VERSION 5.8 ;
BUSBITCHARS "[]" ;
DIVIDERCHAR "/" ;
UNITS
    DATABASE MICRONS 1000 ;
END UNITS

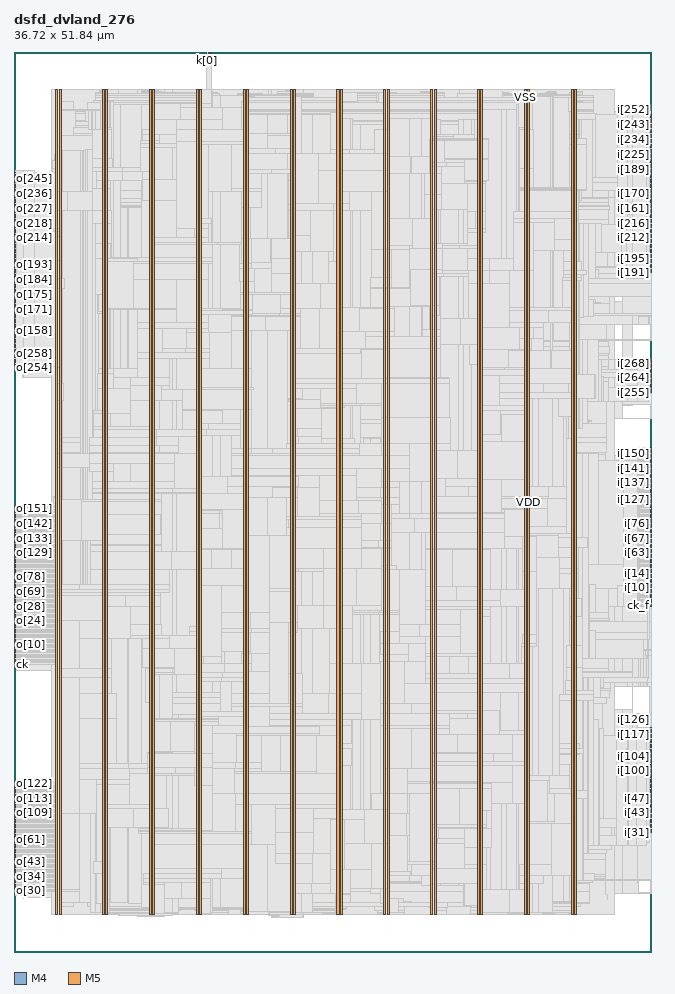
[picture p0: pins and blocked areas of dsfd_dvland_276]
MACRO dsfd_dvland_276
  FOREIGN dsfd_dvland_276 0 0 ;
  CLASS BLOCK ;
  SIZE 36.72 BY 51.84 ;
  PIN ck
    DIRECTION INPUT ;
    USE SIGNAL ;
    PORT
      LAYER M4 ;
        RECT  0 16.56 0.084 16.584 ;
    END
  END ck
  PIN ck_f
    DIRECTION INPUT ;
    USE SIGNAL ;
    PORT
      LAYER M4 ;
        RECT  36.636 19.92 36.72 19.944 ;
    END
  END ck_f
  PIN fault
    DIRECTION OUTPUT ;
    USE SIGNAL ;
    PORT
      LAYER M4 ;
        RECT  0 16.656 0.084 16.68 ;
    END
  END fault
  PIN i[0]
    DIRECTION INPUT ;
    USE SIGNAL ;
    PORT
      LAYER M4 ;
        RECT  36.636 20.016 36.72 20.04 ;
    END
  END i[0]
  PIN i[100]
    DIRECTION INPUT ;
    USE SIGNAL ;
    PORT
      LAYER M4 ;
        RECT  36.636 10.416 36.72 10.44 ;
    END
  END i[100]
  PIN i[101]
    DIRECTION INPUT ;
    USE SIGNAL ;
    PORT
      LAYER M4 ;
        RECT  36.636 10.512 36.72 10.536 ;
    END
  END i[101]
  PIN i[102]
    DIRECTION INPUT ;
    USE SIGNAL ;
    PORT
      LAYER M4 ;
        RECT  36.636 10.608 36.72 10.632 ;
    END
  END i[102]
  PIN i[103]
    DIRECTION INPUT ;
    USE SIGNAL ;
    PORT
      LAYER M4 ;
        RECT  36.636 10.704 36.72 10.728 ;
    END
  END i[103]
  PIN i[104]
    DIRECTION INPUT ;
    USE SIGNAL ;
    PORT
      LAYER M4 ;
        RECT  36.636 10.8 36.72 10.824 ;
    END
  END i[104]
  PIN i[105]
    DIRECTION INPUT ;
    USE SIGNAL ;
    PORT
      LAYER M4 ;
        RECT  36.636 10.896 36.72 10.92 ;
    END
  END i[105]
  PIN i[106]
    DIRECTION INPUT ;
    USE SIGNAL ;
    PORT
      LAYER M4 ;
        RECT  36.636 10.992 36.72 11.016 ;
    END
  END i[106]
  PIN i[107]
    DIRECTION INPUT ;
    USE SIGNAL ;
    PORT
      LAYER M4 ;
        RECT  36.636 11.088 36.72 11.112 ;
    END
  END i[107]
  PIN i[108]
    DIRECTION INPUT ;
    USE SIGNAL ;
    PORT
      LAYER M4 ;
        RECT  36.636 11.184 36.72 11.208 ;
    END
  END i[108]
  PIN i[109]
    DIRECTION INPUT ;
    USE SIGNAL ;
    PORT
      LAYER M4 ;
        RECT  36.636 11.28 36.72 11.304 ;
    END
  END i[109]
  PIN i[10]
    DIRECTION INPUT ;
    USE SIGNAL ;
    PORT
      LAYER M4 ;
        RECT  36.636 20.976 36.72 21 ;
    END
  END i[10]
  PIN i[110]
    DIRECTION INPUT ;
    USE SIGNAL ;
    PORT
      LAYER M4 ;
        RECT  36.636 11.376 36.72 11.4 ;
    END
  END i[110]
  PIN i[111]
    DIRECTION INPUT ;
    USE SIGNAL ;
    PORT
      LAYER M4 ;
        RECT  36.636 11.472 36.72 11.496 ;
    END
  END i[111]
  PIN i[112]
    DIRECTION INPUT ;
    USE SIGNAL ;
    PORT
      LAYER M4 ;
        RECT  36.636 11.568 36.72 11.592 ;
    END
  END i[112]
  PIN i[113]
    DIRECTION INPUT ;
    USE SIGNAL ;
    PORT
      LAYER M4 ;
        RECT  36.636 11.664 36.72 11.688 ;
    END
  END i[113]
  PIN i[114]
    DIRECTION INPUT ;
    USE SIGNAL ;
    PORT
      LAYER M4 ;
        RECT  36.636 11.76 36.72 11.784 ;
    END
  END i[114]
  PIN i[115]
    DIRECTION INPUT ;
    USE SIGNAL ;
    PORT
      LAYER M4 ;
        RECT  36.636 11.856 36.72 11.88 ;
    END
  END i[115]
  PIN i[116]
    DIRECTION INPUT ;
    USE SIGNAL ;
    PORT
      LAYER M4 ;
        RECT  36.636 11.952 36.72 11.976 ;
    END
  END i[116]
  PIN i[117]
    DIRECTION INPUT ;
    USE SIGNAL ;
    PORT
      LAYER M4 ;
        RECT  36.636 12.048 36.72 12.072 ;
    END
  END i[117]
  PIN i[118]
    DIRECTION INPUT ;
    USE SIGNAL ;
    PORT
      LAYER M4 ;
        RECT  36.636 12.144 36.72 12.168 ;
    END
  END i[118]
  PIN i[119]
    DIRECTION INPUT ;
    USE SIGNAL ;
    PORT
      LAYER M4 ;
        RECT  36.636 12.24 36.72 12.264 ;
    END
  END i[119]
  PIN i[11]
    DIRECTION INPUT ;
    USE SIGNAL ;
    PORT
      LAYER M4 ;
        RECT  36.636 21.072 36.72 21.096 ;
    END
  END i[11]
  PIN i[120]
    DIRECTION INPUT ;
    USE SIGNAL ;
    PORT
      LAYER M4 ;
        RECT  36.636 12.336 36.72 12.36 ;
    END
  END i[120]
  PIN i[121]
    DIRECTION INPUT ;
    USE SIGNAL ;
    PORT
      LAYER M4 ;
        RECT  36.636 12.432 36.72 12.456 ;
    END
  END i[121]
  PIN i[122]
    DIRECTION INPUT ;
    USE SIGNAL ;
    PORT
      LAYER M4 ;
        RECT  36.636 12.528 36.72 12.552 ;
    END
  END i[122]
  PIN i[123]
    DIRECTION INPUT ;
    USE SIGNAL ;
    PORT
      LAYER M4 ;
        RECT  36.636 12.624 36.72 12.648 ;
    END
  END i[123]
  PIN i[124]
    DIRECTION INPUT ;
    USE SIGNAL ;
    PORT
      LAYER M4 ;
        RECT  36.636 12.72 36.72 12.744 ;
    END
  END i[124]
  PIN i[125]
    DIRECTION INPUT ;
    USE SIGNAL ;
    PORT
      LAYER M4 ;
        RECT  36.636 12.816 36.72 12.84 ;
    END
  END i[125]
  PIN i[126]
    DIRECTION INPUT ;
    USE SIGNAL ;
    PORT
      LAYER M4 ;
        RECT  36.636 12.912 36.72 12.936 ;
    END
  END i[126]
  PIN i[127]
    DIRECTION INPUT ;
    USE SIGNAL ;
    PORT
      LAYER M4 ;
        RECT  36.636 26.064 36.72 26.088 ;
    END
  END i[127]
  PIN i[128]
    DIRECTION INPUT ;
    USE SIGNAL ;
    PORT
      LAYER M4 ;
        RECT  36.636 26.16 36.72 26.184 ;
    END
  END i[128]
  PIN i[129]
    DIRECTION INPUT ;
    USE SIGNAL ;
    PORT
      LAYER M4 ;
        RECT  36.636 26.256 36.72 26.28 ;
    END
  END i[129]
  PIN i[12]
    DIRECTION INPUT ;
    USE SIGNAL ;
    PORT
      LAYER M4 ;
        RECT  36.636 21.168 36.72 21.192 ;
    END
  END i[12]
  PIN i[130]
    DIRECTION INPUT ;
    USE SIGNAL ;
    PORT
      LAYER M4 ;
        RECT  36.636 26.352 36.72 26.376 ;
    END
  END i[130]
  PIN i[131]
    DIRECTION INPUT ;
    USE SIGNAL ;
    PORT
      LAYER M4 ;
        RECT  36.636 26.448 36.72 26.472 ;
    END
  END i[131]
  PIN i[132]
    DIRECTION INPUT ;
    USE SIGNAL ;
    PORT
      LAYER M4 ;
        RECT  36.636 26.544 36.72 26.568 ;
    END
  END i[132]
  PIN i[133]
    DIRECTION INPUT ;
    USE SIGNAL ;
    PORT
      LAYER M4 ;
        RECT  36.636 26.64 36.72 26.664 ;
    END
  END i[133]
  PIN i[134]
    DIRECTION INPUT ;
    USE SIGNAL ;
    PORT
      LAYER M4 ;
        RECT  36.636 26.736 36.72 26.76 ;
    END
  END i[134]
  PIN i[135]
    DIRECTION INPUT ;
    USE SIGNAL ;
    PORT
      LAYER M4 ;
        RECT  36.636 26.832 36.72 26.856 ;
    END
  END i[135]
  PIN i[136]
    DIRECTION INPUT ;
    USE SIGNAL ;
    PORT
      LAYER M4 ;
        RECT  36.636 26.928 36.72 26.952 ;
    END
  END i[136]
  PIN i[137]
    DIRECTION INPUT ;
    USE SIGNAL ;
    PORT
      LAYER M4 ;
        RECT  36.636 27.024 36.72 27.048 ;
    END
  END i[137]
  PIN i[138]
    DIRECTION INPUT ;
    USE SIGNAL ;
    PORT
      LAYER M4 ;
        RECT  36.636 27.12 36.72 27.144 ;
    END
  END i[138]
  PIN i[139]
    DIRECTION INPUT ;
    USE SIGNAL ;
    PORT
      LAYER M4 ;
        RECT  36.636 27.216 36.72 27.24 ;
    END
  END i[139]
  PIN i[13]
    DIRECTION INPUT ;
    USE SIGNAL ;
    PORT
      LAYER M4 ;
        RECT  36.636 21.264 36.72 21.288 ;
    END
  END i[13]
  PIN i[140]
    DIRECTION INPUT ;
    USE SIGNAL ;
    PORT
      LAYER M4 ;
        RECT  36.636 27.312 36.72 27.336 ;
    END
  END i[140]
  PIN i[141]
    DIRECTION INPUT ;
    USE SIGNAL ;
    PORT
      LAYER M4 ;
        RECT  36.636 27.408 36.72 27.432 ;
    END
  END i[141]
  PIN i[142]
    DIRECTION INPUT ;
    USE SIGNAL ;
    PORT
      LAYER M4 ;
        RECT  36.636 27.504 36.72 27.528 ;
    END
  END i[142]
  PIN i[143]
    DIRECTION INPUT ;
    USE SIGNAL ;
    PORT
      LAYER M4 ;
        RECT  36.636 27.6 36.72 27.624 ;
    END
  END i[143]
  PIN i[144]
    DIRECTION INPUT ;
    USE SIGNAL ;
    PORT
      LAYER M4 ;
        RECT  36.636 27.696 36.72 27.72 ;
    END
  END i[144]
  PIN i[145]
    DIRECTION INPUT ;
    USE SIGNAL ;
    PORT
      LAYER M4 ;
        RECT  36.636 27.792 36.72 27.816 ;
    END
  END i[145]
  PIN i[146]
    DIRECTION INPUT ;
    USE SIGNAL ;
    PORT
      LAYER M4 ;
        RECT  36.636 27.888 36.72 27.912 ;
    END
  END i[146]
  PIN i[147]
    DIRECTION INPUT ;
    USE SIGNAL ;
    PORT
      LAYER M4 ;
        RECT  36.636 27.984 36.72 28.008 ;
    END
  END i[147]
  PIN i[148]
    DIRECTION INPUT ;
    USE SIGNAL ;
    PORT
      LAYER M4 ;
        RECT  36.636 28.08 36.72 28.104 ;
    END
  END i[148]
  PIN i[149]
    DIRECTION INPUT ;
    USE SIGNAL ;
    PORT
      LAYER M4 ;
        RECT  36.636 28.176 36.72 28.2 ;
    END
  END i[149]
  PIN i[14]
    DIRECTION INPUT ;
    USE SIGNAL ;
    PORT
      LAYER M4 ;
        RECT  36.636 21.36 36.72 21.384 ;
    END
  END i[14]
  PIN i[150]
    DIRECTION INPUT ;
    USE SIGNAL ;
    PORT
      LAYER M4 ;
        RECT  36.636 28.272 36.72 28.296 ;
    END
  END i[150]
  PIN i[151]
    DIRECTION INPUT ;
    USE SIGNAL ;
    PORT
      LAYER M4 ;
        RECT  36.636 28.368 36.72 28.392 ;
    END
  END i[151]
  PIN i[152]
    DIRECTION INPUT ;
    USE SIGNAL ;
    PORT
      LAYER M4 ;
        RECT  36.636 28.464 36.72 28.488 ;
    END
  END i[152]
  PIN i[153]
    DIRECTION INPUT ;
    USE SIGNAL ;
    PORT
      LAYER M4 ;
        RECT  36.636 28.56 36.72 28.584 ;
    END
  END i[153]
  PIN i[154]
    DIRECTION INPUT ;
    USE SIGNAL ;
    PORT
      LAYER M4 ;
        RECT  36.636 28.656 36.72 28.68 ;
    END
  END i[154]
  PIN i[155]
    DIRECTION INPUT ;
    USE SIGNAL ;
    PORT
      LAYER M4 ;
        RECT  36.636 28.752 36.72 28.776 ;
    END
  END i[155]
  PIN i[156]
    DIRECTION INPUT ;
    USE SIGNAL ;
    PORT
      LAYER M4 ;
        RECT  36.636 28.848 36.72 28.872 ;
    END
  END i[156]
  PIN i[157]
    DIRECTION INPUT ;
    USE SIGNAL ;
    PORT
      LAYER M4 ;
        RECT  36.636 28.944 36.72 28.968 ;
    END
  END i[157]
  PIN i[158]
    DIRECTION INPUT ;
    USE SIGNAL ;
    PORT
      LAYER M4 ;
        RECT  36.636 29.04 36.72 29.064 ;
    END
  END i[158]
  PIN i[159]
    DIRECTION INPUT ;
    USE SIGNAL ;
    PORT
      LAYER M4 ;
        RECT  36.636 42.192 36.72 42.216 ;
    END
  END i[159]
  PIN i[15]
    DIRECTION INPUT ;
    USE SIGNAL ;
    PORT
      LAYER M4 ;
        RECT  36.636 21.456 36.72 21.48 ;
    END
  END i[15]
  PIN i[160]
    DIRECTION INPUT ;
    USE SIGNAL ;
    PORT
      LAYER M4 ;
        RECT  36.636 42.288 36.72 42.312 ;
    END
  END i[160]
  PIN i[161]
    DIRECTION INPUT ;
    USE SIGNAL ;
    PORT
      LAYER M4 ;
        RECT  36.636 42.384 36.72 42.408 ;
    END
  END i[161]
  PIN i[162]
    DIRECTION INPUT ;
    USE SIGNAL ;
    PORT
      LAYER M4 ;
        RECT  36.636 42.48 36.72 42.504 ;
    END
  END i[162]
  PIN i[163]
    DIRECTION INPUT ;
    USE SIGNAL ;
    PORT
      LAYER M4 ;
        RECT  36.636 42.576 36.72 42.6 ;
    END
  END i[163]
  PIN i[164]
    DIRECTION INPUT ;
    USE SIGNAL ;
    PORT
      LAYER M4 ;
        RECT  36.636 42.672 36.72 42.696 ;
    END
  END i[164]
  PIN i[165]
    DIRECTION INPUT ;
    USE SIGNAL ;
    PORT
      LAYER M4 ;
        RECT  36.636 42.768 36.72 42.792 ;
    END
  END i[165]
  PIN i[166]
    DIRECTION INPUT ;
    USE SIGNAL ;
    PORT
      LAYER M4 ;
        RECT  36.636 42.864 36.72 42.888 ;
    END
  END i[166]
  PIN i[167]
    DIRECTION INPUT ;
    USE SIGNAL ;
    PORT
      LAYER M4 ;
        RECT  36.636 42.96 36.72 42.984 ;
    END
  END i[167]
  PIN i[168]
    DIRECTION INPUT ;
    USE SIGNAL ;
    PORT
      LAYER M4 ;
        RECT  36.636 43.056 36.72 43.08 ;
    END
  END i[168]
  PIN i[169]
    DIRECTION INPUT ;
    USE SIGNAL ;
    PORT
      LAYER M4 ;
        RECT  36.636 43.152 36.72 43.176 ;
    END
  END i[169]
  PIN i[16]
    DIRECTION INPUT ;
    USE SIGNAL ;
    PORT
      LAYER M4 ;
        RECT  36.636 21.552 36.72 21.576 ;
    END
  END i[16]
  PIN i[170]
    DIRECTION INPUT ;
    USE SIGNAL ;
    PORT
      LAYER M4 ;
        RECT  36.636 43.248 36.72 43.272 ;
    END
  END i[170]
  PIN i[171]
    DIRECTION INPUT ;
    USE SIGNAL ;
    PORT
      LAYER M4 ;
        RECT  36.636 43.344 36.72 43.368 ;
    END
  END i[171]
  PIN i[172]
    DIRECTION INPUT ;
    USE SIGNAL ;
    PORT
      LAYER M4 ;
        RECT  36.636 43.44 36.72 43.464 ;
    END
  END i[172]
  PIN i[173]
    DIRECTION INPUT ;
    USE SIGNAL ;
    PORT
      LAYER M4 ;
        RECT  36.636 43.536 36.72 43.56 ;
    END
  END i[173]
  PIN i[174]
    DIRECTION INPUT ;
    USE SIGNAL ;
    PORT
      LAYER M4 ;
        RECT  36.636 43.632 36.72 43.656 ;
    END
  END i[174]
  PIN i[175]
    DIRECTION INPUT ;
    USE SIGNAL ;
    PORT
      LAYER M4 ;
        RECT  36.636 43.728 36.72 43.752 ;
    END
  END i[175]
  PIN i[176]
    DIRECTION INPUT ;
    USE SIGNAL ;
    PORT
      LAYER M4 ;
        RECT  36.636 43.824 36.72 43.848 ;
    END
  END i[176]
  PIN i[177]
    DIRECTION INPUT ;
    USE SIGNAL ;
    PORT
      LAYER M4 ;
        RECT  36.636 43.92 36.72 43.944 ;
    END
  END i[177]
  PIN i[178]
    DIRECTION INPUT ;
    USE SIGNAL ;
    PORT
      LAYER M4 ;
        RECT  36.636 44.016 36.72 44.04 ;
    END
  END i[178]
  PIN i[179]
    DIRECTION INPUT ;
    USE SIGNAL ;
    PORT
      LAYER M4 ;
        RECT  36.636 44.112 36.72 44.136 ;
    END
  END i[179]
  PIN i[17]
    DIRECTION INPUT ;
    USE SIGNAL ;
    PORT
      LAYER M4 ;
        RECT  36.636 21.648 36.72 21.672 ;
    END
  END i[17]
  PIN i[180]
    DIRECTION INPUT ;
    USE SIGNAL ;
    PORT
      LAYER M4 ;
        RECT  36.636 44.208 36.72 44.232 ;
    END
  END i[180]
  PIN i[181]
    DIRECTION INPUT ;
    USE SIGNAL ;
    PORT
      LAYER M4 ;
        RECT  36.636 44.304 36.72 44.328 ;
    END
  END i[181]
  PIN i[182]
    DIRECTION INPUT ;
    USE SIGNAL ;
    PORT
      LAYER M4 ;
        RECT  36.636 44.4 36.72 44.424 ;
    END
  END i[182]
  PIN i[183]
    DIRECTION INPUT ;
    USE SIGNAL ;
    PORT
      LAYER M4 ;
        RECT  36.636 44.496 36.72 44.52 ;
    END
  END i[183]
  PIN i[184]
    DIRECTION INPUT ;
    USE SIGNAL ;
    PORT
      LAYER M4 ;
        RECT  36.636 44.592 36.72 44.616 ;
    END
  END i[184]
  PIN i[185]
    DIRECTION INPUT ;
    USE SIGNAL ;
    PORT
      LAYER M4 ;
        RECT  36.636 44.688 36.72 44.712 ;
    END
  END i[185]
  PIN i[186]
    DIRECTION INPUT ;
    USE SIGNAL ;
    PORT
      LAYER M4 ;
        RECT  36.636 44.784 36.72 44.808 ;
    END
  END i[186]
  PIN i[187]
    DIRECTION INPUT ;
    USE SIGNAL ;
    PORT
      LAYER M4 ;
        RECT  36.636 44.88 36.72 44.904 ;
    END
  END i[187]
  PIN i[188]
    DIRECTION INPUT ;
    USE SIGNAL ;
    PORT
      LAYER M4 ;
        RECT  36.636 44.976 36.72 45 ;
    END
  END i[188]
  PIN i[189]
    DIRECTION INPUT ;
    USE SIGNAL ;
    PORT
      LAYER M4 ;
        RECT  36.636 45.072 36.72 45.096 ;
    END
  END i[189]
  PIN i[18]
    DIRECTION INPUT ;
    USE SIGNAL ;
    PORT
      LAYER M4 ;
        RECT  36.636 21.744 36.72 21.768 ;
    END
  END i[18]
  PIN i[190]
    DIRECTION INPUT ;
    USE SIGNAL ;
    PORT
      LAYER M4 ;
        RECT  36.636 45.168 36.72 45.192 ;
    END
  END i[190]
  PIN i[191]
    DIRECTION INPUT ;
    USE SIGNAL ;
    PORT
      LAYER M4 ;
        RECT  36.636 39.12 36.72 39.144 ;
    END
  END i[191]
  PIN i[192]
    DIRECTION INPUT ;
    USE SIGNAL ;
    PORT
      LAYER M4 ;
        RECT  36.636 39.216 36.72 39.24 ;
    END
  END i[192]
  PIN i[193]
    DIRECTION INPUT ;
    USE SIGNAL ;
    PORT
      LAYER M4 ;
        RECT  36.636 39.312 36.72 39.336 ;
    END
  END i[193]
  PIN i[194]
    DIRECTION INPUT ;
    USE SIGNAL ;
    PORT
      LAYER M4 ;
        RECT  36.636 39.408 36.72 39.432 ;
    END
  END i[194]
  PIN i[195]
    DIRECTION INPUT ;
    USE SIGNAL ;
    PORT
      LAYER M4 ;
        RECT  36.636 39.504 36.72 39.528 ;
    END
  END i[195]
  PIN i[196]
    DIRECTION INPUT ;
    USE SIGNAL ;
    PORT
      LAYER M4 ;
        RECT  36.636 39.6 36.72 39.624 ;
    END
  END i[196]
  PIN i[197]
    DIRECTION INPUT ;
    USE SIGNAL ;
    PORT
      LAYER M4 ;
        RECT  36.636 39.696 36.72 39.72 ;
    END
  END i[197]
  PIN i[198]
    DIRECTION INPUT ;
    USE SIGNAL ;
    PORT
      LAYER M4 ;
        RECT  36.636 39.792 36.72 39.816 ;
    END
  END i[198]
  PIN i[199]
    DIRECTION INPUT ;
    USE SIGNAL ;
    PORT
      LAYER M4 ;
        RECT  36.636 39.888 36.72 39.912 ;
    END
  END i[199]
  PIN i[19]
    DIRECTION INPUT ;
    USE SIGNAL ;
    PORT
      LAYER M4 ;
        RECT  36.636 21.84 36.72 21.864 ;
    END
  END i[19]
  PIN i[1]
    DIRECTION INPUT ;
    USE SIGNAL ;
    PORT
      LAYER M4 ;
        RECT  36.636 20.112 36.72 20.136 ;
    END
  END i[1]
  PIN i[200]
    DIRECTION INPUT ;
    USE SIGNAL ;
    PORT
      LAYER M4 ;
        RECT  36.636 39.984 36.72 40.008 ;
    END
  END i[200]
  PIN i[201]
    DIRECTION INPUT ;
    USE SIGNAL ;
    PORT
      LAYER M4 ;
        RECT  36.636 40.08 36.72 40.104 ;
    END
  END i[201]
  PIN i[202]
    DIRECTION INPUT ;
    USE SIGNAL ;
    PORT
      LAYER M4 ;
        RECT  36.636 40.176 36.72 40.2 ;
    END
  END i[202]
  PIN i[203]
    DIRECTION INPUT ;
    USE SIGNAL ;
    PORT
      LAYER M4 ;
        RECT  36.636 40.272 36.72 40.296 ;
    END
  END i[203]
  PIN i[204]
    DIRECTION INPUT ;
    USE SIGNAL ;
    PORT
      LAYER M4 ;
        RECT  36.636 40.368 36.72 40.392 ;
    END
  END i[204]
  PIN i[205]
    DIRECTION INPUT ;
    USE SIGNAL ;
    PORT
      LAYER M4 ;
        RECT  36.636 40.464 36.72 40.488 ;
    END
  END i[205]
  PIN i[206]
    DIRECTION INPUT ;
    USE SIGNAL ;
    PORT
      LAYER M4 ;
        RECT  36.636 40.56 36.72 40.584 ;
    END
  END i[206]
  PIN i[207]
    DIRECTION INPUT ;
    USE SIGNAL ;
    PORT
      LAYER M4 ;
        RECT  36.636 40.656 36.72 40.68 ;
    END
  END i[207]
  PIN i[208]
    DIRECTION INPUT ;
    USE SIGNAL ;
    PORT
      LAYER M4 ;
        RECT  36.636 40.752 36.72 40.776 ;
    END
  END i[208]
  PIN i[209]
    DIRECTION INPUT ;
    USE SIGNAL ;
    PORT
      LAYER M4 ;
        RECT  36.636 40.848 36.72 40.872 ;
    END
  END i[209]
  PIN i[20]
    DIRECTION INPUT ;
    USE SIGNAL ;
    PORT
      LAYER M4 ;
        RECT  36.636 21.936 36.72 21.96 ;
    END
  END i[20]
  PIN i[210]
    DIRECTION INPUT ;
    USE SIGNAL ;
    PORT
      LAYER M4 ;
        RECT  36.636 40.944 36.72 40.968 ;
    END
  END i[210]
  PIN i[211]
    DIRECTION INPUT ;
    USE SIGNAL ;
    PORT
      LAYER M4 ;
        RECT  36.636 41.04 36.72 41.064 ;
    END
  END i[211]
  PIN i[212]
    DIRECTION INPUT ;
    USE SIGNAL ;
    PORT
      LAYER M4 ;
        RECT  36.636 41.136 36.72 41.16 ;
    END
  END i[212]
  PIN i[213]
    DIRECTION INPUT ;
    USE SIGNAL ;
    PORT
      LAYER M4 ;
        RECT  36.636 41.232 36.72 41.256 ;
    END
  END i[213]
  PIN i[214]
    DIRECTION INPUT ;
    USE SIGNAL ;
    PORT
      LAYER M4 ;
        RECT  36.636 41.328 36.72 41.352 ;
    END
  END i[214]
  PIN i[215]
    DIRECTION INPUT ;
    USE SIGNAL ;
    PORT
      LAYER M4 ;
        RECT  36.636 41.424 36.72 41.448 ;
    END
  END i[215]
  PIN i[216]
    DIRECTION INPUT ;
    USE SIGNAL ;
    PORT
      LAYER M4 ;
        RECT  36.636 41.52 36.72 41.544 ;
    END
  END i[216]
  PIN i[217]
    DIRECTION INPUT ;
    USE SIGNAL ;
    PORT
      LAYER M4 ;
        RECT  36.636 41.616 36.72 41.64 ;
    END
  END i[217]
  PIN i[218]
    DIRECTION INPUT ;
    USE SIGNAL ;
    PORT
      LAYER M4 ;
        RECT  36.636 41.712 36.72 41.736 ;
    END
  END i[218]
  PIN i[219]
    DIRECTION INPUT ;
    USE SIGNAL ;
    PORT
      LAYER M4 ;
        RECT  36.636 41.808 36.72 41.832 ;
    END
  END i[219]
  PIN i[21]
    DIRECTION INPUT ;
    USE SIGNAL ;
    PORT
      LAYER M4 ;
        RECT  36.636 22.032 36.72 22.056 ;
    END
  END i[21]
  PIN i[220]
    DIRECTION INPUT ;
    USE SIGNAL ;
    PORT
      LAYER M4 ;
        RECT  36.636 41.904 36.72 41.928 ;
    END
  END i[220]
  PIN i[221]
    DIRECTION INPUT ;
    USE SIGNAL ;
    PORT
      LAYER M4 ;
        RECT  36.636 42 36.72 42.024 ;
    END
  END i[221]
  PIN i[222]
    DIRECTION INPUT ;
    USE SIGNAL ;
    PORT
      LAYER M4 ;
        RECT  36.636 42.096 36.72 42.12 ;
    END
  END i[222]
  PIN i[223]
    DIRECTION INPUT ;
    USE SIGNAL ;
    PORT
      LAYER M4 ;
        RECT  36.636 45.264 36.72 45.288 ;
    END
  END i[223]
  PIN i[224]
    DIRECTION INPUT ;
    USE SIGNAL ;
    PORT
      LAYER M4 ;
        RECT  36.636 45.36 36.72 45.384 ;
    END
  END i[224]
  PIN i[225]
    DIRECTION INPUT ;
    USE SIGNAL ;
    PORT
      LAYER M4 ;
        RECT  36.636 45.456 36.72 45.48 ;
    END
  END i[225]
  PIN i[226]
    DIRECTION INPUT ;
    USE SIGNAL ;
    PORT
      LAYER M4 ;
        RECT  36.636 45.552 36.72 45.576 ;
    END
  END i[226]
  PIN i[227]
    DIRECTION INPUT ;
    USE SIGNAL ;
    PORT
      LAYER M4 ;
        RECT  36.636 45.648 36.72 45.672 ;
    END
  END i[227]
  PIN i[228]
    DIRECTION INPUT ;
    USE SIGNAL ;
    PORT
      LAYER M4 ;
        RECT  36.636 45.744 36.72 45.768 ;
    END
  END i[228]
  PIN i[229]
    DIRECTION INPUT ;
    USE SIGNAL ;
    PORT
      LAYER M4 ;
        RECT  36.636 45.84 36.72 45.864 ;
    END
  END i[229]
  PIN i[22]
    DIRECTION INPUT ;
    USE SIGNAL ;
    PORT
      LAYER M4 ;
        RECT  36.636 22.128 36.72 22.152 ;
    END
  END i[22]
  PIN i[230]
    DIRECTION INPUT ;
    USE SIGNAL ;
    PORT
      LAYER M4 ;
        RECT  36.636 45.936 36.72 45.96 ;
    END
  END i[230]
  PIN i[231]
    DIRECTION INPUT ;
    USE SIGNAL ;
    PORT
      LAYER M4 ;
        RECT  36.636 46.032 36.72 46.056 ;
    END
  END i[231]
  PIN i[232]
    DIRECTION INPUT ;
    USE SIGNAL ;
    PORT
      LAYER M4 ;
        RECT  36.636 46.128 36.72 46.152 ;
    END
  END i[232]
  PIN i[233]
    DIRECTION INPUT ;
    USE SIGNAL ;
    PORT
      LAYER M4 ;
        RECT  36.636 46.224 36.72 46.248 ;
    END
  END i[233]
  PIN i[234]
    DIRECTION INPUT ;
    USE SIGNAL ;
    PORT
      LAYER M4 ;
        RECT  36.636 46.32 36.72 46.344 ;
    END
  END i[234]
  PIN i[235]
    DIRECTION INPUT ;
    USE SIGNAL ;
    PORT
      LAYER M4 ;
        RECT  36.636 46.416 36.72 46.44 ;
    END
  END i[235]
  PIN i[236]
    DIRECTION INPUT ;
    USE SIGNAL ;
    PORT
      LAYER M4 ;
        RECT  36.636 46.512 36.72 46.536 ;
    END
  END i[236]
  PIN i[237]
    DIRECTION INPUT ;
    USE SIGNAL ;
    PORT
      LAYER M4 ;
        RECT  36.636 46.608 36.72 46.632 ;
    END
  END i[237]
  PIN i[238]
    DIRECTION INPUT ;
    USE SIGNAL ;
    PORT
      LAYER M4 ;
        RECT  36.636 46.704 36.72 46.728 ;
    END
  END i[238]
  PIN i[239]
    DIRECTION INPUT ;
    USE SIGNAL ;
    PORT
      LAYER M4 ;
        RECT  36.636 46.8 36.72 46.824 ;
    END
  END i[239]
  PIN i[23]
    DIRECTION INPUT ;
    USE SIGNAL ;
    PORT
      LAYER M4 ;
        RECT  36.636 22.224 36.72 22.248 ;
    END
  END i[23]
  PIN i[240]
    DIRECTION INPUT ;
    USE SIGNAL ;
    PORT
      LAYER M4 ;
        RECT  36.636 46.896 36.72 46.92 ;
    END
  END i[240]
  PIN i[241]
    DIRECTION INPUT ;
    USE SIGNAL ;
    PORT
      LAYER M4 ;
        RECT  36.636 46.992 36.72 47.016 ;
    END
  END i[241]
  PIN i[242]
    DIRECTION INPUT ;
    USE SIGNAL ;
    PORT
      LAYER M4 ;
        RECT  36.636 47.088 36.72 47.112 ;
    END
  END i[242]
  PIN i[243]
    DIRECTION INPUT ;
    USE SIGNAL ;
    PORT
      LAYER M4 ;
        RECT  36.636 47.184 36.72 47.208 ;
    END
  END i[243]
  PIN i[244]
    DIRECTION INPUT ;
    USE SIGNAL ;
    PORT
      LAYER M4 ;
        RECT  36.636 47.28 36.72 47.304 ;
    END
  END i[244]
  PIN i[245]
    DIRECTION INPUT ;
    USE SIGNAL ;
    PORT
      LAYER M4 ;
        RECT  36.636 47.376 36.72 47.4 ;
    END
  END i[245]
  PIN i[246]
    DIRECTION INPUT ;
    USE SIGNAL ;
    PORT
      LAYER M4 ;
        RECT  36.636 47.472 36.72 47.496 ;
    END
  END i[246]
  PIN i[247]
    DIRECTION INPUT ;
    USE SIGNAL ;
    PORT
      LAYER M4 ;
        RECT  36.636 47.568 36.72 47.592 ;
    END
  END i[247]
  PIN i[248]
    DIRECTION INPUT ;
    USE SIGNAL ;
    PORT
      LAYER M4 ;
        RECT  36.636 47.664 36.72 47.688 ;
    END
  END i[248]
  PIN i[249]
    DIRECTION INPUT ;
    USE SIGNAL ;
    PORT
      LAYER M4 ;
        RECT  36.636 47.76 36.72 47.784 ;
    END
  END i[249]
  PIN i[24]
    DIRECTION INPUT ;
    USE SIGNAL ;
    PORT
      LAYER M4 ;
        RECT  36.636 22.32 36.72 22.344 ;
    END
  END i[24]
  PIN i[250]
    DIRECTION INPUT ;
    USE SIGNAL ;
    PORT
      LAYER M4 ;
        RECT  36.636 47.856 36.72 47.88 ;
    END
  END i[250]
  PIN i[251]
    DIRECTION INPUT ;
    USE SIGNAL ;
    PORT
      LAYER M4 ;
        RECT  36.636 47.952 36.72 47.976 ;
    END
  END i[251]
  PIN i[252]
    DIRECTION INPUT ;
    USE SIGNAL ;
    PORT
      LAYER M4 ;
        RECT  36.636 48.048 36.72 48.072 ;
    END
  END i[252]
  PIN i[253]
    DIRECTION INPUT ;
    USE SIGNAL ;
    PORT
      LAYER M4 ;
        RECT  36.636 48.144 36.72 48.168 ;
    END
  END i[253]
  PIN i[254]
    DIRECTION INPUT ;
    USE SIGNAL ;
    PORT
      LAYER M4 ;
        RECT  36.636 48.24 36.72 48.264 ;
    END
  END i[254]
  PIN i[255]
    DIRECTION INPUT ;
    USE SIGNAL ;
    PORT
      LAYER M4 ;
        RECT  36.636 32.208 36.72 32.232 ;
    END
  END i[255]
  PIN i[256]
    DIRECTION INPUT ;
    USE SIGNAL ;
    PORT
      LAYER M4 ;
        RECT  36.636 32.304 36.72 32.328 ;
    END
  END i[256]
  PIN i[257]
    DIRECTION INPUT ;
    USE SIGNAL ;
    PORT
      LAYER M4 ;
        RECT  36.636 32.4 36.72 32.424 ;
    END
  END i[257]
  PIN i[258]
    DIRECTION INPUT ;
    USE SIGNAL ;
    PORT
      LAYER M4 ;
        RECT  36.636 32.496 36.72 32.52 ;
    END
  END i[258]
  PIN i[259]
    DIRECTION INPUT ;
    USE SIGNAL ;
    PORT
      LAYER M4 ;
        RECT  36.636 32.592 36.72 32.616 ;
    END
  END i[259]
  PIN i[25]
    DIRECTION INPUT ;
    USE SIGNAL ;
    PORT
      LAYER M4 ;
        RECT  36.636 22.416 36.72 22.44 ;
    END
  END i[25]
  PIN i[260]
    DIRECTION INPUT ;
    USE SIGNAL ;
    PORT
      LAYER M4 ;
        RECT  36.636 32.688 36.72 32.712 ;
    END
  END i[260]
  PIN i[261]
    DIRECTION INPUT ;
    USE SIGNAL ;
    PORT
      LAYER M4 ;
        RECT  36.636 32.784 36.72 32.808 ;
    END
  END i[261]
  PIN i[262]
    DIRECTION INPUT ;
    USE SIGNAL ;
    PORT
      LAYER M4 ;
        RECT  36.636 32.88 36.72 32.904 ;
    END
  END i[262]
  PIN i[263]
    DIRECTION INPUT ;
    USE SIGNAL ;
    PORT
      LAYER M4 ;
        RECT  36.636 32.976 36.72 33 ;
    END
  END i[263]
  PIN i[264]
    DIRECTION INPUT ;
    USE SIGNAL ;
    PORT
      LAYER M4 ;
        RECT  36.636 33.072 36.72 33.096 ;
    END
  END i[264]
  PIN i[265]
    DIRECTION INPUT ;
    USE SIGNAL ;
    PORT
      LAYER M4 ;
        RECT  36.636 33.168 36.72 33.192 ;
    END
  END i[265]
  PIN i[266]
    DIRECTION INPUT ;
    USE SIGNAL ;
    PORT
      LAYER M4 ;
        RECT  36.636 33.264 36.72 33.288 ;
    END
  END i[266]
  PIN i[267]
    DIRECTION INPUT ;
    USE SIGNAL ;
    PORT
      LAYER M4 ;
        RECT  36.636 33.36 36.72 33.384 ;
    END
  END i[267]
  PIN i[268]
    DIRECTION INPUT ;
    USE SIGNAL ;
    PORT
      LAYER M4 ;
        RECT  36.636 33.456 36.72 33.48 ;
    END
  END i[268]
  PIN i[269]
    DIRECTION INPUT ;
    USE SIGNAL ;
    PORT
      LAYER M4 ;
        RECT  36.636 33.552 36.72 33.576 ;
    END
  END i[269]
  PIN i[26]
    DIRECTION INPUT ;
    USE SIGNAL ;
    PORT
      LAYER M4 ;
        RECT  36.636 22.512 36.72 22.536 ;
    END
  END i[26]
  PIN i[270]
    DIRECTION INPUT ;
    USE SIGNAL ;
    PORT
      LAYER M4 ;
        RECT  36.636 33.648 36.72 33.672 ;
    END
  END i[270]
  PIN i[271]
    DIRECTION INPUT ;
    USE SIGNAL ;
    PORT
      LAYER M4 ;
        RECT  36.636 33.744 36.72 33.768 ;
    END
  END i[271]
  PIN i[272]
    DIRECTION INPUT ;
    USE SIGNAL ;
    PORT
      LAYER M4 ;
        RECT  36.636 33.84 36.72 33.864 ;
    END
  END i[272]
  PIN i[273]
    DIRECTION INPUT ;
    USE SIGNAL ;
    PORT
      LAYER M4 ;
        RECT  36.636 33.936 36.72 33.96 ;
    END
  END i[273]
  PIN i[274]
    DIRECTION INPUT ;
    USE SIGNAL ;
    PORT
      LAYER M4 ;
        RECT  36.636 34.032 36.72 34.056 ;
    END
  END i[274]
  PIN i[275]
    DIRECTION INPUT ;
    USE SIGNAL ;
    PORT
      LAYER M4 ;
        RECT  36.636 34.128 36.72 34.152 ;
    END
  END i[275]
  PIN i[27]
    DIRECTION INPUT ;
    USE SIGNAL ;
    PORT
      LAYER M4 ;
        RECT  36.636 22.608 36.72 22.632 ;
    END
  END i[27]
  PIN i[28]
    DIRECTION INPUT ;
    USE SIGNAL ;
    PORT
      LAYER M4 ;
        RECT  36.636 22.704 36.72 22.728 ;
    END
  END i[28]
  PIN i[29]
    DIRECTION INPUT ;
    USE SIGNAL ;
    PORT
      LAYER M4 ;
        RECT  36.636 22.8 36.72 22.824 ;
    END
  END i[29]
  PIN i[2]
    DIRECTION INPUT ;
    USE SIGNAL ;
    PORT
      LAYER M4 ;
        RECT  36.636 20.208 36.72 20.232 ;
    END
  END i[2]
  PIN i[30]
    DIRECTION INPUT ;
    USE SIGNAL ;
    PORT
      LAYER M4 ;
        RECT  36.636 22.896 36.72 22.92 ;
    END
  END i[30]
  PIN i[31]
    DIRECTION INPUT ;
    USE SIGNAL ;
    PORT
      LAYER M4 ;
        RECT  36.636 6.864 36.72 6.888 ;
    END
  END i[31]
  PIN i[32]
    DIRECTION INPUT ;
    USE SIGNAL ;
    PORT
      LAYER M4 ;
        RECT  36.636 6.96 36.72 6.984 ;
    END
  END i[32]
  PIN i[33]
    DIRECTION INPUT ;
    USE SIGNAL ;
    PORT
      LAYER M4 ;
        RECT  36.636 7.056 36.72 7.08 ;
    END
  END i[33]
  PIN i[34]
    DIRECTION INPUT ;
    USE SIGNAL ;
    PORT
      LAYER M4 ;
        RECT  36.636 7.152 36.72 7.176 ;
    END
  END i[34]
  PIN i[35]
    DIRECTION INPUT ;
    USE SIGNAL ;
    PORT
      LAYER M4 ;
        RECT  36.636 7.248 36.72 7.272 ;
    END
  END i[35]
  PIN i[36]
    DIRECTION INPUT ;
    USE SIGNAL ;
    PORT
      LAYER M4 ;
        RECT  36.636 7.344 36.72 7.368 ;
    END
  END i[36]
  PIN i[37]
    DIRECTION INPUT ;
    USE SIGNAL ;
    PORT
      LAYER M4 ;
        RECT  36.636 7.44 36.72 7.464 ;
    END
  END i[37]
  PIN i[38]
    DIRECTION INPUT ;
    USE SIGNAL ;
    PORT
      LAYER M4 ;
        RECT  36.636 7.536 36.72 7.56 ;
    END
  END i[38]
  PIN i[39]
    DIRECTION INPUT ;
    USE SIGNAL ;
    PORT
      LAYER M4 ;
        RECT  36.636 7.632 36.72 7.656 ;
    END
  END i[39]
  PIN i[3]
    DIRECTION INPUT ;
    USE SIGNAL ;
    PORT
      LAYER M4 ;
        RECT  36.636 20.304 36.72 20.328 ;
    END
  END i[3]
  PIN i[40]
    DIRECTION INPUT ;
    USE SIGNAL ;
    PORT
      LAYER M4 ;
        RECT  36.636 7.728 36.72 7.752 ;
    END
  END i[40]
  PIN i[41]
    DIRECTION INPUT ;
    USE SIGNAL ;
    PORT
      LAYER M4 ;
        RECT  36.636 7.824 36.72 7.848 ;
    END
  END i[41]
  PIN i[42]
    DIRECTION INPUT ;
    USE SIGNAL ;
    PORT
      LAYER M4 ;
        RECT  36.636 7.92 36.72 7.944 ;
    END
  END i[42]
  PIN i[43]
    DIRECTION INPUT ;
    USE SIGNAL ;
    PORT
      LAYER M4 ;
        RECT  36.636 8.016 36.72 8.04 ;
    END
  END i[43]
  PIN i[44]
    DIRECTION INPUT ;
    USE SIGNAL ;
    PORT
      LAYER M4 ;
        RECT  36.636 8.112 36.72 8.136 ;
    END
  END i[44]
  PIN i[45]
    DIRECTION INPUT ;
    USE SIGNAL ;
    PORT
      LAYER M4 ;
        RECT  36.636 8.208 36.72 8.232 ;
    END
  END i[45]
  PIN i[46]
    DIRECTION INPUT ;
    USE SIGNAL ;
    PORT
      LAYER M4 ;
        RECT  36.636 8.304 36.72 8.328 ;
    END
  END i[46]
  PIN i[47]
    DIRECTION INPUT ;
    USE SIGNAL ;
    PORT
      LAYER M4 ;
        RECT  36.636 8.4 36.72 8.424 ;
    END
  END i[47]
  PIN i[48]
    DIRECTION INPUT ;
    USE SIGNAL ;
    PORT
      LAYER M4 ;
        RECT  36.636 8.496 36.72 8.52 ;
    END
  END i[48]
  PIN i[49]
    DIRECTION INPUT ;
    USE SIGNAL ;
    PORT
      LAYER M4 ;
        RECT  36.636 8.592 36.72 8.616 ;
    END
  END i[49]
  PIN i[4]
    DIRECTION INPUT ;
    USE SIGNAL ;
    PORT
      LAYER M4 ;
        RECT  36.636 20.4 36.72 20.424 ;
    END
  END i[4]
  PIN i[50]
    DIRECTION INPUT ;
    USE SIGNAL ;
    PORT
      LAYER M4 ;
        RECT  36.636 8.688 36.72 8.712 ;
    END
  END i[50]
  PIN i[51]
    DIRECTION INPUT ;
    USE SIGNAL ;
    PORT
      LAYER M4 ;
        RECT  36.636 8.784 36.72 8.808 ;
    END
  END i[51]
  PIN i[52]
    DIRECTION INPUT ;
    USE SIGNAL ;
    PORT
      LAYER M4 ;
        RECT  36.636 8.88 36.72 8.904 ;
    END
  END i[52]
  PIN i[53]
    DIRECTION INPUT ;
    USE SIGNAL ;
    PORT
      LAYER M4 ;
        RECT  36.636 8.976 36.72 9 ;
    END
  END i[53]
  PIN i[54]
    DIRECTION INPUT ;
    USE SIGNAL ;
    PORT
      LAYER M4 ;
        RECT  36.636 9.072 36.72 9.096 ;
    END
  END i[54]
  PIN i[55]
    DIRECTION INPUT ;
    USE SIGNAL ;
    PORT
      LAYER M4 ;
        RECT  36.636 9.168 36.72 9.192 ;
    END
  END i[55]
  PIN i[56]
    DIRECTION INPUT ;
    USE SIGNAL ;
    PORT
      LAYER M4 ;
        RECT  36.636 9.264 36.72 9.288 ;
    END
  END i[56]
  PIN i[57]
    DIRECTION INPUT ;
    USE SIGNAL ;
    PORT
      LAYER M4 ;
        RECT  36.636 9.36 36.72 9.384 ;
    END
  END i[57]
  PIN i[58]
    DIRECTION INPUT ;
    USE SIGNAL ;
    PORT
      LAYER M4 ;
        RECT  36.636 9.456 36.72 9.48 ;
    END
  END i[58]
  PIN i[59]
    DIRECTION INPUT ;
    USE SIGNAL ;
    PORT
      LAYER M4 ;
        RECT  36.636 9.552 36.72 9.576 ;
    END
  END i[59]
  PIN i[5]
    DIRECTION INPUT ;
    USE SIGNAL ;
    PORT
      LAYER M4 ;
        RECT  36.636 20.496 36.72 20.52 ;
    END
  END i[5]
  PIN i[60]
    DIRECTION INPUT ;
    USE SIGNAL ;
    PORT
      LAYER M4 ;
        RECT  36.636 9.648 36.72 9.672 ;
    END
  END i[60]
  PIN i[61]
    DIRECTION INPUT ;
    USE SIGNAL ;
    PORT
      LAYER M4 ;
        RECT  36.636 9.744 36.72 9.768 ;
    END
  END i[61]
  PIN i[62]
    DIRECTION INPUT ;
    USE SIGNAL ;
    PORT
      LAYER M4 ;
        RECT  36.636 9.84 36.72 9.864 ;
    END
  END i[62]
  PIN i[63]
    DIRECTION INPUT ;
    USE SIGNAL ;
    PORT
      LAYER M4 ;
        RECT  36.636 22.992 36.72 23.016 ;
    END
  END i[63]
  PIN i[64]
    DIRECTION INPUT ;
    USE SIGNAL ;
    PORT
      LAYER M4 ;
        RECT  36.636 23.088 36.72 23.112 ;
    END
  END i[64]
  PIN i[65]
    DIRECTION INPUT ;
    USE SIGNAL ;
    PORT
      LAYER M4 ;
        RECT  36.636 23.184 36.72 23.208 ;
    END
  END i[65]
  PIN i[66]
    DIRECTION INPUT ;
    USE SIGNAL ;
    PORT
      LAYER M4 ;
        RECT  36.636 23.28 36.72 23.304 ;
    END
  END i[66]
  PIN i[67]
    DIRECTION INPUT ;
    USE SIGNAL ;
    PORT
      LAYER M4 ;
        RECT  36.636 23.376 36.72 23.4 ;
    END
  END i[67]
  PIN i[68]
    DIRECTION INPUT ;
    USE SIGNAL ;
    PORT
      LAYER M4 ;
        RECT  36.636 23.472 36.72 23.496 ;
    END
  END i[68]
  PIN i[69]
    DIRECTION INPUT ;
    USE SIGNAL ;
    PORT
      LAYER M4 ;
        RECT  36.636 23.568 36.72 23.592 ;
    END
  END i[69]
  PIN i[6]
    DIRECTION INPUT ;
    USE SIGNAL ;
    PORT
      LAYER M4 ;
        RECT  36.636 20.592 36.72 20.616 ;
    END
  END i[6]
  PIN i[70]
    DIRECTION INPUT ;
    USE SIGNAL ;
    PORT
      LAYER M4 ;
        RECT  36.636 23.664 36.72 23.688 ;
    END
  END i[70]
  PIN i[71]
    DIRECTION INPUT ;
    USE SIGNAL ;
    PORT
      LAYER M4 ;
        RECT  36.636 23.76 36.72 23.784 ;
    END
  END i[71]
  PIN i[72]
    DIRECTION INPUT ;
    USE SIGNAL ;
    PORT
      LAYER M4 ;
        RECT  36.636 23.856 36.72 23.88 ;
    END
  END i[72]
  PIN i[73]
    DIRECTION INPUT ;
    USE SIGNAL ;
    PORT
      LAYER M4 ;
        RECT  36.636 23.952 36.72 23.976 ;
    END
  END i[73]
  PIN i[74]
    DIRECTION INPUT ;
    USE SIGNAL ;
    PORT
      LAYER M4 ;
        RECT  36.636 24.048 36.72 24.072 ;
    END
  END i[74]
  PIN i[75]
    DIRECTION INPUT ;
    USE SIGNAL ;
    PORT
      LAYER M4 ;
        RECT  36.636 24.144 36.72 24.168 ;
    END
  END i[75]
  PIN i[76]
    DIRECTION INPUT ;
    USE SIGNAL ;
    PORT
      LAYER M4 ;
        RECT  36.636 24.24 36.72 24.264 ;
    END
  END i[76]
  PIN i[77]
    DIRECTION INPUT ;
    USE SIGNAL ;
    PORT
      LAYER M4 ;
        RECT  36.636 24.336 36.72 24.36 ;
    END
  END i[77]
  PIN i[78]
    DIRECTION INPUT ;
    USE SIGNAL ;
    PORT
      LAYER M4 ;
        RECT  36.636 24.432 36.72 24.456 ;
    END
  END i[78]
  PIN i[79]
    DIRECTION INPUT ;
    USE SIGNAL ;
    PORT
      LAYER M4 ;
        RECT  36.636 24.528 36.72 24.552 ;
    END
  END i[79]
  PIN i[7]
    DIRECTION INPUT ;
    USE SIGNAL ;
    PORT
      LAYER M4 ;
        RECT  36.636 20.688 36.72 20.712 ;
    END
  END i[7]
  PIN i[80]
    DIRECTION INPUT ;
    USE SIGNAL ;
    PORT
      LAYER M4 ;
        RECT  36.636 24.624 36.72 24.648 ;
    END
  END i[80]
  PIN i[81]
    DIRECTION INPUT ;
    USE SIGNAL ;
    PORT
      LAYER M4 ;
        RECT  36.636 24.72 36.72 24.744 ;
    END
  END i[81]
  PIN i[82]
    DIRECTION INPUT ;
    USE SIGNAL ;
    PORT
      LAYER M4 ;
        RECT  36.636 24.816 36.72 24.84 ;
    END
  END i[82]
  PIN i[83]
    DIRECTION INPUT ;
    USE SIGNAL ;
    PORT
      LAYER M4 ;
        RECT  36.636 24.912 36.72 24.936 ;
    END
  END i[83]
  PIN i[84]
    DIRECTION INPUT ;
    USE SIGNAL ;
    PORT
      LAYER M4 ;
        RECT  36.636 25.008 36.72 25.032 ;
    END
  END i[84]
  PIN i[85]
    DIRECTION INPUT ;
    USE SIGNAL ;
    PORT
      LAYER M4 ;
        RECT  36.636 25.104 36.72 25.128 ;
    END
  END i[85]
  PIN i[86]
    DIRECTION INPUT ;
    USE SIGNAL ;
    PORT
      LAYER M4 ;
        RECT  36.636 25.2 36.72 25.224 ;
    END
  END i[86]
  PIN i[87]
    DIRECTION INPUT ;
    USE SIGNAL ;
    PORT
      LAYER M4 ;
        RECT  36.636 25.296 36.72 25.32 ;
    END
  END i[87]
  PIN i[88]
    DIRECTION INPUT ;
    USE SIGNAL ;
    PORT
      LAYER M4 ;
        RECT  36.636 25.392 36.72 25.416 ;
    END
  END i[88]
  PIN i[89]
    DIRECTION INPUT ;
    USE SIGNAL ;
    PORT
      LAYER M4 ;
        RECT  36.636 25.488 36.72 25.512 ;
    END
  END i[89]
  PIN i[8]
    DIRECTION INPUT ;
    USE SIGNAL ;
    PORT
      LAYER M4 ;
        RECT  36.636 20.784 36.72 20.808 ;
    END
  END i[8]
  PIN i[90]
    DIRECTION INPUT ;
    USE SIGNAL ;
    PORT
      LAYER M4 ;
        RECT  36.636 25.584 36.72 25.608 ;
    END
  END i[90]
  PIN i[91]
    DIRECTION INPUT ;
    USE SIGNAL ;
    PORT
      LAYER M4 ;
        RECT  36.636 25.68 36.72 25.704 ;
    END
  END i[91]
  PIN i[92]
    DIRECTION INPUT ;
    USE SIGNAL ;
    PORT
      LAYER M4 ;
        RECT  36.636 25.776 36.72 25.8 ;
    END
  END i[92]
  PIN i[93]
    DIRECTION INPUT ;
    USE SIGNAL ;
    PORT
      LAYER M4 ;
        RECT  36.636 25.872 36.72 25.896 ;
    END
  END i[93]
  PIN i[94]
    DIRECTION INPUT ;
    USE SIGNAL ;
    PORT
      LAYER M4 ;
        RECT  36.636 25.968 36.72 25.992 ;
    END
  END i[94]
  PIN i[95]
    DIRECTION INPUT ;
    USE SIGNAL ;
    PORT
      LAYER M4 ;
        RECT  36.636 9.936 36.72 9.96 ;
    END
  END i[95]
  PIN i[96]
    DIRECTION INPUT ;
    USE SIGNAL ;
    PORT
      LAYER M4 ;
        RECT  36.636 10.032 36.72 10.056 ;
    END
  END i[96]
  PIN i[97]
    DIRECTION INPUT ;
    USE SIGNAL ;
    PORT
      LAYER M4 ;
        RECT  36.636 10.128 36.72 10.152 ;
    END
  END i[97]
  PIN i[98]
    DIRECTION INPUT ;
    USE SIGNAL ;
    PORT
      LAYER M4 ;
        RECT  36.636 10.224 36.72 10.248 ;
    END
  END i[98]
  PIN i[99]
    DIRECTION INPUT ;
    USE SIGNAL ;
    PORT
      LAYER M4 ;
        RECT  36.636 10.32 36.72 10.344 ;
    END
  END i[99]
  PIN i[9]
    DIRECTION INPUT ;
    USE SIGNAL ;
    PORT
      LAYER M4 ;
        RECT  36.636 20.88 36.72 20.904 ;
    END
  END i[9]
  PIN k[0]
    DIRECTION INPUT ;
    USE SIGNAL ;
    PORT
      LAYER M5 ;
        RECT  11.088 51.756 11.112 51.84 ;
    END
  END k[0]
  PIN k[1]
    DIRECTION INPUT ;
    USE SIGNAL ;
    PORT
      LAYER M5 ;
        RECT  11.184 51.756 11.208 51.84 ;
    END
  END k[1]
  PIN k[2]
    DIRECTION INPUT ;
    USE SIGNAL ;
    PORT
      LAYER M5 ;
        RECT  11.28 51.756 11.304 51.84 ;
    END
  END k[2]
  PIN o[0]
    DIRECTION OUTPUT ;
    USE SIGNAL ;
    PORT
      LAYER M4 ;
        RECT  0 16.752 0.084 16.776 ;
    END
  END o[0]
  PIN o[100]
    DIRECTION OUTPUT ;
    USE SIGNAL ;
    PORT
      LAYER M4 ;
        RECT  0 7.152 0.084 7.176 ;
    END
  END o[100]
  PIN o[101]
    DIRECTION OUTPUT ;
    USE SIGNAL ;
    PORT
      LAYER M4 ;
        RECT  0 7.248 0.084 7.272 ;
    END
  END o[101]
  PIN o[102]
    DIRECTION OUTPUT ;
    USE SIGNAL ;
    PORT
      LAYER M4 ;
        RECT  0 7.344 0.084 7.368 ;
    END
  END o[102]
  PIN o[103]
    DIRECTION OUTPUT ;
    USE SIGNAL ;
    PORT
      LAYER M4 ;
        RECT  0 7.44 0.084 7.464 ;
    END
  END o[103]
  PIN o[104]
    DIRECTION OUTPUT ;
    USE SIGNAL ;
    PORT
      LAYER M4 ;
        RECT  0 7.536 0.084 7.56 ;
    END
  END o[104]
  PIN o[105]
    DIRECTION OUTPUT ;
    USE SIGNAL ;
    PORT
      LAYER M4 ;
        RECT  0 7.632 0.084 7.656 ;
    END
  END o[105]
  PIN o[106]
    DIRECTION OUTPUT ;
    USE SIGNAL ;
    PORT
      LAYER M4 ;
        RECT  0 7.728 0.084 7.752 ;
    END
  END o[106]
  PIN o[107]
    DIRECTION OUTPUT ;
    USE SIGNAL ;
    PORT
      LAYER M4 ;
        RECT  0 7.824 0.084 7.848 ;
    END
  END o[107]
  PIN o[108]
    DIRECTION OUTPUT ;
    USE SIGNAL ;
    PORT
      LAYER M4 ;
        RECT  0 7.92 0.084 7.944 ;
    END
  END o[108]
  PIN o[109]
    DIRECTION OUTPUT ;
    USE SIGNAL ;
    PORT
      LAYER M4 ;
        RECT  0 8.016 0.084 8.04 ;
    END
  END o[109]
  PIN o[10]
    DIRECTION OUTPUT ;
    USE SIGNAL ;
    PORT
      LAYER M4 ;
        RECT  0 17.712 0.084 17.736 ;
    END
  END o[10]
  PIN o[110]
    DIRECTION OUTPUT ;
    USE SIGNAL ;
    PORT
      LAYER M4 ;
        RECT  0 8.112 0.084 8.136 ;
    END
  END o[110]
  PIN o[111]
    DIRECTION OUTPUT ;
    USE SIGNAL ;
    PORT
      LAYER M4 ;
        RECT  0 8.208 0.084 8.232 ;
    END
  END o[111]
  PIN o[112]
    DIRECTION OUTPUT ;
    USE SIGNAL ;
    PORT
      LAYER M4 ;
        RECT  0 8.304 0.084 8.328 ;
    END
  END o[112]
  PIN o[113]
    DIRECTION OUTPUT ;
    USE SIGNAL ;
    PORT
      LAYER M4 ;
        RECT  0 8.4 0.084 8.424 ;
    END
  END o[113]
  PIN o[114]
    DIRECTION OUTPUT ;
    USE SIGNAL ;
    PORT
      LAYER M4 ;
        RECT  0 8.496 0.084 8.52 ;
    END
  END o[114]
  PIN o[115]
    DIRECTION OUTPUT ;
    USE SIGNAL ;
    PORT
      LAYER M4 ;
        RECT  0 8.592 0.084 8.616 ;
    END
  END o[115]
  PIN o[116]
    DIRECTION OUTPUT ;
    USE SIGNAL ;
    PORT
      LAYER M4 ;
        RECT  0 8.688 0.084 8.712 ;
    END
  END o[116]
  PIN o[117]
    DIRECTION OUTPUT ;
    USE SIGNAL ;
    PORT
      LAYER M4 ;
        RECT  0 8.784 0.084 8.808 ;
    END
  END o[117]
  PIN o[118]
    DIRECTION OUTPUT ;
    USE SIGNAL ;
    PORT
      LAYER M4 ;
        RECT  0 8.88 0.084 8.904 ;
    END
  END o[118]
  PIN o[119]
    DIRECTION OUTPUT ;
    USE SIGNAL ;
    PORT
      LAYER M4 ;
        RECT  0 8.976 0.084 9 ;
    END
  END o[119]
  PIN o[11]
    DIRECTION OUTPUT ;
    USE SIGNAL ;
    PORT
      LAYER M4 ;
        RECT  0 17.808 0.084 17.832 ;
    END
  END o[11]
  PIN o[120]
    DIRECTION OUTPUT ;
    USE SIGNAL ;
    PORT
      LAYER M4 ;
        RECT  0 9.072 0.084 9.096 ;
    END
  END o[120]
  PIN o[121]
    DIRECTION OUTPUT ;
    USE SIGNAL ;
    PORT
      LAYER M4 ;
        RECT  0 9.168 0.084 9.192 ;
    END
  END o[121]
  PIN o[122]
    DIRECTION OUTPUT ;
    USE SIGNAL ;
    PORT
      LAYER M4 ;
        RECT  0 9.264 0.084 9.288 ;
    END
  END o[122]
  PIN o[123]
    DIRECTION OUTPUT ;
    USE SIGNAL ;
    PORT
      LAYER M4 ;
        RECT  0 9.36 0.084 9.384 ;
    END
  END o[123]
  PIN o[124]
    DIRECTION OUTPUT ;
    USE SIGNAL ;
    PORT
      LAYER M4 ;
        RECT  0 9.456 0.084 9.48 ;
    END
  END o[124]
  PIN o[125]
    DIRECTION OUTPUT ;
    USE SIGNAL ;
    PORT
      LAYER M4 ;
        RECT  0 9.552 0.084 9.576 ;
    END
  END o[125]
  PIN o[126]
    DIRECTION OUTPUT ;
    USE SIGNAL ;
    PORT
      LAYER M4 ;
        RECT  0 22.704 0.084 22.728 ;
    END
  END o[126]
  PIN o[127]
    DIRECTION OUTPUT ;
    USE SIGNAL ;
    PORT
      LAYER M4 ;
        RECT  0 22.8 0.084 22.824 ;
    END
  END o[127]
  PIN o[128]
    DIRECTION OUTPUT ;
    USE SIGNAL ;
    PORT
      LAYER M4 ;
        RECT  0 22.896 0.084 22.92 ;
    END
  END o[128]
  PIN o[129]
    DIRECTION OUTPUT ;
    USE SIGNAL ;
    PORT
      LAYER M4 ;
        RECT  0 22.992 0.084 23.016 ;
    END
  END o[129]
  PIN o[12]
    DIRECTION OUTPUT ;
    USE SIGNAL ;
    PORT
      LAYER M4 ;
        RECT  0 17.904 0.084 17.928 ;
    END
  END o[12]
  PIN o[130]
    DIRECTION OUTPUT ;
    USE SIGNAL ;
    PORT
      LAYER M4 ;
        RECT  0 23.088 0.084 23.112 ;
    END
  END o[130]
  PIN o[131]
    DIRECTION OUTPUT ;
    USE SIGNAL ;
    PORT
      LAYER M4 ;
        RECT  0 23.184 0.084 23.208 ;
    END
  END o[131]
  PIN o[132]
    DIRECTION OUTPUT ;
    USE SIGNAL ;
    PORT
      LAYER M4 ;
        RECT  0 23.28 0.084 23.304 ;
    END
  END o[132]
  PIN o[133]
    DIRECTION OUTPUT ;
    USE SIGNAL ;
    PORT
      LAYER M4 ;
        RECT  0 23.376 0.084 23.4 ;
    END
  END o[133]
  PIN o[134]
    DIRECTION OUTPUT ;
    USE SIGNAL ;
    PORT
      LAYER M4 ;
        RECT  0 23.472 0.084 23.496 ;
    END
  END o[134]
  PIN o[135]
    DIRECTION OUTPUT ;
    USE SIGNAL ;
    PORT
      LAYER M4 ;
        RECT  0 23.568 0.084 23.592 ;
    END
  END o[135]
  PIN o[136]
    DIRECTION OUTPUT ;
    USE SIGNAL ;
    PORT
      LAYER M4 ;
        RECT  0 23.664 0.084 23.688 ;
    END
  END o[136]
  PIN o[137]
    DIRECTION OUTPUT ;
    USE SIGNAL ;
    PORT
      LAYER M4 ;
        RECT  0 23.76 0.084 23.784 ;
    END
  END o[137]
  PIN o[138]
    DIRECTION OUTPUT ;
    USE SIGNAL ;
    PORT
      LAYER M4 ;
        RECT  0 23.856 0.084 23.88 ;
    END
  END o[138]
  PIN o[139]
    DIRECTION OUTPUT ;
    USE SIGNAL ;
    PORT
      LAYER M4 ;
        RECT  0 23.952 0.084 23.976 ;
    END
  END o[139]
  PIN o[13]
    DIRECTION OUTPUT ;
    USE SIGNAL ;
    PORT
      LAYER M4 ;
        RECT  0 18 0.084 18.024 ;
    END
  END o[13]
  PIN o[140]
    DIRECTION OUTPUT ;
    USE SIGNAL ;
    PORT
      LAYER M4 ;
        RECT  0 24.048 0.084 24.072 ;
    END
  END o[140]
  PIN o[141]
    DIRECTION OUTPUT ;
    USE SIGNAL ;
    PORT
      LAYER M4 ;
        RECT  0 24.144 0.084 24.168 ;
    END
  END o[141]
  PIN o[142]
    DIRECTION OUTPUT ;
    USE SIGNAL ;
    PORT
      LAYER M4 ;
        RECT  0 24.24 0.084 24.264 ;
    END
  END o[142]
  PIN o[143]
    DIRECTION OUTPUT ;
    USE SIGNAL ;
    PORT
      LAYER M4 ;
        RECT  0 24.336 0.084 24.36 ;
    END
  END o[143]
  PIN o[144]
    DIRECTION OUTPUT ;
    USE SIGNAL ;
    PORT
      LAYER M4 ;
        RECT  0 24.432 0.084 24.456 ;
    END
  END o[144]
  PIN o[145]
    DIRECTION OUTPUT ;
    USE SIGNAL ;
    PORT
      LAYER M4 ;
        RECT  0 24.528 0.084 24.552 ;
    END
  END o[145]
  PIN o[146]
    DIRECTION OUTPUT ;
    USE SIGNAL ;
    PORT
      LAYER M4 ;
        RECT  0 24.624 0.084 24.648 ;
    END
  END o[146]
  PIN o[147]
    DIRECTION OUTPUT ;
    USE SIGNAL ;
    PORT
      LAYER M4 ;
        RECT  0 24.72 0.084 24.744 ;
    END
  END o[147]
  PIN o[148]
    DIRECTION OUTPUT ;
    USE SIGNAL ;
    PORT
      LAYER M4 ;
        RECT  0 24.816 0.084 24.84 ;
    END
  END o[148]
  PIN o[149]
    DIRECTION OUTPUT ;
    USE SIGNAL ;
    PORT
      LAYER M4 ;
        RECT  0 24.912 0.084 24.936 ;
    END
  END o[149]
  PIN o[14]
    DIRECTION OUTPUT ;
    USE SIGNAL ;
    PORT
      LAYER M4 ;
        RECT  0 18.096 0.084 18.12 ;
    END
  END o[14]
  PIN o[150]
    DIRECTION OUTPUT ;
    USE SIGNAL ;
    PORT
      LAYER M4 ;
        RECT  0 25.008 0.084 25.032 ;
    END
  END o[150]
  PIN o[151]
    DIRECTION OUTPUT ;
    USE SIGNAL ;
    PORT
      LAYER M4 ;
        RECT  0 25.104 0.084 25.128 ;
    END
  END o[151]
  PIN o[152]
    DIRECTION OUTPUT ;
    USE SIGNAL ;
    PORT
      LAYER M4 ;
        RECT  0 25.2 0.084 25.224 ;
    END
  END o[152]
  PIN o[153]
    DIRECTION OUTPUT ;
    USE SIGNAL ;
    PORT
      LAYER M4 ;
        RECT  0 25.296 0.084 25.32 ;
    END
  END o[153]
  PIN o[154]
    DIRECTION OUTPUT ;
    USE SIGNAL ;
    PORT
      LAYER M4 ;
        RECT  0 25.392 0.084 25.416 ;
    END
  END o[154]
  PIN o[155]
    DIRECTION OUTPUT ;
    USE SIGNAL ;
    PORT
      LAYER M4 ;
        RECT  0 25.488 0.084 25.512 ;
    END
  END o[155]
  PIN o[156]
    DIRECTION OUTPUT ;
    USE SIGNAL ;
    PORT
      LAYER M4 ;
        RECT  0 25.584 0.084 25.608 ;
    END
  END o[156]
  PIN o[157]
    DIRECTION OUTPUT ;
    USE SIGNAL ;
    PORT
      LAYER M4 ;
        RECT  0 25.68 0.084 25.704 ;
    END
  END o[157]
  PIN o[158]
    DIRECTION OUTPUT ;
    USE SIGNAL ;
    PORT
      LAYER M4 ;
        RECT  0 35.76 0.084 35.784 ;
    END
  END o[158]
  PIN o[159]
    DIRECTION OUTPUT ;
    USE SIGNAL ;
    PORT
      LAYER M4 ;
        RECT  0 35.856 0.084 35.88 ;
    END
  END o[159]
  PIN o[15]
    DIRECTION OUTPUT ;
    USE SIGNAL ;
    PORT
      LAYER M4 ;
        RECT  0 18.192 0.084 18.216 ;
    END
  END o[15]
  PIN o[160]
    DIRECTION OUTPUT ;
    USE SIGNAL ;
    PORT
      LAYER M4 ;
        RECT  0 35.952 0.084 35.976 ;
    END
  END o[160]
  PIN o[161]
    DIRECTION OUTPUT ;
    USE SIGNAL ;
    PORT
      LAYER M4 ;
        RECT  0 36.048 0.084 36.072 ;
    END
  END o[161]
  PIN o[162]
    DIRECTION OUTPUT ;
    USE SIGNAL ;
    PORT
      LAYER M4 ;
        RECT  0 36.144 0.084 36.168 ;
    END
  END o[162]
  PIN o[163]
    DIRECTION OUTPUT ;
    USE SIGNAL ;
    PORT
      LAYER M4 ;
        RECT  0 36.24 0.084 36.264 ;
    END
  END o[163]
  PIN o[164]
    DIRECTION OUTPUT ;
    USE SIGNAL ;
    PORT
      LAYER M4 ;
        RECT  0 36.336 0.084 36.36 ;
    END
  END o[164]
  PIN o[165]
    DIRECTION OUTPUT ;
    USE SIGNAL ;
    PORT
      LAYER M4 ;
        RECT  0 36.432 0.084 36.456 ;
    END
  END o[165]
  PIN o[166]
    DIRECTION OUTPUT ;
    USE SIGNAL ;
    PORT
      LAYER M4 ;
        RECT  0 36.528 0.084 36.552 ;
    END
  END o[166]
  PIN o[167]
    DIRECTION OUTPUT ;
    USE SIGNAL ;
    PORT
      LAYER M4 ;
        RECT  0 36.624 0.084 36.648 ;
    END
  END o[167]
  PIN o[168]
    DIRECTION OUTPUT ;
    USE SIGNAL ;
    PORT
      LAYER M4 ;
        RECT  0 36.72 0.084 36.744 ;
    END
  END o[168]
  PIN o[169]
    DIRECTION OUTPUT ;
    USE SIGNAL ;
    PORT
      LAYER M4 ;
        RECT  0 36.816 0.084 36.84 ;
    END
  END o[169]
  PIN o[16]
    DIRECTION OUTPUT ;
    USE SIGNAL ;
    PORT
      LAYER M4 ;
        RECT  0 18.288 0.084 18.312 ;
    END
  END o[16]
  PIN o[170]
    DIRECTION OUTPUT ;
    USE SIGNAL ;
    PORT
      LAYER M4 ;
        RECT  0 36.912 0.084 36.936 ;
    END
  END o[170]
  PIN o[171]
    DIRECTION OUTPUT ;
    USE SIGNAL ;
    PORT
      LAYER M4 ;
        RECT  0 37.008 0.084 37.032 ;
    END
  END o[171]
  PIN o[172]
    DIRECTION OUTPUT ;
    USE SIGNAL ;
    PORT
      LAYER M4 ;
        RECT  0 37.104 0.084 37.128 ;
    END
  END o[172]
  PIN o[173]
    DIRECTION OUTPUT ;
    USE SIGNAL ;
    PORT
      LAYER M4 ;
        RECT  0 37.2 0.084 37.224 ;
    END
  END o[173]
  PIN o[174]
    DIRECTION OUTPUT ;
    USE SIGNAL ;
    PORT
      LAYER M4 ;
        RECT  0 37.296 0.084 37.32 ;
    END
  END o[174]
  PIN o[175]
    DIRECTION OUTPUT ;
    USE SIGNAL ;
    PORT
      LAYER M4 ;
        RECT  0 37.392 0.084 37.416 ;
    END
  END o[175]
  PIN o[176]
    DIRECTION OUTPUT ;
    USE SIGNAL ;
    PORT
      LAYER M4 ;
        RECT  0 37.488 0.084 37.512 ;
    END
  END o[176]
  PIN o[177]
    DIRECTION OUTPUT ;
    USE SIGNAL ;
    PORT
      LAYER M4 ;
        RECT  0 37.584 0.084 37.608 ;
    END
  END o[177]
  PIN o[178]
    DIRECTION OUTPUT ;
    USE SIGNAL ;
    PORT
      LAYER M4 ;
        RECT  0 37.68 0.084 37.704 ;
    END
  END o[178]
  PIN o[179]
    DIRECTION OUTPUT ;
    USE SIGNAL ;
    PORT
      LAYER M4 ;
        RECT  0 37.776 0.084 37.8 ;
    END
  END o[179]
  PIN o[17]
    DIRECTION OUTPUT ;
    USE SIGNAL ;
    PORT
      LAYER M4 ;
        RECT  0 18.384 0.084 18.408 ;
    END
  END o[17]
  PIN o[180]
    DIRECTION OUTPUT ;
    USE SIGNAL ;
    PORT
      LAYER M4 ;
        RECT  0 37.872 0.084 37.896 ;
    END
  END o[180]
  PIN o[181]
    DIRECTION OUTPUT ;
    USE SIGNAL ;
    PORT
      LAYER M4 ;
        RECT  0 37.968 0.084 37.992 ;
    END
  END o[181]
  PIN o[182]
    DIRECTION OUTPUT ;
    USE SIGNAL ;
    PORT
      LAYER M4 ;
        RECT  0 38.064 0.084 38.088 ;
    END
  END o[182]
  PIN o[183]
    DIRECTION OUTPUT ;
    USE SIGNAL ;
    PORT
      LAYER M4 ;
        RECT  0 38.16 0.084 38.184 ;
    END
  END o[183]
  PIN o[184]
    DIRECTION OUTPUT ;
    USE SIGNAL ;
    PORT
      LAYER M4 ;
        RECT  0 38.256 0.084 38.28 ;
    END
  END o[184]
  PIN o[185]
    DIRECTION OUTPUT ;
    USE SIGNAL ;
    PORT
      LAYER M4 ;
        RECT  0 38.352 0.084 38.376 ;
    END
  END o[185]
  PIN o[186]
    DIRECTION OUTPUT ;
    USE SIGNAL ;
    PORT
      LAYER M4 ;
        RECT  0 38.448 0.084 38.472 ;
    END
  END o[186]
  PIN o[187]
    DIRECTION OUTPUT ;
    USE SIGNAL ;
    PORT
      LAYER M4 ;
        RECT  0 38.544 0.084 38.568 ;
    END
  END o[187]
  PIN o[188]
    DIRECTION OUTPUT ;
    USE SIGNAL ;
    PORT
      LAYER M4 ;
        RECT  0 38.64 0.084 38.664 ;
    END
  END o[188]
  PIN o[189]
    DIRECTION OUTPUT ;
    USE SIGNAL ;
    PORT
      LAYER M4 ;
        RECT  0 38.736 0.084 38.76 ;
    END
  END o[189]
  PIN o[18]
    DIRECTION OUTPUT ;
    USE SIGNAL ;
    PORT
      LAYER M4 ;
        RECT  0 18.48 0.084 18.504 ;
    END
  END o[18]
  PIN o[190]
    DIRECTION OUTPUT ;
    USE SIGNAL ;
    PORT
      LAYER M4 ;
        RECT  0 38.832 0.084 38.856 ;
    END
  END o[190]
  PIN o[191]
    DIRECTION OUTPUT ;
    USE SIGNAL ;
    PORT
      LAYER M4 ;
        RECT  0 38.928 0.084 38.952 ;
    END
  END o[191]
  PIN o[192]
    DIRECTION OUTPUT ;
    USE SIGNAL ;
    PORT
      LAYER M4 ;
        RECT  0 39.024 0.084 39.048 ;
    END
  END o[192]
  PIN o[193]
    DIRECTION OUTPUT ;
    USE SIGNAL ;
    PORT
      LAYER M4 ;
        RECT  0 39.12 0.084 39.144 ;
    END
  END o[193]
  PIN o[194]
    DIRECTION OUTPUT ;
    USE SIGNAL ;
    PORT
      LAYER M4 ;
        RECT  0 39.216 0.084 39.24 ;
    END
  END o[194]
  PIN o[195]
    DIRECTION OUTPUT ;
    USE SIGNAL ;
    PORT
      LAYER M4 ;
        RECT  0 39.312 0.084 39.336 ;
    END
  END o[195]
  PIN o[196]
    DIRECTION OUTPUT ;
    USE SIGNAL ;
    PORT
      LAYER M4 ;
        RECT  0 39.408 0.084 39.432 ;
    END
  END o[196]
  PIN o[197]
    DIRECTION OUTPUT ;
    USE SIGNAL ;
    PORT
      LAYER M4 ;
        RECT  0 39.504 0.084 39.528 ;
    END
  END o[197]
  PIN o[198]
    DIRECTION OUTPUT ;
    USE SIGNAL ;
    PORT
      LAYER M4 ;
        RECT  0 39.6 0.084 39.624 ;
    END
  END o[198]
  PIN o[199]
    DIRECTION OUTPUT ;
    USE SIGNAL ;
    PORT
      LAYER M4 ;
        RECT  0 39.696 0.084 39.72 ;
    END
  END o[199]
  PIN o[19]
    DIRECTION OUTPUT ;
    USE SIGNAL ;
    PORT
      LAYER M4 ;
        RECT  0 18.576 0.084 18.6 ;
    END
  END o[19]
  PIN o[1]
    DIRECTION OUTPUT ;
    USE SIGNAL ;
    PORT
      LAYER M4 ;
        RECT  0 16.848 0.084 16.872 ;
    END
  END o[1]
  PIN o[200]
    DIRECTION OUTPUT ;
    USE SIGNAL ;
    PORT
      LAYER M4 ;
        RECT  0 39.792 0.084 39.816 ;
    END
  END o[200]
  PIN o[201]
    DIRECTION OUTPUT ;
    USE SIGNAL ;
    PORT
      LAYER M4 ;
        RECT  0 39.888 0.084 39.912 ;
    END
  END o[201]
  PIN o[202]
    DIRECTION OUTPUT ;
    USE SIGNAL ;
    PORT
      LAYER M4 ;
        RECT  0 39.984 0.084 40.008 ;
    END
  END o[202]
  PIN o[203]
    DIRECTION OUTPUT ;
    USE SIGNAL ;
    PORT
      LAYER M4 ;
        RECT  0 40.08 0.084 40.104 ;
    END
  END o[203]
  PIN o[204]
    DIRECTION OUTPUT ;
    USE SIGNAL ;
    PORT
      LAYER M4 ;
        RECT  0 40.176 0.084 40.2 ;
    END
  END o[204]
  PIN o[205]
    DIRECTION OUTPUT ;
    USE SIGNAL ;
    PORT
      LAYER M4 ;
        RECT  0 40.272 0.084 40.296 ;
    END
  END o[205]
  PIN o[206]
    DIRECTION OUTPUT ;
    USE SIGNAL ;
    PORT
      LAYER M4 ;
        RECT  0 40.368 0.084 40.392 ;
    END
  END o[206]
  PIN o[207]
    DIRECTION OUTPUT ;
    USE SIGNAL ;
    PORT
      LAYER M4 ;
        RECT  0 40.464 0.084 40.488 ;
    END
  END o[207]
  PIN o[208]
    DIRECTION OUTPUT ;
    USE SIGNAL ;
    PORT
      LAYER M4 ;
        RECT  0 40.56 0.084 40.584 ;
    END
  END o[208]
  PIN o[209]
    DIRECTION OUTPUT ;
    USE SIGNAL ;
    PORT
      LAYER M4 ;
        RECT  0 40.656 0.084 40.68 ;
    END
  END o[209]
  PIN o[20]
    DIRECTION OUTPUT ;
    USE SIGNAL ;
    PORT
      LAYER M4 ;
        RECT  0 18.672 0.084 18.696 ;
    END
  END o[20]
  PIN o[210]
    DIRECTION OUTPUT ;
    USE SIGNAL ;
    PORT
      LAYER M4 ;
        RECT  0 40.752 0.084 40.776 ;
    END
  END o[210]
  PIN o[211]
    DIRECTION OUTPUT ;
    USE SIGNAL ;
    PORT
      LAYER M4 ;
        RECT  0 40.848 0.084 40.872 ;
    END
  END o[211]
  PIN o[212]
    DIRECTION OUTPUT ;
    USE SIGNAL ;
    PORT
      LAYER M4 ;
        RECT  0 40.944 0.084 40.968 ;
    END
  END o[212]
  PIN o[213]
    DIRECTION OUTPUT ;
    USE SIGNAL ;
    PORT
      LAYER M4 ;
        RECT  0 41.04 0.084 41.064 ;
    END
  END o[213]
  PIN o[214]
    DIRECTION OUTPUT ;
    USE SIGNAL ;
    PORT
      LAYER M4 ;
        RECT  0 41.136 0.084 41.16 ;
    END
  END o[214]
  PIN o[215]
    DIRECTION OUTPUT ;
    USE SIGNAL ;
    PORT
      LAYER M4 ;
        RECT  0 41.232 0.084 41.256 ;
    END
  END o[215]
  PIN o[216]
    DIRECTION OUTPUT ;
    USE SIGNAL ;
    PORT
      LAYER M4 ;
        RECT  0 41.328 0.084 41.352 ;
    END
  END o[216]
  PIN o[217]
    DIRECTION OUTPUT ;
    USE SIGNAL ;
    PORT
      LAYER M4 ;
        RECT  0 41.424 0.084 41.448 ;
    END
  END o[217]
  PIN o[218]
    DIRECTION OUTPUT ;
    USE SIGNAL ;
    PORT
      LAYER M4 ;
        RECT  0 41.52 0.084 41.544 ;
    END
  END o[218]
  PIN o[219]
    DIRECTION OUTPUT ;
    USE SIGNAL ;
    PORT
      LAYER M4 ;
        RECT  0 41.616 0.084 41.64 ;
    END
  END o[219]
  PIN o[21]
    DIRECTION OUTPUT ;
    USE SIGNAL ;
    PORT
      LAYER M4 ;
        RECT  0 18.768 0.084 18.792 ;
    END
  END o[21]
  PIN o[220]
    DIRECTION OUTPUT ;
    USE SIGNAL ;
    PORT
      LAYER M4 ;
        RECT  0 41.712 0.084 41.736 ;
    END
  END o[220]
  PIN o[221]
    DIRECTION OUTPUT ;
    USE SIGNAL ;
    PORT
      LAYER M4 ;
        RECT  0 41.808 0.084 41.832 ;
    END
  END o[221]
  PIN o[222]
    DIRECTION OUTPUT ;
    USE SIGNAL ;
    PORT
      LAYER M4 ;
        RECT  0 41.904 0.084 41.928 ;
    END
  END o[222]
  PIN o[223]
    DIRECTION OUTPUT ;
    USE SIGNAL ;
    PORT
      LAYER M4 ;
        RECT  0 42 0.084 42.024 ;
    END
  END o[223]
  PIN o[224]
    DIRECTION OUTPUT ;
    USE SIGNAL ;
    PORT
      LAYER M4 ;
        RECT  0 42.096 0.084 42.12 ;
    END
  END o[224]
  PIN o[225]
    DIRECTION OUTPUT ;
    USE SIGNAL ;
    PORT
      LAYER M4 ;
        RECT  0 42.192 0.084 42.216 ;
    END
  END o[225]
  PIN o[226]
    DIRECTION OUTPUT ;
    USE SIGNAL ;
    PORT
      LAYER M4 ;
        RECT  0 42.288 0.084 42.312 ;
    END
  END o[226]
  PIN o[227]
    DIRECTION OUTPUT ;
    USE SIGNAL ;
    PORT
      LAYER M4 ;
        RECT  0 42.384 0.084 42.408 ;
    END
  END o[227]
  PIN o[228]
    DIRECTION OUTPUT ;
    USE SIGNAL ;
    PORT
      LAYER M4 ;
        RECT  0 42.48 0.084 42.504 ;
    END
  END o[228]
  PIN o[229]
    DIRECTION OUTPUT ;
    USE SIGNAL ;
    PORT
      LAYER M4 ;
        RECT  0 42.576 0.084 42.6 ;
    END
  END o[229]
  PIN o[22]
    DIRECTION OUTPUT ;
    USE SIGNAL ;
    PORT
      LAYER M4 ;
        RECT  0 18.864 0.084 18.888 ;
    END
  END o[22]
  PIN o[230]
    DIRECTION OUTPUT ;
    USE SIGNAL ;
    PORT
      LAYER M4 ;
        RECT  0 42.672 0.084 42.696 ;
    END
  END o[230]
  PIN o[231]
    DIRECTION OUTPUT ;
    USE SIGNAL ;
    PORT
      LAYER M4 ;
        RECT  0 42.768 0.084 42.792 ;
    END
  END o[231]
  PIN o[232]
    DIRECTION OUTPUT ;
    USE SIGNAL ;
    PORT
      LAYER M4 ;
        RECT  0 42.864 0.084 42.888 ;
    END
  END o[232]
  PIN o[233]
    DIRECTION OUTPUT ;
    USE SIGNAL ;
    PORT
      LAYER M4 ;
        RECT  0 42.96 0.084 42.984 ;
    END
  END o[233]
  PIN o[234]
    DIRECTION OUTPUT ;
    USE SIGNAL ;
    PORT
      LAYER M4 ;
        RECT  0 43.056 0.084 43.08 ;
    END
  END o[234]
  PIN o[235]
    DIRECTION OUTPUT ;
    USE SIGNAL ;
    PORT
      LAYER M4 ;
        RECT  0 43.152 0.084 43.176 ;
    END
  END o[235]
  PIN o[236]
    DIRECTION OUTPUT ;
    USE SIGNAL ;
    PORT
      LAYER M4 ;
        RECT  0 43.248 0.084 43.272 ;
    END
  END o[236]
  PIN o[237]
    DIRECTION OUTPUT ;
    USE SIGNAL ;
    PORT
      LAYER M4 ;
        RECT  0 43.344 0.084 43.368 ;
    END
  END o[237]
  PIN o[238]
    DIRECTION OUTPUT ;
    USE SIGNAL ;
    PORT
      LAYER M4 ;
        RECT  0 43.44 0.084 43.464 ;
    END
  END o[238]
  PIN o[239]
    DIRECTION OUTPUT ;
    USE SIGNAL ;
    PORT
      LAYER M4 ;
        RECT  0 43.536 0.084 43.56 ;
    END
  END o[239]
  PIN o[23]
    DIRECTION OUTPUT ;
    USE SIGNAL ;
    PORT
      LAYER M4 ;
        RECT  0 18.96 0.084 18.984 ;
    END
  END o[23]
  PIN o[240]
    DIRECTION OUTPUT ;
    USE SIGNAL ;
    PORT
      LAYER M4 ;
        RECT  0 43.632 0.084 43.656 ;
    END
  END o[240]
  PIN o[241]
    DIRECTION OUTPUT ;
    USE SIGNAL ;
    PORT
      LAYER M4 ;
        RECT  0 43.728 0.084 43.752 ;
    END
  END o[241]
  PIN o[242]
    DIRECTION OUTPUT ;
    USE SIGNAL ;
    PORT
      LAYER M4 ;
        RECT  0 43.824 0.084 43.848 ;
    END
  END o[242]
  PIN o[243]
    DIRECTION OUTPUT ;
    USE SIGNAL ;
    PORT
      LAYER M4 ;
        RECT  0 43.92 0.084 43.944 ;
    END
  END o[243]
  PIN o[244]
    DIRECTION OUTPUT ;
    USE SIGNAL ;
    PORT
      LAYER M4 ;
        RECT  0 44.016 0.084 44.04 ;
    END
  END o[244]
  PIN o[245]
    DIRECTION OUTPUT ;
    USE SIGNAL ;
    PORT
      LAYER M4 ;
        RECT  0 44.112 0.084 44.136 ;
    END
  END o[245]
  PIN o[246]
    DIRECTION OUTPUT ;
    USE SIGNAL ;
    PORT
      LAYER M4 ;
        RECT  0 44.208 0.084 44.232 ;
    END
  END o[246]
  PIN o[247]
    DIRECTION OUTPUT ;
    USE SIGNAL ;
    PORT
      LAYER M4 ;
        RECT  0 44.304 0.084 44.328 ;
    END
  END o[247]
  PIN o[248]
    DIRECTION OUTPUT ;
    USE SIGNAL ;
    PORT
      LAYER M4 ;
        RECT  0 44.4 0.084 44.424 ;
    END
  END o[248]
  PIN o[249]
    DIRECTION OUTPUT ;
    USE SIGNAL ;
    PORT
      LAYER M4 ;
        RECT  0 44.496 0.084 44.52 ;
    END
  END o[249]
  PIN o[24]
    DIRECTION OUTPUT ;
    USE SIGNAL ;
    PORT
      LAYER M4 ;
        RECT  0 19.056 0.084 19.08 ;
    END
  END o[24]
  PIN o[250]
    DIRECTION OUTPUT ;
    USE SIGNAL ;
    PORT
      LAYER M4 ;
        RECT  0 44.592 0.084 44.616 ;
    END
  END o[250]
  PIN o[251]
    DIRECTION OUTPUT ;
    USE SIGNAL ;
    PORT
      LAYER M4 ;
        RECT  0 44.688 0.084 44.712 ;
    END
  END o[251]
  PIN o[252]
    DIRECTION OUTPUT ;
    USE SIGNAL ;
    PORT
      LAYER M4 ;
        RECT  0 44.784 0.084 44.808 ;
    END
  END o[252]
  PIN o[253]
    DIRECTION OUTPUT ;
    USE SIGNAL ;
    PORT
      LAYER M4 ;
        RECT  0 44.88 0.084 44.904 ;
    END
  END o[253]
  PIN o[254]
    DIRECTION OUTPUT ;
    USE SIGNAL ;
    PORT
      LAYER M4 ;
        RECT  0 33.648 0.084 33.672 ;
    END
  END o[254]
  PIN o[255]
    DIRECTION OUTPUT ;
    USE SIGNAL ;
    PORT
      LAYER M4 ;
        RECT  0 33.744 0.084 33.768 ;
    END
  END o[255]
  PIN o[256]
    DIRECTION OUTPUT ;
    USE SIGNAL ;
    PORT
      LAYER M4 ;
        RECT  0 33.84 0.084 33.864 ;
    END
  END o[256]
  PIN o[257]
    DIRECTION OUTPUT ;
    USE SIGNAL ;
    PORT
      LAYER M4 ;
        RECT  0 33.936 0.084 33.96 ;
    END
  END o[257]
  PIN o[258]
    DIRECTION OUTPUT ;
    USE SIGNAL ;
    PORT
      LAYER M4 ;
        RECT  0 34.032 0.084 34.056 ;
    END
  END o[258]
  PIN o[259]
    DIRECTION OUTPUT ;
    USE SIGNAL ;
    PORT
      LAYER M4 ;
        RECT  0 34.128 0.084 34.152 ;
    END
  END o[259]
  PIN o[25]
    DIRECTION OUTPUT ;
    USE SIGNAL ;
    PORT
      LAYER M4 ;
        RECT  0 19.152 0.084 19.176 ;
    END
  END o[25]
  PIN o[260]
    DIRECTION OUTPUT ;
    USE SIGNAL ;
    PORT
      LAYER M4 ;
        RECT  0 34.224 0.084 34.248 ;
    END
  END o[260]
  PIN o[261]
    DIRECTION OUTPUT ;
    USE SIGNAL ;
    PORT
      LAYER M4 ;
        RECT  0 34.32 0.084 34.344 ;
    END
  END o[261]
  PIN o[262]
    DIRECTION OUTPUT ;
    USE SIGNAL ;
    PORT
      LAYER M4 ;
        RECT  0 34.416 0.084 34.44 ;
    END
  END o[262]
  PIN o[263]
    DIRECTION OUTPUT ;
    USE SIGNAL ;
    PORT
      LAYER M4 ;
        RECT  0 34.512 0.084 34.536 ;
    END
  END o[263]
  PIN o[264]
    DIRECTION OUTPUT ;
    USE SIGNAL ;
    PORT
      LAYER M4 ;
        RECT  0 34.608 0.084 34.632 ;
    END
  END o[264]
  PIN o[265]
    DIRECTION OUTPUT ;
    USE SIGNAL ;
    PORT
      LAYER M4 ;
        RECT  0 34.704 0.084 34.728 ;
    END
  END o[265]
  PIN o[266]
    DIRECTION OUTPUT ;
    USE SIGNAL ;
    PORT
      LAYER M4 ;
        RECT  0 34.8 0.084 34.824 ;
    END
  END o[266]
  PIN o[267]
    DIRECTION OUTPUT ;
    USE SIGNAL ;
    PORT
      LAYER M4 ;
        RECT  0 34.896 0.084 34.92 ;
    END
  END o[267]
  PIN o[268]
    DIRECTION OUTPUT ;
    USE SIGNAL ;
    PORT
      LAYER M4 ;
        RECT  0 34.992 0.084 35.016 ;
    END
  END o[268]
  PIN o[269]
    DIRECTION OUTPUT ;
    USE SIGNAL ;
    PORT
      LAYER M4 ;
        RECT  0 35.088 0.084 35.112 ;
    END
  END o[269]
  PIN o[26]
    DIRECTION OUTPUT ;
    USE SIGNAL ;
    PORT
      LAYER M4 ;
        RECT  0 19.248 0.084 19.272 ;
    END
  END o[26]
  PIN o[270]
    DIRECTION OUTPUT ;
    USE SIGNAL ;
    PORT
      LAYER M4 ;
        RECT  0 35.184 0.084 35.208 ;
    END
  END o[270]
  PIN o[271]
    DIRECTION OUTPUT ;
    USE SIGNAL ;
    PORT
      LAYER M4 ;
        RECT  0 35.28 0.084 35.304 ;
    END
  END o[271]
  PIN o[272]
    DIRECTION OUTPUT ;
    USE SIGNAL ;
    PORT
      LAYER M4 ;
        RECT  0 35.376 0.084 35.4 ;
    END
  END o[272]
  PIN o[273]
    DIRECTION OUTPUT ;
    USE SIGNAL ;
    PORT
      LAYER M4 ;
        RECT  0 35.472 0.084 35.496 ;
    END
  END o[273]
  PIN o[274]
    DIRECTION OUTPUT ;
    USE SIGNAL ;
    PORT
      LAYER M4 ;
        RECT  0 35.568 0.084 35.592 ;
    END
  END o[274]
  PIN o[275]
    DIRECTION OUTPUT ;
    USE SIGNAL ;
    PORT
      LAYER M4 ;
        RECT  0 35.664 0.084 35.688 ;
    END
  END o[275]
  PIN o[27]
    DIRECTION OUTPUT ;
    USE SIGNAL ;
    PORT
      LAYER M4 ;
        RECT  0 19.344 0.084 19.368 ;
    END
  END o[27]
  PIN o[28]
    DIRECTION OUTPUT ;
    USE SIGNAL ;
    PORT
      LAYER M4 ;
        RECT  0 19.44 0.084 19.464 ;
    END
  END o[28]
  PIN o[29]
    DIRECTION OUTPUT ;
    USE SIGNAL ;
    PORT
      LAYER M4 ;
        RECT  0 19.536 0.084 19.56 ;
    END
  END o[29]
  PIN o[2]
    DIRECTION OUTPUT ;
    USE SIGNAL ;
    PORT
      LAYER M4 ;
        RECT  0 16.944 0.084 16.968 ;
    END
  END o[2]
  PIN o[30]
    DIRECTION OUTPUT ;
    USE SIGNAL ;
    PORT
      LAYER M4 ;
        RECT  0 3.504 0.084 3.528 ;
    END
  END o[30]
  PIN o[31]
    DIRECTION OUTPUT ;
    USE SIGNAL ;
    PORT
      LAYER M4 ;
        RECT  0 3.6 0.084 3.624 ;
    END
  END o[31]
  PIN o[32]
    DIRECTION OUTPUT ;
    USE SIGNAL ;
    PORT
      LAYER M4 ;
        RECT  0 3.696 0.084 3.72 ;
    END
  END o[32]
  PIN o[33]
    DIRECTION OUTPUT ;
    USE SIGNAL ;
    PORT
      LAYER M4 ;
        RECT  0 3.792 0.084 3.816 ;
    END
  END o[33]
  PIN o[34]
    DIRECTION OUTPUT ;
    USE SIGNAL ;
    PORT
      LAYER M4 ;
        RECT  0 3.888 0.084 3.912 ;
    END
  END o[34]
  PIN o[35]
    DIRECTION OUTPUT ;
    USE SIGNAL ;
    PORT
      LAYER M4 ;
        RECT  0 3.984 0.084 4.008 ;
    END
  END o[35]
  PIN o[36]
    DIRECTION OUTPUT ;
    USE SIGNAL ;
    PORT
      LAYER M4 ;
        RECT  0 4.08 0.084 4.104 ;
    END
  END o[36]
  PIN o[37]
    DIRECTION OUTPUT ;
    USE SIGNAL ;
    PORT
      LAYER M4 ;
        RECT  0 4.176 0.084 4.2 ;
    END
  END o[37]
  PIN o[38]
    DIRECTION OUTPUT ;
    USE SIGNAL ;
    PORT
      LAYER M4 ;
        RECT  0 4.272 0.084 4.296 ;
    END
  END o[38]
  PIN o[39]
    DIRECTION OUTPUT ;
    USE SIGNAL ;
    PORT
      LAYER M4 ;
        RECT  0 4.368 0.084 4.392 ;
    END
  END o[39]
  PIN o[3]
    DIRECTION OUTPUT ;
    USE SIGNAL ;
    PORT
      LAYER M4 ;
        RECT  0 17.04 0.084 17.064 ;
    END
  END o[3]
  PIN o[40]
    DIRECTION OUTPUT ;
    USE SIGNAL ;
    PORT
      LAYER M4 ;
        RECT  0 4.464 0.084 4.488 ;
    END
  END o[40]
  PIN o[41]
    DIRECTION OUTPUT ;
    USE SIGNAL ;
    PORT
      LAYER M4 ;
        RECT  0 4.56 0.084 4.584 ;
    END
  END o[41]
  PIN o[42]
    DIRECTION OUTPUT ;
    USE SIGNAL ;
    PORT
      LAYER M4 ;
        RECT  0 4.656 0.084 4.68 ;
    END
  END o[42]
  PIN o[43]
    DIRECTION OUTPUT ;
    USE SIGNAL ;
    PORT
      LAYER M4 ;
        RECT  0 4.752 0.084 4.776 ;
    END
  END o[43]
  PIN o[44]
    DIRECTION OUTPUT ;
    USE SIGNAL ;
    PORT
      LAYER M4 ;
        RECT  0 4.848 0.084 4.872 ;
    END
  END o[44]
  PIN o[45]
    DIRECTION OUTPUT ;
    USE SIGNAL ;
    PORT
      LAYER M4 ;
        RECT  0 4.944 0.084 4.968 ;
    END
  END o[45]
  PIN o[46]
    DIRECTION OUTPUT ;
    USE SIGNAL ;
    PORT
      LAYER M4 ;
        RECT  0 5.04 0.084 5.064 ;
    END
  END o[46]
  PIN o[47]
    DIRECTION OUTPUT ;
    USE SIGNAL ;
    PORT
      LAYER M4 ;
        RECT  0 5.136 0.084 5.16 ;
    END
  END o[47]
  PIN o[48]
    DIRECTION OUTPUT ;
    USE SIGNAL ;
    PORT
      LAYER M4 ;
        RECT  0 5.232 0.084 5.256 ;
    END
  END o[48]
  PIN o[49]
    DIRECTION OUTPUT ;
    USE SIGNAL ;
    PORT
      LAYER M4 ;
        RECT  0 5.328 0.084 5.352 ;
    END
  END o[49]
  PIN o[4]
    DIRECTION OUTPUT ;
    USE SIGNAL ;
    PORT
      LAYER M4 ;
        RECT  0 17.136 0.084 17.16 ;
    END
  END o[4]
  PIN o[50]
    DIRECTION OUTPUT ;
    USE SIGNAL ;
    PORT
      LAYER M4 ;
        RECT  0 5.424 0.084 5.448 ;
    END
  END o[50]
  PIN o[51]
    DIRECTION OUTPUT ;
    USE SIGNAL ;
    PORT
      LAYER M4 ;
        RECT  0 5.52 0.084 5.544 ;
    END
  END o[51]
  PIN o[52]
    DIRECTION OUTPUT ;
    USE SIGNAL ;
    PORT
      LAYER M4 ;
        RECT  0 5.616 0.084 5.64 ;
    END
  END o[52]
  PIN o[53]
    DIRECTION OUTPUT ;
    USE SIGNAL ;
    PORT
      LAYER M4 ;
        RECT  0 5.712 0.084 5.736 ;
    END
  END o[53]
  PIN o[54]
    DIRECTION OUTPUT ;
    USE SIGNAL ;
    PORT
      LAYER M4 ;
        RECT  0 5.808 0.084 5.832 ;
    END
  END o[54]
  PIN o[55]
    DIRECTION OUTPUT ;
    USE SIGNAL ;
    PORT
      LAYER M4 ;
        RECT  0 5.904 0.084 5.928 ;
    END
  END o[55]
  PIN o[56]
    DIRECTION OUTPUT ;
    USE SIGNAL ;
    PORT
      LAYER M4 ;
        RECT  0 6 0.084 6.024 ;
    END
  END o[56]
  PIN o[57]
    DIRECTION OUTPUT ;
    USE SIGNAL ;
    PORT
      LAYER M4 ;
        RECT  0 6.096 0.084 6.12 ;
    END
  END o[57]
  PIN o[58]
    DIRECTION OUTPUT ;
    USE SIGNAL ;
    PORT
      LAYER M4 ;
        RECT  0 6.192 0.084 6.216 ;
    END
  END o[58]
  PIN o[59]
    DIRECTION OUTPUT ;
    USE SIGNAL ;
    PORT
      LAYER M4 ;
        RECT  0 6.288 0.084 6.312 ;
    END
  END o[59]
  PIN o[5]
    DIRECTION OUTPUT ;
    USE SIGNAL ;
    PORT
      LAYER M4 ;
        RECT  0 17.232 0.084 17.256 ;
    END
  END o[5]
  PIN o[60]
    DIRECTION OUTPUT ;
    USE SIGNAL ;
    PORT
      LAYER M4 ;
        RECT  0 6.384 0.084 6.408 ;
    END
  END o[60]
  PIN o[61]
    DIRECTION OUTPUT ;
    USE SIGNAL ;
    PORT
      LAYER M4 ;
        RECT  0 6.48 0.084 6.504 ;
    END
  END o[61]
  PIN o[62]
    DIRECTION OUTPUT ;
    USE SIGNAL ;
    PORT
      LAYER M4 ;
        RECT  0 19.632 0.084 19.656 ;
    END
  END o[62]
  PIN o[63]
    DIRECTION OUTPUT ;
    USE SIGNAL ;
    PORT
      LAYER M4 ;
        RECT  0 19.728 0.084 19.752 ;
    END
  END o[63]
  PIN o[64]
    DIRECTION OUTPUT ;
    USE SIGNAL ;
    PORT
      LAYER M4 ;
        RECT  0 19.824 0.084 19.848 ;
    END
  END o[64]
  PIN o[65]
    DIRECTION OUTPUT ;
    USE SIGNAL ;
    PORT
      LAYER M4 ;
        RECT  0 19.92 0.084 19.944 ;
    END
  END o[65]
  PIN o[66]
    DIRECTION OUTPUT ;
    USE SIGNAL ;
    PORT
      LAYER M4 ;
        RECT  0 20.016 0.084 20.04 ;
    END
  END o[66]
  PIN o[67]
    DIRECTION OUTPUT ;
    USE SIGNAL ;
    PORT
      LAYER M4 ;
        RECT  0 20.112 0.084 20.136 ;
    END
  END o[67]
  PIN o[68]
    DIRECTION OUTPUT ;
    USE SIGNAL ;
    PORT
      LAYER M4 ;
        RECT  0 20.208 0.084 20.232 ;
    END
  END o[68]
  PIN o[69]
    DIRECTION OUTPUT ;
    USE SIGNAL ;
    PORT
      LAYER M4 ;
        RECT  0 20.304 0.084 20.328 ;
    END
  END o[69]
  PIN o[6]
    DIRECTION OUTPUT ;
    USE SIGNAL ;
    PORT
      LAYER M4 ;
        RECT  0 17.328 0.084 17.352 ;
    END
  END o[6]
  PIN o[70]
    DIRECTION OUTPUT ;
    USE SIGNAL ;
    PORT
      LAYER M4 ;
        RECT  0 20.4 0.084 20.424 ;
    END
  END o[70]
  PIN o[71]
    DIRECTION OUTPUT ;
    USE SIGNAL ;
    PORT
      LAYER M4 ;
        RECT  0 20.496 0.084 20.52 ;
    END
  END o[71]
  PIN o[72]
    DIRECTION OUTPUT ;
    USE SIGNAL ;
    PORT
      LAYER M4 ;
        RECT  0 20.592 0.084 20.616 ;
    END
  END o[72]
  PIN o[73]
    DIRECTION OUTPUT ;
    USE SIGNAL ;
    PORT
      LAYER M4 ;
        RECT  0 20.688 0.084 20.712 ;
    END
  END o[73]
  PIN o[74]
    DIRECTION OUTPUT ;
    USE SIGNAL ;
    PORT
      LAYER M4 ;
        RECT  0 20.784 0.084 20.808 ;
    END
  END o[74]
  PIN o[75]
    DIRECTION OUTPUT ;
    USE SIGNAL ;
    PORT
      LAYER M4 ;
        RECT  0 20.88 0.084 20.904 ;
    END
  END o[75]
  PIN o[76]
    DIRECTION OUTPUT ;
    USE SIGNAL ;
    PORT
      LAYER M4 ;
        RECT  0 20.976 0.084 21 ;
    END
  END o[76]
  PIN o[77]
    DIRECTION OUTPUT ;
    USE SIGNAL ;
    PORT
      LAYER M4 ;
        RECT  0 21.072 0.084 21.096 ;
    END
  END o[77]
  PIN o[78]
    DIRECTION OUTPUT ;
    USE SIGNAL ;
    PORT
      LAYER M4 ;
        RECT  0 21.168 0.084 21.192 ;
    END
  END o[78]
  PIN o[79]
    DIRECTION OUTPUT ;
    USE SIGNAL ;
    PORT
      LAYER M4 ;
        RECT  0 21.264 0.084 21.288 ;
    END
  END o[79]
  PIN o[7]
    DIRECTION OUTPUT ;
    USE SIGNAL ;
    PORT
      LAYER M4 ;
        RECT  0 17.424 0.084 17.448 ;
    END
  END o[7]
  PIN o[80]
    DIRECTION OUTPUT ;
    USE SIGNAL ;
    PORT
      LAYER M4 ;
        RECT  0 21.36 0.084 21.384 ;
    END
  END o[80]
  PIN o[81]
    DIRECTION OUTPUT ;
    USE SIGNAL ;
    PORT
      LAYER M4 ;
        RECT  0 21.456 0.084 21.48 ;
    END
  END o[81]
  PIN o[82]
    DIRECTION OUTPUT ;
    USE SIGNAL ;
    PORT
      LAYER M4 ;
        RECT  0 21.552 0.084 21.576 ;
    END
  END o[82]
  PIN o[83]
    DIRECTION OUTPUT ;
    USE SIGNAL ;
    PORT
      LAYER M4 ;
        RECT  0 21.648 0.084 21.672 ;
    END
  END o[83]
  PIN o[84]
    DIRECTION OUTPUT ;
    USE SIGNAL ;
    PORT
      LAYER M4 ;
        RECT  0 21.744 0.084 21.768 ;
    END
  END o[84]
  PIN o[85]
    DIRECTION OUTPUT ;
    USE SIGNAL ;
    PORT
      LAYER M4 ;
        RECT  0 21.84 0.084 21.864 ;
    END
  END o[85]
  PIN o[86]
    DIRECTION OUTPUT ;
    USE SIGNAL ;
    PORT
      LAYER M4 ;
        RECT  0 21.936 0.084 21.96 ;
    END
  END o[86]
  PIN o[87]
    DIRECTION OUTPUT ;
    USE SIGNAL ;
    PORT
      LAYER M4 ;
        RECT  0 22.032 0.084 22.056 ;
    END
  END o[87]
  PIN o[88]
    DIRECTION OUTPUT ;
    USE SIGNAL ;
    PORT
      LAYER M4 ;
        RECT  0 22.128 0.084 22.152 ;
    END
  END o[88]
  PIN o[89]
    DIRECTION OUTPUT ;
    USE SIGNAL ;
    PORT
      LAYER M4 ;
        RECT  0 22.224 0.084 22.248 ;
    END
  END o[89]
  PIN o[8]
    DIRECTION OUTPUT ;
    USE SIGNAL ;
    PORT
      LAYER M4 ;
        RECT  0 17.52 0.084 17.544 ;
    END
  END o[8]
  PIN o[90]
    DIRECTION OUTPUT ;
    USE SIGNAL ;
    PORT
      LAYER M4 ;
        RECT  0 22.32 0.084 22.344 ;
    END
  END o[90]
  PIN o[91]
    DIRECTION OUTPUT ;
    USE SIGNAL ;
    PORT
      LAYER M4 ;
        RECT  0 22.416 0.084 22.44 ;
    END
  END o[91]
  PIN o[92]
    DIRECTION OUTPUT ;
    USE SIGNAL ;
    PORT
      LAYER M4 ;
        RECT  0 22.512 0.084 22.536 ;
    END
  END o[92]
  PIN o[93]
    DIRECTION OUTPUT ;
    USE SIGNAL ;
    PORT
      LAYER M4 ;
        RECT  0 22.608 0.084 22.632 ;
    END
  END o[93]
  PIN o[94]
    DIRECTION OUTPUT ;
    USE SIGNAL ;
    PORT
      LAYER M4 ;
        RECT  0 6.576 0.084 6.6 ;
    END
  END o[94]
  PIN o[95]
    DIRECTION OUTPUT ;
    USE SIGNAL ;
    PORT
      LAYER M4 ;
        RECT  0 6.672 0.084 6.696 ;
    END
  END o[95]
  PIN o[96]
    DIRECTION OUTPUT ;
    USE SIGNAL ;
    PORT
      LAYER M4 ;
        RECT  0 6.768 0.084 6.792 ;
    END
  END o[96]
  PIN o[97]
    DIRECTION OUTPUT ;
    USE SIGNAL ;
    PORT
      LAYER M4 ;
        RECT  0 6.864 0.084 6.888 ;
    END
  END o[97]
  PIN o[98]
    DIRECTION OUTPUT ;
    USE SIGNAL ;
    PORT
      LAYER M4 ;
        RECT  0 6.96 0.084 6.984 ;
    END
  END o[98]
  PIN o[99]
    DIRECTION OUTPUT ;
    USE SIGNAL ;
    PORT
      LAYER M4 ;
        RECT  0 7.056 0.084 7.08 ;
    END
  END o[99]
  PIN o[9]
    DIRECTION OUTPUT ;
    USE SIGNAL ;
    PORT
      LAYER M4 ;
        RECT  0 17.616 0.084 17.64 ;
    END
  END o[9]
  PIN rs
    DIRECTION INPUT ;
    USE SIGNAL ;
    PORT
      LAYER M5 ;
        RECT  11.376 51.756 11.4 51.84 ;
    END
  END rs
  PIN VDD
    DIRECTION INOUT ;
    USE POWER ;
    PORT
      LAYER M5 ;
        RECT  32.292 2.151 32.412 49.689 ;
        RECT  29.592 2.151 29.712 49.689 ;
        RECT  26.892 2.151 27.012 49.689 ;
        RECT  24.192 2.151 24.312 49.689 ;
        RECT  21.492 2.151 21.612 49.689 ;
        RECT  18.792 2.151 18.912 49.689 ;
        RECT  16.092 2.151 16.212 49.689 ;
        RECT  13.392 2.151 13.512 49.689 ;
        RECT  10.692 2.151 10.812 49.689 ;
        RECT  7.992 2.151 8.112 49.689 ;
        RECT  5.292 2.151 5.412 49.689 ;
        RECT  2.592 2.151 2.712 49.689 ;
    END
  END VDD
  PIN VSS
    DIRECTION INOUT ;
    USE GROUND ;
    PORT
      LAYER M5 ;
        RECT  32.1 2.137 32.22 49.703 ;
        RECT  29.4 2.137 29.52 49.703 ;
        RECT  26.7 2.137 26.82 49.703 ;
        RECT  24 2.137 24.12 49.703 ;
        RECT  21.3 2.137 21.42 49.703 ;
        RECT  18.6 2.137 18.72 49.703 ;
        RECT  15.9 2.137 16.02 49.703 ;
        RECT  13.2 2.137 13.32 49.703 ;
        RECT  10.5 2.137 10.62 49.703 ;
        RECT  7.8 2.137 7.92 49.703 ;
        RECT  5.1 2.137 5.22 49.703 ;
        RECT  2.4 2.137 2.52 49.703 ;
    END
  END VSS
  # OT_OBS_CLOSED layer=M5 d_um=1.536 added=312
  OBS
    LAYER RVTN ;
     RECT  2.16 2.16 34.56 2.295 ;
     RECT  2.16 2.565 34.56 2.835 ;
     RECT  2.16 3.105 34.56 3.375 ;
     RECT  2.16 3.645 34.56 3.915 ;
     RECT  2.16 4.185 34.56 4.455 ;
     RECT  2.16 4.725 34.56 4.995 ;
     RECT  2.16 5.265 34.56 5.535 ;
     RECT  2.16 5.805 34.56 6.075 ;
     RECT  2.16 6.345 34.56 6.615 ;
     RECT  2.16 6.885 34.56 7.155 ;
     RECT  2.16 7.425 34.56 7.695 ;
     RECT  2.16 7.965 34.56 8.235 ;
     RECT  2.16 8.505 34.56 8.775 ;
     RECT  2.16 9.045 34.56 9.315 ;
     RECT  2.16 9.585 34.56 9.855 ;
     RECT  2.16 10.125 34.56 10.395 ;
     RECT  2.16 10.665 34.56 10.935 ;
     RECT  2.16 11.205 34.56 11.475 ;
     RECT  2.16 11.745 34.56 12.015 ;
     RECT  2.16 12.285 34.56 12.555 ;
     RECT  2.16 12.825 34.56 13.095 ;
     RECT  2.16 13.365 34.56 13.635 ;
     RECT  2.16 13.905 34.56 14.175 ;
     RECT  2.16 14.445 34.56 14.715 ;
     RECT  2.16 14.985 34.56 15.255 ;
     RECT  2.16 15.525 34.56 15.795 ;
     RECT  2.16 16.065 34.56 16.335 ;
     RECT  2.16 16.605 34.56 16.875 ;
     RECT  2.16 17.145 34.56 17.415 ;
     RECT  2.16 17.685 34.56 17.955 ;
     RECT  2.16 18.225 34.56 18.495 ;
     RECT  2.16 18.765 34.56 19.035 ;
     RECT  2.16 19.305 34.56 19.575 ;
     RECT  2.16 19.845 34.56 20.115 ;
     RECT  2.16 20.385 34.56 20.655 ;
     RECT  2.16 20.925 34.56 21.195 ;
     RECT  2.16 21.465 34.56 21.735 ;
     RECT  2.16 22.005 34.56 22.275 ;
     RECT  2.16 22.545 34.56 22.815 ;
     RECT  2.16 23.085 34.56 23.355 ;
     RECT  2.16 23.625 34.56 23.895 ;
     RECT  2.16 24.165 34.56 24.435 ;
     RECT  2.16 24.705 34.56 24.975 ;
     RECT  2.16 25.245 34.56 25.515 ;
     RECT  2.16 25.785 34.56 26.055 ;
     RECT  2.16 26.325 34.56 26.595 ;
     RECT  2.16 26.865 34.56 27.135 ;
     RECT  2.16 27.405 34.56 27.675 ;
     RECT  2.16 27.945 34.56 28.215 ;
     RECT  2.16 28.485 34.56 28.755 ;
     RECT  2.16 29.025 34.56 29.295 ;
     RECT  2.16 29.565 34.56 29.835 ;
     RECT  2.16 30.105 34.56 30.375 ;
     RECT  2.16 30.645 34.56 30.915 ;
     RECT  2.16 31.185 34.56 31.455 ;
     RECT  2.16 31.725 34.56 31.995 ;
     RECT  2.16 32.265 34.56 32.535 ;
     RECT  2.16 32.805 34.56 33.075 ;
     RECT  2.16 33.345 34.56 33.615 ;
     RECT  2.16 33.885 34.56 34.155 ;
     RECT  2.16 34.425 34.56 34.695 ;
     RECT  2.16 34.965 34.56 35.235 ;
     RECT  2.16 35.505 34.56 35.775 ;
     RECT  2.16 36.045 34.56 36.315 ;
     RECT  2.16 36.585 34.56 36.855 ;
     RECT  2.16 37.125 34.56 37.395 ;
     RECT  2.16 37.665 34.56 37.935 ;
     RECT  2.16 38.205 34.56 38.475 ;
     RECT  2.16 38.745 34.56 39.015 ;
     RECT  2.16 39.285 34.56 39.555 ;
     RECT  2.16 39.825 34.56 40.095 ;
     RECT  2.16 40.365 34.56 40.635 ;
     RECT  2.16 40.905 34.56 41.175 ;
     RECT  2.16 41.445 34.56 41.715 ;
     RECT  2.16 41.985 34.56 42.255 ;
     RECT  2.16 42.525 34.56 42.795 ;
     RECT  2.16 43.065 34.56 43.335 ;
     RECT  2.16 43.605 34.56 43.875 ;
     RECT  2.16 44.145 34.56 44.415 ;
     RECT  2.16 44.685 34.56 44.955 ;
     RECT  2.16 45.225 34.56 45.495 ;
     RECT  2.16 45.765 34.56 46.035 ;
     RECT  2.16 46.305 34.56 46.575 ;
     RECT  2.16 46.845 34.56 47.115 ;
     RECT  2.16 47.385 34.56 47.655 ;
     RECT  2.16 47.925 34.56 48.195 ;
     RECT  2.16 48.465 34.56 48.735 ;
     RECT  2.16 49.005 34.56 49.275 ;
     RECT  2.16 49.545 34.56 49.68 ;
    LAYER RVTP ;
     RECT  2.16 2.295 34.56 2.565 ;
     RECT  2.16 2.835 34.56 3.105 ;
     RECT  2.16 3.375 34.56 3.645 ;
     RECT  2.16 3.915 34.56 4.185 ;
     RECT  2.16 4.455 34.56 4.725 ;
     RECT  2.16 4.995 34.56 5.265 ;
     RECT  2.16 5.535 34.56 5.805 ;
     RECT  2.16 6.075 34.56 6.345 ;
     RECT  2.16 6.615 34.56 6.885 ;
     RECT  2.16 7.155 34.56 7.425 ;
     RECT  2.16 7.695 34.56 7.965 ;
     RECT  2.16 8.235 34.56 8.505 ;
     RECT  2.16 8.775 34.56 9.045 ;
     RECT  2.16 9.315 34.56 9.585 ;
     RECT  2.16 9.855 34.56 10.125 ;
     RECT  2.16 10.395 34.56 10.665 ;
     RECT  2.16 10.935 34.56 11.205 ;
     RECT  2.16 11.475 34.56 11.745 ;
     RECT  2.16 12.015 34.56 12.285 ;
     RECT  2.16 12.555 34.56 12.825 ;
     RECT  2.16 13.095 34.56 13.365 ;
     RECT  2.16 13.635 34.56 13.905 ;
     RECT  2.16 14.175 34.56 14.445 ;
     RECT  2.16 14.715 34.56 14.985 ;
     RECT  2.16 15.255 34.56 15.525 ;
     RECT  2.16 15.795 34.56 16.065 ;
     RECT  2.16 16.335 34.56 16.605 ;
     RECT  2.16 16.875 34.56 17.145 ;
     RECT  2.16 17.415 34.56 17.685 ;
     RECT  2.16 17.955 34.56 18.225 ;
     RECT  2.16 18.495 34.56 18.765 ;
     RECT  2.16 19.035 34.56 19.305 ;
     RECT  2.16 19.575 34.56 19.845 ;
     RECT  2.16 20.115 34.56 20.385 ;
     RECT  2.16 20.655 34.56 20.925 ;
     RECT  2.16 21.195 34.56 21.465 ;
     RECT  2.16 21.735 34.56 22.005 ;
     RECT  2.16 22.275 34.56 22.545 ;
     RECT  2.16 22.815 34.56 23.085 ;
     RECT  2.16 23.355 34.56 23.625 ;
     RECT  2.16 23.895 34.56 24.165 ;
     RECT  2.16 24.435 34.56 24.705 ;
     RECT  2.16 24.975 34.56 25.245 ;
     RECT  2.16 25.515 34.56 25.785 ;
     RECT  2.16 26.055 34.56 26.325 ;
     RECT  2.16 26.595 34.56 26.865 ;
     RECT  2.16 27.135 34.56 27.405 ;
     RECT  2.16 27.675 34.56 27.945 ;
     RECT  2.16 28.215 34.56 28.485 ;
     RECT  2.16 28.755 34.56 29.025 ;
     RECT  2.16 29.295 34.56 29.565 ;
     RECT  2.16 29.835 34.56 30.105 ;
     RECT  2.16 30.375 34.56 30.645 ;
     RECT  2.16 30.915 34.56 31.185 ;
     RECT  2.16 31.455 34.56 31.725 ;
     RECT  2.16 31.995 34.56 32.265 ;
     RECT  2.16 32.535 34.56 32.805 ;
     RECT  2.16 33.075 34.56 33.345 ;
     RECT  2.16 33.615 34.56 33.885 ;
     RECT  2.16 34.155 34.56 34.425 ;
     RECT  2.16 34.695 34.56 34.965 ;
     RECT  2.16 35.235 34.56 35.505 ;
     RECT  2.16 35.775 34.56 36.045 ;
     RECT  2.16 36.315 34.56 36.585 ;
     RECT  2.16 36.855 34.56 37.125 ;
     RECT  2.16 37.395 34.56 37.665 ;
     RECT  2.16 37.935 34.56 38.205 ;
     RECT  2.16 38.475 34.56 38.745 ;
     RECT  2.16 39.015 34.56 39.285 ;
     RECT  2.16 39.555 34.56 39.825 ;
     RECT  2.16 40.095 34.56 40.365 ;
     RECT  2.16 40.635 34.56 40.905 ;
     RECT  2.16 41.175 34.56 41.445 ;
     RECT  2.16 41.715 34.56 41.985 ;
     RECT  2.16 42.255 34.56 42.525 ;
     RECT  2.16 42.795 34.56 43.065 ;
     RECT  2.16 43.335 34.56 43.605 ;
     RECT  2.16 43.875 34.56 44.145 ;
     RECT  2.16 44.415 34.56 44.685 ;
     RECT  2.16 44.955 34.56 45.225 ;
     RECT  2.16 45.495 34.56 45.765 ;
     RECT  2.16 46.035 34.56 46.305 ;
     RECT  2.16 46.575 34.56 46.845 ;
     RECT  2.16 47.115 34.56 47.385 ;
     RECT  2.16 47.655 34.56 47.925 ;
     RECT  2.16 48.195 34.56 48.465 ;
     RECT  2.16 48.735 34.56 49.005 ;
     RECT  2.16 49.275 34.56 49.545 ;
    LAYER M1 ;
     RECT  2.16 2.151 34.56 49.689 ;
    LAYER M2 ;
     RECT  0.031 34.164 0.103 34.794 ;
     RECT  0.103 33.516 0.131 34.794 ;
     RECT  0.103 16.686 0.139 16.704 ;
     RECT  0.103 18.774 0.139 18.792 ;
     RECT  0.103 38.178 0.139 38.196 ;
     RECT  0.103 3.276 0.175 4.554 ;
     RECT  0.103 5.706 0.175 5.724 ;
     RECT  0.103 21.636 0.175 23.274 ;
     RECT  0.139 38.178 0.175 38.664 ;
     RECT  0.103 40.068 0.203 40.392 ;
     RECT  0.139 18.738 0.211 18.792 ;
     RECT  0.175 3.276 0.275 5.724 ;
     RECT  0.103 9.36 0.347 9.378 ;
     RECT  0.103 25.29 0.347 25.308 ;
     RECT  0.103 43.542 0.383 43.56 ;
     RECT  0.175 21.276 0.419 23.274 ;
     RECT  0.103 36.756 0.463 36.774 ;
     RECT  0.275 5.436 0.499 5.724 ;
     RECT  0.419 21.276 0.499 23.148 ;
     RECT  0.131 33.516 0.499 34.182 ;
     RECT  0.463 36.756 0.499 36.81 ;
     RECT  0.275 3.276 0.535 4.554 ;
     RECT  0.499 5.436 0.535 5.994 ;
     RECT  0.211 18.666 0.535 18.792 ;
     RECT  0.499 36.756 0.535 36.954 ;
     RECT  0.175 38.106 0.535 38.664 ;
     RECT  0.103 41.886 0.535 41.904 ;
     RECT  0.103 42.696 0.535 42.714 ;
     RECT  0.535 36.756 1.211 37.044 ;
     RECT  1.183 35.28 1.219 35.298 ;
     RECT  1.219 35.208 1.319 35.298 ;
     RECT  1.319 35.28 1.355 35.298 ;
     RECT  0.535 3.114 2.16 4.554 ;
     RECT  0.535 5.436 2.16 6.984 ;
     RECT  0.139 16.236 2.16 17.064 ;
     RECT  0.535 18.036 2.16 18.792 ;
     RECT  0.499 20.934 2.16 23.148 ;
     RECT  0.103 24.372 2.16 24.39 ;
     RECT  0.499 33.084 2.16 34.182 ;
     RECT  1.211 36.792 2.16 37.044 ;
     RECT  0.535 38.106 2.16 39.114 ;
     RECT  0.203 40.374 2.16 40.392 ;
     RECT  0.535 41.49 2.16 42.714 ;
     RECT  2.16 2.151 6.043 49.689 ;
     RECT  6.043 2.106 7.087 49.689 ;
     RECT  7.087 2.034 8.663 49.689 ;
     RECT  8.663 2.106 9.131 49.689 ;
     RECT  9.131 2.151 14.683 49.689 ;
     RECT  14.683 2.106 14.827 49.689 ;
     RECT  14.827 1.998 16.655 49.689 ;
     RECT  16.655 2.151 34.56 49.689 ;
     RECT  34.56 25.02 34.799 28.584 ;
     RECT  34.56 3.384 35.051 13.968 ;
     RECT  34.56 30.726 35.051 34.146 ;
     RECT  34.56 35.28 35.087 35.298 ;
     RECT  34.56 15.3 35.339 24.228 ;
     RECT  34.799 25.02 35.339 25.578 ;
     RECT  34.799 26.37 35.339 28.584 ;
     RECT  35.051 31.5 35.339 34.146 ;
     RECT  34.56 38.214 35.339 48.42 ;
     RECT  35.051 11.484 35.627 13.968 ;
     RECT  35.339 31.5 35.627 33.948 ;
     RECT  35.627 11.484 35.915 13.734 ;
     RECT  35.339 22.788 35.915 24.228 ;
     RECT  35.051 3.384 35.951 10.728 ;
     RECT  35.915 11.484 35.951 12.618 ;
     RECT  35.339 15.3 35.951 21.924 ;
     RECT  34.56 36.126 35.951 37.458 ;
     RECT  35.951 4.536 35.959 10.728 ;
     RECT  35.951 11.484 35.959 12.384 ;
     RECT  35.959 4.536 35.987 12.384 ;
     RECT  35.627 31.536 35.987 33.948 ;
     RECT  35.339 42.03 35.987 48.42 ;
     RECT  35.987 5.778 36.023 12.384 ;
     RECT  35.339 26.64 36.023 28.584 ;
     RECT  35.951 37.404 36.023 37.458 ;
     RECT  35.339 38.214 36.023 41.274 ;
     RECT  35.987 44.46 36.023 48.42 ;
     RECT  35.987 4.536 36.059 4.95 ;
     RECT  36.023 6.66 36.059 11.538 ;
     RECT  35.951 15.3 36.059 20.214 ;
     RECT  36.023 26.676 36.059 28.584 ;
     RECT  35.987 32.274 36.059 33.948 ;
     RECT  36.023 38.214 36.059 39.888 ;
     RECT  36.059 4.536 36.095 4.788 ;
     RECT  36.059 6.66 36.095 9.774 ;
     RECT  35.951 21.006 36.095 21.924 ;
     RECT  35.339 25.02 36.095 25.308 ;
     RECT  36.059 32.274 36.095 32.328 ;
     RECT  36.059 39.528 36.095 39.888 ;
     RECT  35.987 42.03 36.095 43.56 ;
     RECT  36.095 21.096 36.131 21.924 ;
     RECT  36.059 33.12 36.131 33.948 ;
     RECT  36.095 6.66 36.275 8.226 ;
     RECT  36.059 15.3 36.275 19.674 ;
     RECT  36.059 38.214 36.311 38.304 ;
     RECT  36.275 18.81 36.347 19.674 ;
     RECT  36.275 6.66 36.383 6.678 ;
     RECT  36.311 38.214 36.383 38.232 ;
     RECT  36.023 40.716 36.383 41.004 ;
     RECT  36.095 42.03 36.383 42.669 ;
     RECT  36.275 15.3 36.419 17.784 ;
     RECT  35.915 22.896 36.419 24.228 ;
     RECT  36.383 42.066 36.419 42.669 ;
     RECT  36.023 5.778 36.455 5.796 ;
     RECT  36.131 21.096 36.455 21.762 ;
     RECT  36.095 39.87 36.455 39.888 ;
     RECT  36.419 17.766 36.491 17.784 ;
     RECT  36.347 18.81 36.491 19.602 ;
     RECT  36.023 37.404 36.491 37.422 ;
     RECT  36.095 4.77 36.527 4.788 ;
     RECT  36.419 15.3 36.527 16.704 ;
     RECT  36.095 9.126 36.563 9.774 ;
     RECT  36.527 16.038 36.563 16.704 ;
     RECT  36.059 26.676 36.563 28.206 ;
     RECT  35.951 36.126 36.563 36.612 ;
     RECT  35.915 13.68 36.599 13.734 ;
     RECT  36.419 23.634 36.599 24.228 ;
     RECT  36.563 28.188 36.599 28.206 ;
     RECT  36.383 40.986 36.599 41.004 ;
     RECT  36.419 42.066 36.599 42.624 ;
     RECT  36.599 24.138 36.607 24.228 ;
     RECT  36.095 25.02 36.607 25.038 ;
     RECT  36.275 7.434 36.635 8.226 ;
     RECT  36.563 9.666 36.635 9.774 ;
     RECT  36.059 11.214 36.635 11.538 ;
     RECT  36.023 12.366 36.635 12.384 ;
     RECT  36.563 16.038 36.635 16.056 ;
     RECT  36.491 18.81 36.635 18.909 ;
     RECT  36.455 21.096 36.635 21.492 ;
     RECT  36.607 24.138 36.635 25.038 ;
     RECT  36.563 26.676 36.635 27.162 ;
     RECT  36.095 32.31 36.635 32.328 ;
     RECT  36.131 33.426 36.635 33.948 ;
     RECT  36.563 36.126 36.635 36.144 ;
     RECT  36.599 42.462 36.635 42.624 ;
     RECT  36.095 43.542 36.635 43.56 ;
     RECT  36.023 45 36.635 48.42 ;
     RECT  36.635 7.434 36.671 7.452 ;
     RECT  36.599 13.68 36.671 13.698 ;
     RECT  36.635 21.168 36.671 21.186 ;
     RECT  35.951 3.384 36.707 3.402 ;
     RECT  36.635 8.208 36.707 8.226 ;
     RECT  36.635 24.408 36.707 24.426 ;
     RECT  35.051 30.726 36.707 30.744 ;
     RECT  36.635 42.462 36.707 42.48 ;
     RECT  36.635 46.278 36.707 46.296 ;
     RECT  36.635 47.934 36.707 47.952 ;
    LAYER M3 ;
     RECT  14.832 1.993 14.85 2.065 ;
     RECT  7.092 2.029 7.11 2.101 ;
     RECT  8.64 2.029 8.658 2.101 ;
     RECT  14.832 2.065 15.246 2.101 ;
     RECT  14.688 2.101 15.282 2.143 ;
     RECT  16.632 1.993 16.65 2.143 ;
     RECT  5.115 2.143 5.205 2.191 ;
     RECT  6.048 2.101 9.126 2.191 ;
     RECT  18.615 2.143 18.705 2.191 ;
     RECT  29.415 2.143 29.505 2.191 ;
     RECT  5.076 2.191 9.126 2.227 ;
     RECT  13.215 2.143 13.305 2.227 ;
     RECT  17.964 2.191 18.705 2.227 ;
     RECT  21.315 2.143 21.405 2.227 ;
     RECT  26.715 2.143 26.805 2.227 ;
     RECT  29.088 2.191 29.505 2.227 ;
     RECT  32.115 2.143 32.205 2.227 ;
     RECT  5.076 2.227 9.45 2.251 ;
     RECT  14.688 2.143 16.65 2.251 ;
     RECT  11.376 2.227 11.394 2.263 ;
     RECT  12.312 2.227 12.33 2.263 ;
     RECT  14.688 2.251 16.974 2.263 ;
     RECT  17.748 2.227 18.705 2.263 ;
     RECT  20.916 2.227 21.546 2.263 ;
     RECT  22.464 2.191 22.482 2.263 ;
     RECT  28.404 2.227 29.61 2.263 ;
     RECT  30.456 2.191 31.158 2.263 ;
     RECT  31.932 2.227 32.205 2.263 ;
     RECT  13.068 2.227 13.305 2.335 ;
     RECT  13.068 2.335 13.554 2.347 ;
     RECT  4.392 2.251 9.45 2.371 ;
     RECT  10.515 2.143 10.605 2.371 ;
     RECT  13.068 2.347 13.662 2.371 ;
     RECT  14.688 2.263 18.705 2.371 ;
     RECT  20.916 2.263 22.482 2.371 ;
     RECT  2.415 2.143 2.505 2.413 ;
     RECT  10.368 2.371 10.605 2.413 ;
     RECT  11.376 2.263 12.33 2.413 ;
     RECT  13.068 2.371 18.705 2.413 ;
     RECT  24.015 2.143 24.105 2.413 ;
     RECT  24.912 2.227 24.93 2.413 ;
     RECT  26.28 2.227 26.805 2.413 ;
     RECT  28.404 2.263 32.205 2.413 ;
     RECT  4.392 2.371 9.594 2.461 ;
     RECT  10.368 2.413 12.33 2.461 ;
     RECT  13.068 2.413 18.897 2.461 ;
     RECT  4.392 2.461 19.098 2.533 ;
     RECT  24.015 2.413 24.93 2.587 ;
     RECT  26.28 2.413 26.997 2.587 ;
     RECT  4.392 2.533 19.17 2.605 ;
     RECT  2.415 2.413 2.697 2.641 ;
     RECT  4.356 2.605 19.386 2.641 ;
     RECT  20.772 2.371 22.482 2.641 ;
     RECT  23.868 2.587 24.93 2.641 ;
     RECT  26.28 2.587 27.414 2.641 ;
     RECT  28.404 2.413 32.397 2.641 ;
     RECT  28.368 2.641 32.634 2.767 ;
     RECT  4.248 2.641 27.594 2.839 ;
     RECT  28.368 2.767 33.174 2.839 ;
     RECT  2.415 2.641 3.402 2.875 ;
     RECT  4.176 2.839 33.174 2.875 ;
     RECT  0.54 3.109 0.558 3.271 ;
     RECT  34.164 3.037 34.182 3.299 ;
     RECT  2.415 2.875 33.174 3.499 ;
     RECT  0.108 3.271 0.558 3.917 ;
     RECT  2.304 3.499 33.174 3.919 ;
     RECT  2.232 3.919 33.174 3.991 ;
     RECT  0.108 3.917 0.522 4.013 ;
     RECT  35.928 3.991 35.946 4.123 ;
     RECT  36.684 3.379 36.702 4.123 ;
     RECT  2.232 3.991 33.318 4.261 ;
     RECT  34.056 3.307 34.074 4.261 ;
     RECT  2.232 4.261 34.074 4.351 ;
     RECT  2.196 4.351 34.074 4.487 ;
     RECT  2.196 4.487 19.782 4.493 ;
     RECT  2.304 4.493 19.782 4.523 ;
     RECT  0.108 4.013 0.126 4.589 ;
     RECT  2.304 4.523 19.746 5.341 ;
     RECT  20.52 4.487 34.074 5.341 ;
     RECT  0.18 5.131 0.342 5.431 ;
     RECT  0.18 5.431 0.558 5.611 ;
     RECT  2.304 5.341 34.074 5.701 ;
     RECT  0.108 5.611 0.558 5.729 ;
     RECT  2.304 5.701 34.11 5.881 ;
     RECT  2.304 5.881 34.434 6.475 ;
     RECT  2.268 6.475 34.434 6.719 ;
     RECT  2.304 6.719 34.434 7.147 ;
     RECT  0.144 5.729 0.558 7.709 ;
     RECT  2.304 7.147 34.758 7.735 ;
     RECT  2.304 7.735 34.794 7.933 ;
     RECT  35.928 4.123 36.702 7.933 ;
     RECT  2.304 7.933 36.702 7.949 ;
     RECT  2.304 7.949 34.434 8.159 ;
     RECT  35.352 7.949 36.702 8.231 ;
     RECT  0.324 7.709 0.558 8.237 ;
     RECT  35.352 8.231 36.63 8.24 ;
     RECT  35.352 8.24 36.594 8.813 ;
     RECT  2.304 8.159 34.398 8.879 ;
     RECT  2.304 8.879 34.362 9.041 ;
     RECT  34.308 9.041 34.362 9.113 ;
     RECT  0.144 8.587 0.234 9.163 ;
     RECT  2.304 9.041 33.174 9.239 ;
     RECT  0.144 9.163 0.342 9.259 ;
     RECT  0.108 9.259 0.342 9.383 ;
     RECT  0.18 9.383 0.342 9.389 ;
     RECT  0.18 9.389 0.198 9.533 ;
     RECT  35.352 8.813 36.558 9.643 ;
     RECT  2.304 9.239 33.138 9.779 ;
     RECT  34.344 9.113 34.362 9.835 ;
     RECT  35.352 9.643 36.63 9.835 ;
     RECT  34.344 9.835 36.63 9.883 ;
     RECT  2.415 9.779 33.138 10.165 ;
     RECT  34.236 9.883 36.63 10.349 ;
     RECT  2.415 10.165 33.246 10.552 ;
     RECT  34.236 10.349 36.558 10.603 ;
     RECT  2.415 10.552 33.282 10.903 ;
     RECT  34.2 10.603 36.558 10.903 ;
     RECT  2.415 10.903 36.558 11.003 ;
     RECT  35.316 11.003 36.558 11.179 ;
     RECT  35.316 11.179 36.63 11.707 ;
     RECT  2.415 11.003 34.362 11.785 ;
     RECT  35.316 11.707 36.702 11.785 ;
     RECT  2.415 11.785 36.702 11.894 ;
     RECT  2.415 11.894 34.29 12.047 ;
     RECT  2.415 12.047 34.002 12.173 ;
     RECT  35.352 11.894 36.702 12.389 ;
     RECT  35.352 12.389 35.946 12.557 ;
     RECT  35.388 12.557 35.946 12.749 ;
     RECT  35.388 12.749 35.91 12.845 ;
     RECT  2.415 12.173 33.966 12.893 ;
     RECT  35.892 12.845 35.91 13.361 ;
     RECT  36.684 12.389 36.702 13.675 ;
     RECT  36.648 13.675 36.702 13.711 ;
     RECT  2.415 12.893 33.894 14.341 ;
     RECT  2.415 14.341 34.146 14.647 ;
     RECT  2.415 14.647 34.29 15.061 ;
     RECT  2.376 15.061 34.362 15.197 ;
     RECT  2.376 15.197 17.226 15.287 ;
     RECT  36.576 13.711 36.702 15.295 ;
     RECT  36.504 15.295 36.702 15.547 ;
     RECT  18.108 15.197 34.362 15.565 ;
     RECT  35.604 13.945 35.622 15.565 ;
     RECT  2.376 15.287 17.046 16.027 ;
     RECT  18.108 15.565 35.622 16.123 ;
     RECT  18 16.123 35.622 16.133 ;
     RECT  2.376 16.027 17.226 16.141 ;
     RECT  18 16.133 34.254 16.141 ;
     RECT  0.144 16.231 0.162 16.339 ;
     RECT  2.376 16.141 34.254 16.349 ;
     RECT  0.144 16.339 0.558 16.681 ;
     RECT  36.432 15.547 36.702 17.077 ;
     RECT  0.108 16.681 0.558 17.165 ;
     RECT  2.412 16.349 34.254 17.185 ;
     RECT  2.304 17.185 34.254 17.323 ;
     RECT  35.028 16.133 35.622 17.371 ;
     RECT  36.396 17.077 36.702 17.371 ;
     RECT  2.268 17.323 34.254 17.419 ;
     RECT  35.028 17.371 36.702 17.419 ;
     RECT  2.268 17.419 36.702 17.447 ;
     RECT  0.108 17.165 0.342 17.933 ;
     RECT  0.144 17.933 0.342 18.031 ;
     RECT  2.304 17.447 36.702 18.379 ;
     RECT  0.144 18.031 0.558 18.509 ;
     RECT  0.144 18.509 0.342 18.769 ;
     RECT  0.108 18.769 0.342 18.893 ;
     RECT  2.268 18.379 36.702 19.031 ;
     RECT  2.268 19.031 34.29 19.067 ;
     RECT  2.304 19.067 34.29 19.229 ;
     RECT  0.144 18.893 0.342 19.277 ;
     RECT  2.304 19.229 34.254 20.425 ;
     RECT  35.028 19.031 36.702 20.425 ;
     RECT  0.144 19.277 0.234 20.929 ;
     RECT  0.144 20.929 0.522 21.001 ;
     RECT  0.144 21.001 0.558 21.631 ;
     RECT  0.108 21.631 0.558 21.739 ;
     RECT  0.108 21.739 1.17 21.869 ;
     RECT  1.152 21.869 1.17 21.931 ;
     RECT  1.152 21.931 1.278 21.965 ;
     RECT  1.26 21.965 1.278 22.061 ;
     RECT  2.304 20.425 36.702 22.603 ;
     RECT  2.268 22.603 36.702 22.649 ;
     RECT  0.108 21.869 0.414 23.125 ;
     RECT  0.108 23.125 0.558 23.309 ;
     RECT  2.304 22.649 36.702 23.755 ;
     RECT  0.54 23.309 0.558 23.947 ;
     RECT  0.54 23.947 1.17 23.981 ;
     RECT  1.152 23.981 1.17 24.077 ;
     RECT  2.232 23.755 36.702 24.187 ;
     RECT  2.196 24.187 36.702 24.365 ;
     RECT  2.268 24.365 36.702 24.413 ;
     RECT  2.304 24.413 36.702 24.431 ;
     RECT  2.304 24.431 36.63 25.007 ;
     RECT  35.028 25.007 36.63 25.043 ;
     RECT  0.108 24.367 0.126 25.099 ;
     RECT  0.108 25.099 0.342 25.313 ;
     RECT  0.18 25.313 0.342 25.325 ;
     RECT  0.18 25.325 0.198 25.469 ;
     RECT  2.304 25.007 34.254 25.825 ;
     RECT  35.028 25.043 36.594 25.825 ;
     RECT  2.304 25.825 36.594 26.189 ;
     RECT  2.304 26.189 34.218 26.249 ;
     RECT  2.415 26.249 34.218 26.285 ;
     RECT  35.316 26.189 36.594 26.477 ;
     RECT  35.928 26.477 36.594 26.635 ;
     RECT  2.415 26.285 34.182 27.115 ;
     RECT  2.415 27.115 34.29 27.167 ;
     RECT  2.415 27.167 33.93 27.329 ;
     RECT  30.6 27.329 33.93 27.389 ;
     RECT  35.928 26.635 36.63 27.533 ;
     RECT  30.672 27.389 33.93 27.671 ;
     RECT  35.928 27.533 36.594 28.211 ;
     RECT  35.928 28.211 36.558 28.301 ;
     RECT  2.415 27.329 29.826 28.417 ;
     RECT  30.672 27.671 33.282 28.417 ;
     RECT  35.928 28.301 36.522 28.589 ;
     RECT  2.415 28.417 33.282 28.651 ;
     RECT  34.056 27.913 34.074 28.651 ;
     RECT  35.928 28.589 36.378 28.685 ;
     RECT  35.928 28.685 36.342 28.781 ;
     RECT  2.415 28.651 34.074 28.795 ;
     RECT  35.928 28.781 36.054 28.877 ;
     RECT  36 28.877 36.054 28.973 ;
     RECT  36.036 28.973 36.054 29.069 ;
     RECT  2.415 28.795 34.146 29.371 ;
     RECT  2.376 29.371 34.146 29.645 ;
     RECT  2.415 29.645 34.146 30.451 ;
     RECT  35.028 31.423 35.046 31.495 ;
     RECT  35.028 31.495 35.622 31.531 ;
     RECT  36.684 30.721 36.702 31.531 ;
     RECT  2.376 30.451 34.146 31.919 ;
     RECT  35.028 31.531 36.702 32.141 ;
     RECT  2.415 31.919 34.146 32.251 ;
     RECT  35.028 32.141 36.63 32.333 ;
     RECT  35.028 32.333 36.594 32.429 ;
     RECT  2.415 32.251 34.182 32.827 ;
     RECT  2.415 32.827 34.218 33.115 ;
     RECT  35.028 32.429 36.558 33.115 ;
     RECT  0.504 33.079 0.522 33.349 ;
     RECT  2.415 33.115 36.558 33.355 ;
     RECT  0.504 33.349 0.558 33.511 ;
     RECT  2.415 33.355 36.63 33.539 ;
     RECT  0.108 33.511 0.558 33.677 ;
     RECT  2.415 33.539 34.218 33.739 ;
     RECT  35.028 33.539 36.63 33.953 ;
     RECT  35.028 33.953 35.946 33.965 ;
     RECT  2.304 33.739 34.218 34.123 ;
     RECT  0.108 33.677 0.522 34.159 ;
     RECT  2.196 34.123 34.218 34.349 ;
     RECT  0.036 34.159 0.522 34.445 ;
     RECT  2.304 34.349 34.218 34.465 ;
     RECT  0.036 34.445 0.342 34.733 ;
     RECT  0.036 34.733 0.162 34.799 ;
     RECT  2.304 34.465 34.29 34.889 ;
     RECT  2.304 34.889 34.254 35.159 ;
     RECT  1.224 35.179 1.35 35.275 ;
     RECT  1.188 35.275 1.35 35.303 ;
     RECT  1.188 35.303 1.314 35.309 ;
     RECT  1.188 35.309 1.242 35.467 ;
     RECT  1.152 35.467 1.242 35.597 ;
     RECT  0.108 34.799 0.162 35.885 ;
     RECT  0.108 35.885 0.126 35.981 ;
     RECT  2.304 35.159 34.11 36.121 ;
     RECT  35.028 33.965 35.622 36.121 ;
     RECT  36.684 35.227 36.702 36.121 ;
     RECT  36.612 36.121 36.702 36.589 ;
     RECT  2.304 36.121 35.622 36.661 ;
     RECT  36.54 36.589 36.702 36.661 ;
     RECT  0.144 36.715 0.162 36.751 ;
     RECT  1.152 35.597 1.17 36.751 ;
     RECT  2.304 36.661 36.702 36.779 ;
     RECT  0.108 36.751 0.162 36.787 ;
     RECT  1.152 36.751 1.206 36.787 ;
     RECT  0.108 36.787 1.206 36.887 ;
     RECT  0.108 36.887 0.558 37.133 ;
     RECT  0.144 37.133 0.558 37.229 ;
     RECT  2.304 36.779 34.29 37.363 ;
     RECT  0.144 37.229 0.522 37.421 ;
     RECT  2.268 37.363 34.29 37.741 ;
     RECT  35.028 36.779 36.702 37.741 ;
     RECT  0.144 37.421 0.486 38.173 ;
     RECT  2.196 37.741 36.702 38.507 ;
     RECT  0.108 38.173 0.486 38.861 ;
     RECT  0.144 38.861 0.486 39.091 ;
     RECT  0.144 39.091 0.558 39.437 ;
     RECT  2.268 38.507 36.702 39.451 ;
     RECT  2.232 39.451 36.702 39.479 ;
     RECT  35.028 39.479 36.702 40.013 ;
     RECT  0.144 39.437 0.198 40.06 ;
     RECT  35.352 40.013 36.702 40.109 ;
     RECT  0.108 40.06 0.198 40.267 ;
     RECT  2.232 39.479 34.182 40.433 ;
     RECT  0.108 40.267 0.342 40.589 ;
     RECT  2.268 40.433 34.182 40.801 ;
     RECT  35.388 40.109 36.702 40.843 ;
     RECT  2.268 40.801 34.29 41.009 ;
     RECT  2.304 41.009 34.29 41.131 ;
     RECT  35.316 40.843 36.702 41.131 ;
     RECT  1.152 41.131 1.17 41.261 ;
     RECT  0.288 40.589 0.342 41.323 ;
     RECT  0.216 41.323 0.342 41.485 ;
     RECT  0.216 41.485 0.558 41.645 ;
     RECT  2.304 41.131 36.702 41.711 ;
     RECT  0.216 41.645 0.342 41.755 ;
     RECT  0.144 41.755 0.342 41.881 ;
     RECT  2.304 41.711 34.218 42.179 ;
     RECT  35.316 41.711 36.702 42.287 ;
     RECT  35.352 42.287 36.702 42.485 ;
     RECT  0.108 41.881 0.342 42.601 ;
     RECT  2.34 42.179 34.218 42.763 ;
     RECT  0.108 42.601 0.558 42.797 ;
     RECT  2.34 42.763 34.29 42.955 ;
     RECT  2.304 42.955 34.29 42.989 ;
     RECT  2.304 42.989 34.218 43.147 ;
     RECT  2.268 43.147 34.218 43.403 ;
     RECT  0.108 42.797 0.342 43.537 ;
     RECT  0.108 43.537 0.378 43.565 ;
     RECT  35.352 42.485 36.63 43.565 ;
     RECT  0.216 43.565 0.378 43.661 ;
     RECT  35.352 43.565 36.594 43.661 ;
     RECT  2.304 43.403 34.218 43.843 ;
     RECT  35.352 43.661 36.414 43.843 ;
     RECT  2.304 43.843 36.414 43.853 ;
     RECT  35.928 43.853 36.414 44.045 ;
     RECT  1.152 43.099 1.17 44.203 ;
     RECT  2.304 43.853 34.794 44.299 ;
     RECT  1.152 44.203 1.386 44.429 ;
     RECT  35.928 44.045 36.378 44.429 ;
     RECT  0.216 43.661 0.342 44.491 ;
     RECT  35.964 44.429 36.378 44.525 ;
     RECT  2.268 44.299 34.794 44.587 ;
     RECT  2.232 44.587 34.794 44.761 ;
     RECT  0.144 44.491 0.342 44.875 ;
     RECT  36 44.525 36.378 44.875 ;
     RECT  0.108 44.875 0.342 44.909 ;
     RECT  0.108 44.909 0.126 45.005 ;
     RECT  1.152 44.429 1.17 45.005 ;
     RECT  2.232 44.761 34.83 45.101 ;
     RECT  36 44.875 36.63 45.293 ;
     RECT  2.232 45.101 34.218 45.599 ;
     RECT  2.34 45.599 34.218 45.869 ;
     RECT  2.34 45.869 33.858 45.959 ;
     RECT  36.576 45.293 36.63 46.273 ;
     RECT  35.316 45.931 35.334 46.373 ;
     RECT  36.576 46.273 36.702 46.411 ;
     RECT  36.54 46.411 36.702 46.507 ;
     RECT  36.468 46.507 36.702 46.603 ;
     RECT  34.812 46.699 34.83 46.913 ;
     RECT  2.415 45.959 33.858 47.039 ;
     RECT  36.432 46.603 36.702 47.047 ;
     RECT  3.42 47.039 33.858 47.155 ;
     RECT  35.928 47.047 36.702 47.371 ;
     RECT  3.42 47.155 33.966 47.489 ;
     RECT  3.528 47.489 33.966 47.579 ;
     RECT  35.316 47.371 36.702 47.693 ;
     RECT  3.564 47.579 33.966 47.849 ;
     RECT  3.564 47.849 33.642 47.885 ;
     RECT  35.316 47.693 35.37 47.885 ;
     RECT  36.576 47.693 36.702 47.957 ;
     RECT  35.352 47.885 35.37 48.077 ;
     RECT  36.576 47.957 36.63 48.227 ;
     RECT  3.564 47.885 33.534 48.269 ;
     RECT  3.564 48.269 33.39 48.389 ;
     RECT  36.612 48.227 36.63 48.425 ;
     RECT  2.415 47.039 2.697 48.475 ;
     RECT  3.564 48.389 33.354 48.475 ;
     RECT  2.415 48.475 33.354 48.533 ;
     RECT  4.248 48.533 33.354 48.929 ;
     RECT  2.415 48.533 3.402 48.965 ;
     RECT  4.608 48.929 33.354 49.073 ;
     RECT  4.716 49.073 33.354 49.199 ;
     RECT  18.576 49.199 33.354 49.235 ;
     RECT  4.716 49.199 17.262 49.343 ;
     RECT  18.576 49.235 24.786 49.343 ;
     RECT  28.116 49.235 33.354 49.343 ;
     RECT  12.888 49.343 17.262 49.373 ;
     RECT  28.116 49.343 32.742 49.379 ;
     RECT  2.415 48.965 2.697 49.427 ;
     RECT  4.716 49.343 11.826 49.427 ;
     RECT  25.524 49.235 26.997 49.427 ;
     RECT  28.116 49.379 31.23 49.427 ;
     RECT  4.716 49.427 10.605 49.469 ;
     RECT  11.376 49.427 11.826 49.469 ;
     RECT  12.888 49.373 14.31 49.469 ;
     RECT  15.156 49.373 17.262 49.469 ;
     RECT  19.8 49.343 24.786 49.469 ;
     RECT  25.524 49.427 26.805 49.469 ;
     RECT  28.116 49.427 29.574 49.469 ;
     RECT  30.348 49.427 31.23 49.469 ;
     RECT  4.716 49.469 5.274 49.505 ;
     RECT  7.344 49.469 10.605 49.505 ;
     RECT  11.376 49.469 11.718 49.505 ;
     RECT  13.14 49.469 13.305 49.505 ;
     RECT  20.916 49.469 22.014 49.505 ;
     RECT  28.116 49.469 28.458 49.505 ;
     RECT  30.6 49.469 31.23 49.505 ;
     RECT  32.004 49.379 32.742 49.505 ;
     RECT  18.576 49.343 19.026 49.517 ;
     RECT  19.8 49.469 19.818 49.517 ;
     RECT  21.315 49.505 22.014 49.517 ;
     RECT  23.436 49.469 24.786 49.517 ;
     RECT  4.932 49.505 5.274 49.541 ;
     RECT  11.376 49.505 11.394 49.565 ;
     RECT  7.344 49.505 8.478 49.577 ;
     RECT  15.156 49.469 16.005 49.577 ;
     RECT  23.436 49.517 24.105 49.577 ;
     RECT  28.116 49.505 28.134 49.577 ;
     RECT  30.708 49.505 31.23 49.577 ;
     RECT  32.115 49.505 32.742 49.577 ;
     RECT  4.932 49.541 5.205 49.613 ;
     RECT  7.344 49.577 8.298 49.613 ;
     RECT  25.632 49.469 25.65 49.613 ;
     RECT  15.624 49.577 16.005 49.649 ;
     RECT  2.415 49.427 2.505 49.697 ;
     RECT  5.115 49.613 5.205 49.697 ;
     RECT  7.815 49.613 7.905 49.697 ;
     RECT  10.515 49.505 10.605 49.697 ;
     RECT  13.215 49.505 13.305 49.697 ;
     RECT  15.915 49.649 16.005 49.697 ;
     RECT  18.615 49.517 18.705 49.697 ;
     RECT  21.315 49.517 21.405 49.697 ;
     RECT  24.015 49.577 24.105 49.697 ;
     RECT  26.715 49.469 26.805 49.697 ;
     RECT  29.415 49.469 29.505 49.697 ;
     RECT  32.115 49.577 32.205 49.697 ;
    LAYER M4 ;
     RECT  0.084 33.648 0.097 33.672 ;
     RECT  0.06 33.672 0.097 33.744 ;
     RECT  0.084 33.744 0.097 33.768 ;
     RECT  0.06 33.768 0.097 33.84 ;
     RECT  0.084 33.84 0.097 33.864 ;
     RECT  0.06 33.864 0.097 33.936 ;
     RECT  0.084 33.936 0.097 33.96 ;
     RECT  0.06 33.96 0.097 34.032 ;
     RECT  0.084 34.032 0.097 34.056 ;
     RECT  0.06 34.056 0.097 34.128 ;
     RECT  0.084 34.128 0.097 34.152 ;
     RECT  0.06 34.152 0.097 34.224 ;
     RECT  0.084 34.224 0.097 34.248 ;
     RECT  0.06 34.248 0.097 34.32 ;
     RECT  0.084 34.32 0.097 34.344 ;
     RECT  0.06 34.344 0.097 34.416 ;
     RECT  0.084 34.416 0.097 34.44 ;
     RECT  0.06 34.44 0.097 34.512 ;
     RECT  0.084 34.512 0.097 34.536 ;
     RECT  0.06 34.536 0.097 34.608 ;
     RECT  0.084 34.608 0.097 34.632 ;
     RECT  0.06 34.632 0.097 34.704 ;
     RECT  0.084 34.704 0.097 34.728 ;
     RECT  0.06 34.728 0.097 34.8 ;
     RECT  0.084 34.8 0.097 34.824 ;
     RECT  0.06 34.824 0.097 34.896 ;
     RECT  0.084 34.896 0.097 34.92 ;
     RECT  0.06 34.92 0.097 34.992 ;
     RECT  0.084 34.992 0.097 35.016 ;
     RECT  0.06 35.016 0.097 35.088 ;
     RECT  0.084 35.088 0.097 35.112 ;
     RECT  0.06 35.112 0.097 35.184 ;
     RECT  0.084 35.184 0.097 35.208 ;
     RECT  0.06 35.208 0.097 35.28 ;
     RECT  0.084 35.28 0.097 35.304 ;
     RECT  0.06 35.304 0.097 35.376 ;
     RECT  0.084 35.376 0.097 35.4 ;
     RECT  0.06 35.4 0.097 35.472 ;
     RECT  0.084 35.472 0.097 35.496 ;
     RECT  0.06 35.496 0.097 35.568 ;
     RECT  0.084 35.568 0.097 35.592 ;
     RECT  0.06 35.592 0.097 35.664 ;
     RECT  0.084 35.664 0.097 35.688 ;
     RECT  0.06 35.688 0.097 35.76 ;
     RECT  0.084 35.76 0.097 35.784 ;
     RECT  0.06 35.784 0.097 35.856 ;
     RECT  0.084 35.856 0.097 35.88 ;
     RECT  0.06 35.88 0.097 35.952 ;
     RECT  0.084 35.952 0.097 35.976 ;
     RECT  0.06 35.976 0.097 36.048 ;
     RECT  0.084 36.048 0.097 36.072 ;
     RECT  0.06 36.072 0.097 36.144 ;
     RECT  0.084 36.144 0.097 36.168 ;
     RECT  0.06 36.168 0.097 36.24 ;
     RECT  0.084 36.24 0.097 36.264 ;
     RECT  0.06 36.264 0.097 36.336 ;
     RECT  0.084 36.336 0.097 36.36 ;
     RECT  0.06 36.36 0.097 36.432 ;
     RECT  0.084 36.432 0.097 36.456 ;
     RECT  0.06 36.456 0.097 36.528 ;
     RECT  0.084 36.528 0.097 36.552 ;
     RECT  0.06 36.552 0.097 36.624 ;
     RECT  0.084 36.624 0.097 36.648 ;
     RECT  0.06 36.648 0.097 36.72 ;
     RECT  0.084 36.72 0.097 36.744 ;
     RECT  0.06 36.744 0.097 36.816 ;
     RECT  0.084 36.816 0.097 36.84 ;
     RECT  0.06 36.84 0.097 36.912 ;
     RECT  0.084 36.912 0.097 36.936 ;
     RECT  0.06 36.936 0.097 37.008 ;
     RECT  0.084 37.008 0.097 37.032 ;
     RECT  0.06 37.032 0.097 37.104 ;
     RECT  0.084 37.104 0.097 37.128 ;
     RECT  0.06 37.128 0.097 37.2 ;
     RECT  0.084 37.2 0.097 37.224 ;
     RECT  0.06 37.224 0.097 37.296 ;
     RECT  0.084 37.296 0.097 37.32 ;
     RECT  0.06 37.32 0.097 37.392 ;
     RECT  0.084 37.392 0.097 37.416 ;
     RECT  0.06 37.416 0.097 37.488 ;
     RECT  0.084 37.488 0.097 37.512 ;
     RECT  0.06 37.512 0.097 37.584 ;
     RECT  0.084 37.584 0.097 37.608 ;
     RECT  0.06 37.608 0.097 37.68 ;
     RECT  0.084 37.68 0.097 37.704 ;
     RECT  0.06 37.704 0.097 37.776 ;
     RECT  0.084 37.776 0.097 37.8 ;
     RECT  0.06 37.8 0.097 37.872 ;
     RECT  0.084 37.872 0.097 37.896 ;
     RECT  0.06 37.896 0.097 37.968 ;
     RECT  0.084 37.968 0.097 37.992 ;
     RECT  0.06 37.992 0.097 38.064 ;
     RECT  0.084 38.064 0.097 38.088 ;
     RECT  0.06 38.088 0.097 38.16 ;
     RECT  0.084 38.16 0.097 38.184 ;
     RECT  0.06 38.184 0.097 38.256 ;
     RECT  0.084 38.256 0.097 38.28 ;
     RECT  0.06 38.28 0.097 38.352 ;
     RECT  0.084 38.352 0.097 38.376 ;
     RECT  0.06 38.376 0.097 38.448 ;
     RECT  0.084 38.448 0.097 38.472 ;
     RECT  0.06 38.472 0.097 38.544 ;
     RECT  0.084 38.544 0.097 38.568 ;
     RECT  0.06 38.568 0.097 38.64 ;
     RECT  0.084 38.64 0.097 38.664 ;
     RECT  0.06 38.664 0.097 38.736 ;
     RECT  0.084 38.736 0.097 38.76 ;
     RECT  0.06 38.76 0.097 38.832 ;
     RECT  0.084 38.832 0.097 38.856 ;
     RECT  0.06 38.856 0.097 38.928 ;
     RECT  0.084 38.928 0.097 38.952 ;
     RECT  0.06 38.952 0.097 39.024 ;
     RECT  0.084 39.024 0.097 39.048 ;
     RECT  0.06 39.048 0.097 39.12 ;
     RECT  0.084 39.12 0.097 39.144 ;
     RECT  0.06 39.144 0.097 39.216 ;
     RECT  0.084 39.216 0.097 39.24 ;
     RECT  0.06 39.24 0.097 39.312 ;
     RECT  0.084 39.312 0.097 39.336 ;
     RECT  0.06 39.336 0.097 39.408 ;
     RECT  0.084 39.408 0.097 39.432 ;
     RECT  0.06 39.432 0.097 39.504 ;
     RECT  0.084 39.504 0.097 39.528 ;
     RECT  0.06 39.528 0.097 39.6 ;
     RECT  0.084 39.6 0.097 39.624 ;
     RECT  0.06 39.624 0.097 39.696 ;
     RECT  0.084 39.696 0.097 39.72 ;
     RECT  0.06 39.72 0.097 39.792 ;
     RECT  0.084 39.792 0.097 39.816 ;
     RECT  0.06 39.816 0.097 39.888 ;
     RECT  0.084 39.888 0.097 39.912 ;
     RECT  0.06 39.912 0.097 39.984 ;
     RECT  0.084 39.984 0.097 40.008 ;
     RECT  0.06 40.008 0.097 40.08 ;
     RECT  0.084 40.08 0.097 40.104 ;
     RECT  0.06 40.104 0.097 40.176 ;
     RECT  0.084 40.176 0.097 40.2 ;
     RECT  0.06 40.2 0.097 40.272 ;
     RECT  0.084 40.272 0.097 40.296 ;
     RECT  0.06 40.296 0.097 40.368 ;
     RECT  0.084 40.368 0.097 40.392 ;
     RECT  0.06 40.392 0.097 40.464 ;
     RECT  0.084 40.464 0.097 40.488 ;
     RECT  0.06 40.488 0.097 40.56 ;
     RECT  0.084 40.56 0.097 40.584 ;
     RECT  0.06 40.584 0.097 40.656 ;
     RECT  0.084 40.656 0.097 40.68 ;
     RECT  0.06 40.68 0.097 40.752 ;
     RECT  0.084 40.752 0.097 40.776 ;
     RECT  0.06 40.776 0.097 40.848 ;
     RECT  0.084 40.848 0.097 40.872 ;
     RECT  0.06 40.872 0.097 40.944 ;
     RECT  0.084 40.944 0.097 40.968 ;
     RECT  0.06 40.968 0.097 41.04 ;
     RECT  0.084 41.04 0.097 41.064 ;
     RECT  0.06 41.064 0.097 41.136 ;
     RECT  0.084 41.136 0.097 41.16 ;
     RECT  0.06 41.16 0.097 41.232 ;
     RECT  0.084 41.232 0.097 41.256 ;
     RECT  0.06 41.256 0.097 41.328 ;
     RECT  0.084 41.328 0.097 41.352 ;
     RECT  0.06 41.352 0.097 41.424 ;
     RECT  0.084 41.424 0.097 41.448 ;
     RECT  0.06 41.448 0.097 41.52 ;
     RECT  0.084 41.52 0.097 41.544 ;
     RECT  0.06 41.544 0.097 41.616 ;
     RECT  0.084 41.616 0.097 41.64 ;
     RECT  0.06 41.64 0.097 41.712 ;
     RECT  0.084 41.712 0.097 41.736 ;
     RECT  0.06 41.736 0.097 41.808 ;
     RECT  0.084 41.808 0.097 41.832 ;
     RECT  0.06 41.832 0.097 41.904 ;
     RECT  0.084 41.904 0.097 41.928 ;
     RECT  0.06 41.928 0.097 42 ;
     RECT  0.084 42 0.097 42.024 ;
     RECT  0.06 42.024 0.097 42.096 ;
     RECT  0.084 42.096 0.097 42.12 ;
     RECT  0.06 42.12 0.097 42.192 ;
     RECT  0.084 42.192 0.097 42.216 ;
     RECT  0.06 42.216 0.097 42.288 ;
     RECT  0.084 42.288 0.097 42.312 ;
     RECT  0.06 42.312 0.097 42.384 ;
     RECT  0.084 42.384 0.097 42.408 ;
     RECT  0.06 42.408 0.097 42.48 ;
     RECT  0.084 42.48 0.097 42.504 ;
     RECT  0.06 42.504 0.097 42.576 ;
     RECT  0.084 42.576 0.097 42.6 ;
     RECT  0.06 42.6 0.097 42.672 ;
     RECT  0.084 42.672 0.097 42.696 ;
     RECT  0.06 42.696 0.097 42.768 ;
     RECT  0.084 42.768 0.097 42.792 ;
     RECT  0.06 42.792 0.097 42.864 ;
     RECT  0.084 42.864 0.097 42.888 ;
     RECT  0.06 42.888 0.097 42.96 ;
     RECT  0.084 42.96 0.097 42.984 ;
     RECT  0.06 42.984 0.097 43.056 ;
     RECT  0.084 43.056 0.097 43.08 ;
     RECT  0.06 43.08 0.097 43.152 ;
     RECT  0.084 43.152 0.097 43.176 ;
     RECT  0.06 43.176 0.097 43.248 ;
     RECT  0.084 43.248 0.097 43.272 ;
     RECT  0.06 43.272 0.097 43.344 ;
     RECT  0.084 43.344 0.097 43.368 ;
     RECT  0.06 43.368 0.097 43.44 ;
     RECT  0.084 43.44 0.097 43.464 ;
     RECT  0.06 43.464 0.097 43.536 ;
     RECT  0.084 43.536 0.097 43.56 ;
     RECT  0.06 43.56 0.097 43.632 ;
     RECT  0.084 43.632 0.097 43.656 ;
     RECT  0.06 43.656 0.097 43.728 ;
     RECT  0.084 43.728 0.097 43.752 ;
     RECT  0.06 43.752 0.097 43.824 ;
     RECT  0.084 43.824 0.097 43.848 ;
     RECT  0.06 43.848 0.097 43.92 ;
     RECT  0.084 43.92 0.097 43.944 ;
     RECT  0.06 43.944 0.097 44.016 ;
     RECT  0.084 44.016 0.097 44.04 ;
     RECT  0.06 44.04 0.097 44.112 ;
     RECT  0.084 44.112 0.097 44.136 ;
     RECT  0.06 44.136 0.097 44.208 ;
     RECT  0.084 44.208 0.097 44.232 ;
     RECT  0.06 44.232 0.097 44.304 ;
     RECT  0.084 44.304 0.097 44.328 ;
     RECT  0.06 44.328 0.097 44.4 ;
     RECT  0.084 44.4 0.097 44.424 ;
     RECT  0.06 44.424 0.097 44.496 ;
     RECT  0.084 44.496 0.097 44.52 ;
     RECT  0.06 44.52 0.097 44.592 ;
     RECT  0.084 44.592 0.097 44.616 ;
     RECT  0.06 44.616 0.097 44.688 ;
     RECT  0.084 44.688 0.097 44.712 ;
     RECT  0.06 44.712 0.097 44.784 ;
     RECT  0.084 44.784 0.097 44.808 ;
     RECT  0.06 44.808 0.097 44.88 ;
     RECT  0.084 44.88 0.097 44.904 ;
     RECT  0.097 33.648 0.569 45 ;
     RECT  0.569 33.744 1.181 45 ;
     RECT  0.084 16.56 2.365 16.584 ;
     RECT  0.06 16.584 2.365 16.656 ;
     RECT  0.084 16.656 2.365 16.68 ;
     RECT  0.06 16.68 2.365 16.752 ;
     RECT  0.084 16.752 2.365 16.776 ;
     RECT  0.06 16.776 2.365 16.848 ;
     RECT  0.084 16.848 2.365 16.872 ;
     RECT  0.06 16.872 2.365 16.944 ;
     RECT  0.084 16.944 2.365 16.968 ;
     RECT  0.06 16.968 2.365 17.04 ;
     RECT  0.084 17.04 2.365 17.064 ;
     RECT  0.06 17.064 2.365 17.136 ;
     RECT  0.084 17.136 2.365 17.16 ;
     RECT  0.06 17.16 2.365 17.232 ;
     RECT  0.084 17.232 2.365 17.256 ;
     RECT  0.06 17.256 2.365 17.328 ;
     RECT  0.084 17.328 2.365 17.352 ;
     RECT  0.06 17.352 2.365 17.424 ;
     RECT  0.084 17.424 2.365 17.448 ;
     RECT  0.06 17.448 2.365 17.52 ;
     RECT  0.084 17.52 2.365 17.544 ;
     RECT  0.06 17.544 2.365 17.616 ;
     RECT  0.084 17.616 2.365 17.64 ;
     RECT  0.06 17.64 2.365 17.712 ;
     RECT  0.084 17.712 2.365 17.736 ;
     RECT  0.06 17.736 2.365 17.808 ;
     RECT  0.084 17.808 2.365 17.832 ;
     RECT  0.06 17.832 2.365 17.904 ;
     RECT  0.084 17.904 2.365 17.928 ;
     RECT  0.06 17.928 2.365 18 ;
     RECT  0.084 18 2.365 18.024 ;
     RECT  0.06 18.024 2.365 18.096 ;
     RECT  0.084 18.096 2.365 18.12 ;
     RECT  0.06 18.12 2.365 18.192 ;
     RECT  0.084 18.192 2.365 18.216 ;
     RECT  0.06 18.216 2.365 18.288 ;
     RECT  0.084 18.288 2.365 18.312 ;
     RECT  0.06 18.312 2.365 18.384 ;
     RECT  0.084 18.384 2.365 18.408 ;
     RECT  0.06 18.408 2.365 18.48 ;
     RECT  0.084 18.48 2.365 18.504 ;
     RECT  0.06 18.504 2.365 18.576 ;
     RECT  0.084 18.576 2.365 18.6 ;
     RECT  0.06 18.6 2.365 18.672 ;
     RECT  0.084 18.672 2.365 18.696 ;
     RECT  0.06 18.696 2.365 18.768 ;
     RECT  0.084 18.768 2.365 18.792 ;
     RECT  0.06 18.792 2.365 18.864 ;
     RECT  0.084 18.864 2.365 18.888 ;
     RECT  0.06 18.888 2.365 18.96 ;
     RECT  0.084 18.96 2.365 18.984 ;
     RECT  0.06 18.984 2.365 19.056 ;
     RECT  0.084 19.056 2.365 19.08 ;
     RECT  0.06 19.08 2.365 19.152 ;
     RECT  0.084 19.152 2.365 19.176 ;
     RECT  0.06 19.176 2.365 19.248 ;
     RECT  0.084 19.248 2.365 19.272 ;
     RECT  0.06 19.272 2.365 19.344 ;
     RECT  0.084 19.344 2.365 19.368 ;
     RECT  0.06 19.368 2.365 19.44 ;
     RECT  0.084 19.44 2.365 19.464 ;
     RECT  0.06 19.464 2.365 19.536 ;
     RECT  0.084 19.536 2.365 19.56 ;
     RECT  0.06 19.56 2.365 19.632 ;
     RECT  0.084 19.632 2.365 19.656 ;
     RECT  0.06 19.656 2.365 19.728 ;
     RECT  0.084 19.728 2.365 19.752 ;
     RECT  0.06 19.752 2.365 19.824 ;
     RECT  0.084 19.824 2.365 19.848 ;
     RECT  0.06 19.848 2.365 19.92 ;
     RECT  0.084 19.92 2.365 19.944 ;
     RECT  0.06 19.944 2.365 20.016 ;
     RECT  0.084 20.016 2.365 20.04 ;
     RECT  0.06 20.04 2.365 20.112 ;
     RECT  0.084 20.112 2.365 20.136 ;
     RECT  0.06 20.136 2.365 20.208 ;
     RECT  0.084 20.208 2.365 20.232 ;
     RECT  0.06 20.232 2.365 20.304 ;
     RECT  0.084 20.304 2.365 20.328 ;
     RECT  0.06 20.328 2.365 20.4 ;
     RECT  0.084 20.4 2.365 20.424 ;
     RECT  0.06 20.424 2.365 20.496 ;
     RECT  0.084 20.496 2.365 20.52 ;
     RECT  0.06 20.52 2.365 20.592 ;
     RECT  0.084 20.592 2.365 20.616 ;
     RECT  0.06 20.616 2.365 20.688 ;
     RECT  0.084 20.688 2.365 20.712 ;
     RECT  0.06 20.712 2.365 20.784 ;
     RECT  0.084 20.784 2.365 20.808 ;
     RECT  0.06 20.808 2.365 20.88 ;
     RECT  0.084 20.88 2.365 20.904 ;
     RECT  0.06 20.904 2.365 20.976 ;
     RECT  0.084 20.976 2.365 21 ;
     RECT  0.06 21 2.365 21.072 ;
     RECT  0.084 21.072 2.365 21.096 ;
     RECT  0.06 21.096 2.365 21.168 ;
     RECT  0.084 21.168 2.365 21.192 ;
     RECT  0.06 21.192 2.365 21.264 ;
     RECT  0.084 21.264 2.365 21.288 ;
     RECT  0.06 21.288 2.365 21.36 ;
     RECT  0.084 21.36 2.365 21.384 ;
     RECT  0.06 21.384 2.365 21.456 ;
     RECT  0.084 21.456 2.365 21.48 ;
     RECT  0.06 21.48 2.365 21.552 ;
     RECT  0.084 21.552 2.365 21.576 ;
     RECT  0.06 21.576 2.365 21.648 ;
     RECT  0.084 21.648 2.365 21.672 ;
     RECT  0.06 21.672 2.365 21.744 ;
     RECT  0.084 21.744 2.365 21.768 ;
     RECT  0.06 21.768 2.365 21.84 ;
     RECT  0.084 21.84 2.365 21.864 ;
     RECT  0.06 21.864 2.365 21.936 ;
     RECT  0.084 21.936 2.365 21.96 ;
     RECT  0.06 21.96 2.365 22.032 ;
     RECT  0.084 22.032 2.365 22.056 ;
     RECT  0.06 22.056 2.365 22.128 ;
     RECT  0.084 22.128 2.365 22.152 ;
     RECT  0.06 22.152 2.365 22.224 ;
     RECT  0.084 22.224 2.365 22.248 ;
     RECT  0.06 22.248 2.365 22.32 ;
     RECT  0.084 22.32 2.365 22.344 ;
     RECT  0.06 22.344 2.365 22.416 ;
     RECT  0.084 22.416 2.365 22.44 ;
     RECT  0.06 22.44 2.365 22.512 ;
     RECT  0.084 22.512 2.365 22.536 ;
     RECT  0.06 22.536 2.365 22.608 ;
     RECT  0.084 22.608 2.365 22.632 ;
     RECT  0.06 22.632 2.365 22.704 ;
     RECT  0.084 22.704 2.365 22.728 ;
     RECT  0.06 22.728 2.365 22.8 ;
     RECT  0.084 22.8 2.365 22.824 ;
     RECT  0.06 22.824 2.365 22.896 ;
     RECT  0.084 22.896 2.365 22.92 ;
     RECT  0.06 22.92 2.365 22.992 ;
     RECT  0.084 22.992 2.365 23.016 ;
     RECT  0.06 23.016 2.365 23.088 ;
     RECT  0.084 23.088 2.365 23.112 ;
     RECT  0.06 23.112 2.365 23.184 ;
     RECT  0.084 23.184 2.365 23.208 ;
     RECT  0.06 23.208 2.365 23.28 ;
     RECT  0.084 23.28 2.365 23.304 ;
     RECT  0.06 23.304 2.365 23.376 ;
     RECT  0.084 23.376 2.365 23.4 ;
     RECT  0.06 23.4 2.365 23.472 ;
     RECT  0.084 23.472 2.365 23.496 ;
     RECT  0.06 23.496 2.365 23.568 ;
     RECT  0.084 23.568 2.365 23.592 ;
     RECT  0.06 23.592 2.365 23.664 ;
     RECT  0.084 23.664 2.365 23.688 ;
     RECT  0.06 23.688 2.365 23.76 ;
     RECT  0.084 23.76 2.365 23.784 ;
     RECT  0.06 23.784 2.365 23.856 ;
     RECT  0.084 23.856 2.365 23.88 ;
     RECT  0.06 23.88 2.365 23.952 ;
     RECT  0.084 23.952 2.365 23.976 ;
     RECT  0.06 23.976 2.365 24.048 ;
     RECT  0.084 24.048 2.365 24.072 ;
     RECT  0.06 24.072 2.365 24.144 ;
     RECT  0.084 24.144 2.365 24.168 ;
     RECT  0.06 24.168 2.365 24.24 ;
     RECT  0.084 24.24 2.365 24.264 ;
     RECT  0.06 24.264 2.365 24.336 ;
     RECT  0.084 24.336 2.365 24.36 ;
     RECT  0.06 24.36 2.365 24.432 ;
     RECT  0.084 24.432 2.365 24.456 ;
     RECT  0.06 24.456 2.365 24.528 ;
     RECT  0.084 24.528 2.365 24.552 ;
     RECT  0.06 24.552 2.365 24.624 ;
     RECT  0.084 24.624 2.365 24.648 ;
     RECT  0.06 24.648 2.365 24.72 ;
     RECT  0.084 24.72 2.365 24.744 ;
     RECT  0.06 24.744 2.365 24.816 ;
     RECT  0.084 24.816 2.365 24.84 ;
     RECT  0.06 24.84 2.365 24.912 ;
     RECT  0.084 24.912 2.365 24.936 ;
     RECT  0.06 24.936 2.365 25.008 ;
     RECT  0.084 25.008 2.365 25.032 ;
     RECT  0.06 25.032 2.365 25.104 ;
     RECT  0.084 25.104 2.365 25.128 ;
     RECT  0.06 25.128 2.365 25.2 ;
     RECT  0.084 25.2 2.365 25.224 ;
     RECT  0.06 25.224 2.365 25.296 ;
     RECT  0.084 25.296 2.365 25.32 ;
     RECT  0.06 25.32 2.365 25.392 ;
     RECT  0.084 25.392 2.365 25.416 ;
     RECT  0.06 25.416 2.365 25.488 ;
     RECT  0.084 25.488 2.365 25.512 ;
     RECT  0.06 25.512 2.365 25.584 ;
     RECT  0.084 25.584 2.365 25.608 ;
     RECT  0.06 25.608 2.365 25.68 ;
     RECT  0.084 25.68 2.365 25.704 ;
     RECT  0.084 3.504 2.408 3.528 ;
     RECT  0.06 3.528 2.408 3.6 ;
     RECT  0.084 3.6 2.408 3.624 ;
     RECT  0.06 3.624 2.408 3.696 ;
     RECT  0.084 3.696 2.408 3.72 ;
     RECT  0.06 3.72 2.408 3.792 ;
     RECT  0.084 3.792 2.408 3.816 ;
     RECT  0.06 3.816 2.408 3.888 ;
     RECT  0.084 3.888 2.408 3.912 ;
     RECT  0.06 3.912 2.408 3.984 ;
     RECT  0.084 3.984 2.408 4.008 ;
     RECT  0.06 4.008 2.408 4.08 ;
     RECT  0.084 4.08 2.408 4.104 ;
     RECT  0.06 4.104 2.408 4.176 ;
     RECT  0.084 4.176 2.408 4.2 ;
     RECT  0.06 4.2 2.408 4.272 ;
     RECT  0.084 4.272 2.408 4.296 ;
     RECT  0.06 4.296 2.408 4.368 ;
     RECT  0.084 4.368 2.408 4.392 ;
     RECT  0.06 4.392 2.408 4.464 ;
     RECT  0.084 4.464 2.408 4.488 ;
     RECT  0.06 4.488 2.408 4.56 ;
     RECT  0.084 4.56 2.408 4.584 ;
     RECT  0.06 4.584 2.408 4.656 ;
     RECT  0.084 4.656 2.408 4.68 ;
     RECT  0.06 4.68 2.408 4.752 ;
     RECT  0.084 4.752 2.408 4.776 ;
     RECT  0.06 4.776 2.408 4.848 ;
     RECT  0.084 4.848 2.408 4.872 ;
     RECT  0.06 4.872 2.408 4.944 ;
     RECT  0.084 4.944 2.408 4.968 ;
     RECT  0.06 4.968 2.408 5.04 ;
     RECT  0.084 5.04 2.408 5.064 ;
     RECT  0.06 5.064 2.408 5.136 ;
     RECT  0.084 5.136 2.408 5.16 ;
     RECT  0.06 5.16 2.408 5.232 ;
     RECT  0.084 5.232 2.408 5.256 ;
     RECT  0.06 5.256 2.408 5.328 ;
     RECT  0.084 5.328 2.408 5.352 ;
     RECT  0.06 5.352 2.408 5.424 ;
     RECT  0.084 5.424 2.408 5.448 ;
     RECT  0.06 5.448 2.408 5.52 ;
     RECT  0.084 5.52 2.408 5.544 ;
     RECT  0.06 5.544 2.408 5.616 ;
     RECT  0.084 5.616 2.408 5.64 ;
     RECT  0.06 5.64 2.408 5.712 ;
     RECT  0.084 5.712 2.408 5.736 ;
     RECT  0.06 5.736 2.408 5.808 ;
     RECT  0.084 5.808 2.408 5.832 ;
     RECT  0.06 5.832 2.408 5.904 ;
     RECT  0.084 5.904 2.408 5.928 ;
     RECT  0.06 5.928 2.408 6 ;
     RECT  0.084 6 2.408 6.024 ;
     RECT  0.06 6.024 2.408 6.096 ;
     RECT  0.084 6.096 2.408 6.12 ;
     RECT  0.06 6.12 2.408 6.192 ;
     RECT  0.084 6.192 2.408 6.216 ;
     RECT  0.06 6.216 2.408 6.288 ;
     RECT  0.084 6.288 2.408 6.312 ;
     RECT  0.06 6.312 2.408 6.384 ;
     RECT  0.084 6.384 2.408 6.408 ;
     RECT  0.06 6.408 2.408 6.48 ;
     RECT  0.084 6.48 2.408 6.504 ;
     RECT  0.06 6.504 2.408 6.576 ;
     RECT  0.084 6.576 2.408 6.6 ;
     RECT  0.06 6.6 2.408 6.672 ;
     RECT  0.084 6.672 2.408 6.696 ;
     RECT  0.06 6.696 2.408 6.768 ;
     RECT  0.084 6.768 2.408 6.792 ;
     RECT  0.06 6.792 2.408 6.864 ;
     RECT  0.084 6.864 2.408 6.888 ;
     RECT  0.06 6.888 2.408 6.96 ;
     RECT  0.084 6.96 2.408 6.984 ;
     RECT  0.06 6.984 2.408 7.056 ;
     RECT  0.084 7.056 2.408 7.08 ;
     RECT  0.06 7.08 2.408 7.152 ;
     RECT  0.084 7.152 2.408 7.176 ;
     RECT  0.06 7.176 2.408 7.248 ;
     RECT  0.084 7.248 2.408 7.272 ;
     RECT  0.06 7.272 2.408 7.344 ;
     RECT  0.084 7.344 2.408 7.368 ;
     RECT  0.06 7.368 2.408 7.44 ;
     RECT  0.084 7.44 2.408 7.464 ;
     RECT  0.06 7.464 2.408 7.536 ;
     RECT  0.084 7.536 2.408 7.56 ;
     RECT  0.06 7.56 2.408 7.632 ;
     RECT  0.084 7.632 2.408 7.656 ;
     RECT  0.06 7.656 2.408 7.728 ;
     RECT  0.084 7.728 2.408 7.752 ;
     RECT  0.06 7.752 2.408 7.824 ;
     RECT  0.084 7.824 2.408 7.848 ;
     RECT  0.06 7.848 2.408 7.92 ;
     RECT  0.084 7.92 2.408 7.944 ;
     RECT  0.06 7.944 2.408 8.016 ;
     RECT  0.084 8.016 2.408 8.04 ;
     RECT  0.06 8.04 2.408 8.112 ;
     RECT  0.084 8.112 2.408 8.136 ;
     RECT  0.06 8.136 2.408 8.208 ;
     RECT  0.084 8.208 2.408 8.232 ;
     RECT  0.06 8.232 2.408 8.304 ;
     RECT  0.084 8.304 2.408 8.328 ;
     RECT  0.06 8.328 2.408 8.4 ;
     RECT  0.084 8.4 2.408 8.424 ;
     RECT  0.06 8.424 2.408 8.496 ;
     RECT  0.084 8.496 2.408 8.52 ;
     RECT  0.06 8.52 2.408 8.592 ;
     RECT  0.084 8.592 2.408 8.616 ;
     RECT  0.06 8.616 2.408 8.688 ;
     RECT  0.084 8.688 2.408 8.712 ;
     RECT  0.06 8.712 2.408 8.784 ;
     RECT  0.084 8.784 2.408 8.808 ;
     RECT  0.06 8.808 2.408 8.88 ;
     RECT  0.084 8.88 2.408 8.904 ;
     RECT  0.06 8.904 2.408 8.976 ;
     RECT  0.084 8.976 2.408 9 ;
     RECT  0.06 9 2.408 9.072 ;
     RECT  0.084 9.072 2.408 9.096 ;
     RECT  0.06 9.096 2.408 9.168 ;
     RECT  0.084 9.168 2.408 9.192 ;
     RECT  0.06 9.192 2.408 9.264 ;
     RECT  0.084 9.264 2.408 9.288 ;
     RECT  0.06 9.288 2.408 9.36 ;
     RECT  0.084 9.36 2.408 9.384 ;
     RECT  0.06 9.384 2.408 9.456 ;
     RECT  0.084 9.456 2.408 9.48 ;
     RECT  0.06 9.48 2.408 9.552 ;
     RECT  0.084 9.552 2.408 9.576 ;
     RECT  2.365 16.32 2.408 25.704 ;
     RECT  2.365 29.616 2.408 30.6 ;
     RECT  1.181 33.744 2.408 44.904 ;
     RECT  2.408 2.148 2.512 49.692 ;
     RECT  2.512 2.418 2.704 49.422 ;
     RECT  2.704 15.552 2.819 46.152 ;
     RECT  2.704 48.48 3.593 48.504 ;
     RECT  2.704 3.6 3.769 11.448 ;
     RECT  2.819 15.552 3.841 27.96 ;
     RECT  2.819 29.616 3.841 46.152 ;
     RECT  3.697 14.448 3.949 14.472 ;
     RECT  3.841 15.552 3.949 46.152 ;
     RECT  2.704 13.008 4.021 13.368 ;
     RECT  3.949 14.448 4.021 46.152 ;
     RECT  4.021 13.008 4.093 46.152 ;
     RECT  3.877 48.432 4.093 48.456 ;
     RECT  4.093 47.952 4.129 48.456 ;
     RECT  4.093 13.008 4.237 46.2 ;
     RECT  4.129 47.856 4.309 48.456 ;
     RECT  3.769 2.88 4.381 11.448 ;
     RECT  4.309 47.376 4.489 48.456 ;
     RECT  4.237 12.48 4.501 46.2 ;
     RECT  4.489 47.328 4.501 48.456 ;
     RECT  4.381 2.256 4.669 11.448 ;
     RECT  4.501 12.48 4.669 48.456 ;
     RECT  4.669 2.256 4.957 48.456 ;
     RECT  4.957 2.256 5.108 49.032 ;
     RECT  5.108 2.148 5.212 49.692 ;
     RECT  5.212 2.256 5.404 49.422 ;
     RECT  5.404 2.256 5.501 48.984 ;
     RECT  5.501 2.88 5.555 48.984 ;
     RECT  5.555 31.92 5.753 48.984 ;
     RECT  5.753 31.92 6.149 48.792 ;
     RECT  5.555 2.88 6.541 30.888 ;
     RECT  6.149 31.92 6.541 42.888 ;
     RECT  6.541 2.88 6.577 42.888 ;
     RECT  6.577 2.784 7.333 42.888 ;
     RECT  7.333 2.544 7.34 42.888 ;
     RECT  6.149 43.872 7.34 48.792 ;
     RECT  7.34 2.544 7.808 48.792 ;
     RECT  7.808 2.148 7.912 49.692 ;
     RECT  7.912 2.256 8.104 49.422 ;
     RECT  8.104 2.256 8.381 48.792 ;
     RECT  8.381 2.256 9.137 48.168 ;
     RECT  9.137 14.928 9.385 48.168 ;
     RECT  9.137 2.256 9.461 13.704 ;
     RECT  9.461 2.544 10.508 13.704 ;
     RECT  9.385 14.928 10.508 48.888 ;
     RECT  10.508 2.148 10.612 49.692 ;
     RECT  10.612 2.256 10.804 49.56 ;
     RECT  10.804 2.256 11.405 13.848 ;
     RECT  10.804 14.976 11.449 49.56 ;
     RECT  11.405 2.592 11.905 13.848 ;
     RECT  11.449 14.976 11.905 49.32 ;
     RECT  11.905 2.592 13.208 49.32 ;
     RECT  13.208 2.148 13.312 49.692 ;
     RECT  13.312 2.352 13.504 49.422 ;
     RECT  13.504 49.296 13.853 49.32 ;
     RECT  13.504 2.352 14.609 48.264 ;
     RECT  14.609 14.256 15.781 48.264 ;
     RECT  14.609 2.352 15.908 13.08 ;
     RECT  15.781 14.16 15.908 48.264 ;
     RECT  14.821 49.344 15.908 49.368 ;
     RECT  15.908 2.148 16.012 49.692 ;
     RECT  16.012 2.256 16.204 49.422 ;
     RECT  16.204 2.256 16.553 49.272 ;
     RECT  16.553 2.256 17.173 48.264 ;
     RECT  17.173 2.256 17.201 32.856 ;
     RECT  16.553 49.248 17.237 49.272 ;
     RECT  17.173 34.128 18.229 48.264 ;
     RECT  17.201 3.36 18.385 32.856 ;
     RECT  17.201 2.256 18.493 2.28 ;
     RECT  18.385 3.36 18.493 33.048 ;
     RECT  18.229 34.128 18.493 48.36 ;
     RECT  18.493 2.256 18.608 48.36 ;
     RECT  18.565 49.488 18.608 49.512 ;
     RECT  18.608 2.148 18.712 49.692 ;
     RECT  18.712 2.418 18.904 49.512 ;
     RECT  18.904 2.832 19.379 48.024 ;
     RECT  19.379 3.888 19.469 48.024 ;
     RECT  18.904 49.008 19.757 49.512 ;
     RECT  19.379 2.832 19.901 2.856 ;
     RECT  19.469 3.888 19.937 47.688 ;
     RECT  19.937 3.888 20.117 29.64 ;
     RECT  20.117 3.888 20.54 29.592 ;
     RECT  19.757 49.488 20.905 49.512 ;
     RECT  20.905 49.008 20.977 49.512 ;
     RECT  20.54 3.36 21.121 29.592 ;
     RECT  21.121 2.784 21.308 29.592 ;
     RECT  19.937 30.672 21.308 47.688 ;
     RECT  20.977 48.912 21.308 49.512 ;
     RECT  21.308 2.148 21.412 49.692 ;
     RECT  21.412 2.304 21.604 49.512 ;
     RECT  21.604 49.488 22.025 49.512 ;
     RECT  21.604 2.304 22.169 3.096 ;
     RECT  22.169 2.88 22.421 3.096 ;
     RECT  21.604 4.08 22.777 14.184 ;
     RECT  21.604 15.264 22.777 48.024 ;
     RECT  22.421 2.88 22.889 2.904 ;
     RECT  22.777 4.08 23.497 48.024 ;
     RECT  23.857 2.592 23.965 2.616 ;
     RECT  23.497 3.84 23.965 48.024 ;
     RECT  23.965 2.592 24.008 48.024 ;
     RECT  23.425 49.488 24.008 49.512 ;
     RECT  24.008 2.148 24.112 49.692 ;
     RECT  24.112 2.418 24.304 49.512 ;
     RECT  24.304 3.84 24.581 47.928 ;
     RECT  24.304 49.488 24.797 49.512 ;
     RECT  24.304 2.592 24.941 2.856 ;
     RECT  24.581 3.84 25.621 47.688 ;
     RECT  24.941 2.832 25.868 2.856 ;
     RECT  25.621 3.84 25.868 47.928 ;
     RECT  25.868 2.832 25.909 47.928 ;
     RECT  25.909 2.688 26.341 47.928 ;
     RECT  26.341 2.592 26.708 47.928 ;
     RECT  26.708 2.148 26.812 49.692 ;
     RECT  26.812 2.418 27.004 49.422 ;
     RECT  27.004 2.592 27.425 33.72 ;
     RECT  27.425 2.784 28.069 33.72 ;
     RECT  27.004 34.992 28.069 48.552 ;
     RECT  28.069 2.784 28.393 48.552 ;
     RECT  28.393 2.304 28.969 48.552 ;
     RECT  28.969 2.304 29.041 48.792 ;
     RECT  29.041 2.304 29.408 49.032 ;
     RECT  29.408 2.148 29.512 49.692 ;
     RECT  29.512 2.304 29.704 49.422 ;
     RECT  29.704 2.304 29.843 49.272 ;
     RECT  29.843 2.304 30.233 34.2 ;
     RECT  29.843 35.232 30.901 49.272 ;
     RECT  30.233 2.304 30.989 33.624 ;
     RECT  30.901 34.608 30.989 49.272 ;
     RECT  30.989 35.232 31.097 49.272 ;
     RECT  30.989 2.928 31.633 33.624 ;
     RECT  31.633 2.928 31.993 34.104 ;
     RECT  31.097 35.232 31.993 49.224 ;
     RECT  31.993 2.928 32.108 49.224 ;
     RECT  32.108 2.148 32.212 49.692 ;
     RECT  32.212 2.418 32.404 49.422 ;
     RECT  32.404 30.144 32.501 47.976 ;
     RECT  32.501 30.144 32.531 42.168 ;
     RECT  32.501 43.2 32.572 47.976 ;
     RECT  32.531 30.144 32.573 41.976 ;
     RECT  32.572 43.296 32.681 47.976 ;
     RECT  32.404 48.96 32.717 48.984 ;
     RECT  32.573 30.144 32.753 35.256 ;
     RECT  32.404 4.128 32.771 28.728 ;
     RECT  32.771 4.128 32.789 15.816 ;
     RECT  32.573 36.528 32.789 41.976 ;
     RECT  32.789 5.664 33.005 15.816 ;
     RECT  32.753 30.432 33.041 35.256 ;
     RECT  33.005 5.76 33.077 15.816 ;
     RECT  32.771 16.896 33.113 28.728 ;
     RECT  33.041 30.432 33.113 30.696 ;
     RECT  32.789 36.624 33.113 41.976 ;
     RECT  33.113 16.896 33.149 21.144 ;
     RECT  33.113 30.576 33.257 30.6 ;
     RECT  32.681 43.44 33.329 47.976 ;
     RECT  33.077 6.144 33.401 15.816 ;
     RECT  33.113 36.624 33.401 37.608 ;
     RECT  32.789 4.128 33.437 4.536 ;
     RECT  33.149 16.896 33.473 18.504 ;
     RECT  33.149 19.536 33.473 21.144 ;
     RECT  33.113 38.784 33.473 41.976 ;
     RECT  33.329 44.592 33.505 47.976 ;
     RECT  33.401 37.392 33.509 37.608 ;
     RECT  33.401 6.144 33.653 13.368 ;
     RECT  33.113 22.32 33.653 28.728 ;
     RECT  33.473 38.784 33.653 39.288 ;
     RECT  33.041 31.728 33.689 35.256 ;
     RECT  33.653 6.144 33.725 12.888 ;
     RECT  33.401 14.64 33.761 15.816 ;
     RECT  33.509 37.392 33.761 37.416 ;
     RECT  33.689 31.728 33.833 34.152 ;
     RECT  33.473 40.32 33.833 41.976 ;
     RECT  33.761 15.264 33.941 15.816 ;
     RECT  33.725 7.68 33.977 12.888 ;
     RECT  33.833 31.728 33.977 33.144 ;
     RECT  33.473 19.536 34.229 20.952 ;
     RECT  33.977 31.728 34.229 32.856 ;
     RECT  33.725 6.144 34.729 6.696 ;
     RECT  33.977 7.68 34.729 12.456 ;
     RECT  34.229 19.92 34.765 20.952 ;
     RECT  33.329 43.44 34.765 43.464 ;
     RECT  33.505 44.592 34.765 48.264 ;
     RECT  33.653 38.784 35.017 39.096 ;
     RECT  33.833 40.32 35.017 41.928 ;
     RECT  34.765 19.92 35.089 21.096 ;
     RECT  33.653 22.32 35.089 28.296 ;
     RECT  33.833 34.128 35.305 34.152 ;
     RECT  35.017 38.784 35.305 41.928 ;
     RECT  34.729 6.144 35.341 12.456 ;
     RECT  34.229 31.728 35.341 32.52 ;
     RECT  34.765 43.44 35.341 48.264 ;
     RECT  35.341 6.144 35.377 12.552 ;
     RECT  35.305 38.784 35.629 42.024 ;
     RECT  35.341 43.152 35.629 48.264 ;
     RECT  35.377 6.144 35.881 12.84 ;
     RECT  35.089 19.92 35.917 28.296 ;
     RECT  35.341 31.728 35.917 32.616 ;
     RECT  35.305 34.032 35.917 34.152 ;
     RECT  35.917 19.92 35.989 28.872 ;
     RECT  35.989 19.92 36.025 28.968 ;
     RECT  33.473 16.896 36.245 18.024 ;
     RECT  35.881 6.144 36.425 12.936 ;
     RECT  35.629 38.784 36.425 48.264 ;
     RECT  33.941 15.552 36.461 15.816 ;
     RECT  36.245 16.896 36.515 16.92 ;
     RECT  36.461 15.792 36.563 15.816 ;
     RECT  35.917 31.728 36.569 34.152 ;
     RECT  36.425 6.336 36.605 12.936 ;
     RECT  36.425 39.024 36.605 48.264 ;
     RECT  36.245 18 36.611 18.024 ;
     RECT  36.605 6.624 36.641 6.864 ;
     RECT  36.605 6.864 36.636 6.888 ;
     RECT  36.605 6.888 36.641 6.96 ;
     RECT  36.605 6.96 36.636 6.984 ;
     RECT  36.605 6.984 36.641 7.056 ;
     RECT  36.605 7.056 36.636 7.08 ;
     RECT  36.605 7.08 36.641 7.152 ;
     RECT  36.605 7.152 36.636 7.176 ;
     RECT  36.605 7.176 36.641 7.248 ;
     RECT  36.605 7.248 36.636 7.272 ;
     RECT  36.605 7.272 36.641 7.344 ;
     RECT  36.605 7.344 36.636 7.368 ;
     RECT  36.605 7.368 36.641 7.44 ;
     RECT  36.605 7.44 36.636 7.464 ;
     RECT  36.605 7.464 36.641 7.536 ;
     RECT  36.605 7.536 36.636 7.56 ;
     RECT  36.605 7.56 36.641 7.632 ;
     RECT  36.605 7.632 36.636 7.656 ;
     RECT  36.605 7.656 36.641 7.728 ;
     RECT  36.605 7.728 36.636 7.752 ;
     RECT  36.605 7.752 36.641 7.824 ;
     RECT  36.605 7.824 36.636 7.848 ;
     RECT  36.605 7.848 36.641 7.92 ;
     RECT  36.605 7.92 36.636 7.944 ;
     RECT  36.605 7.944 36.641 8.016 ;
     RECT  36.605 8.016 36.636 8.04 ;
     RECT  36.605 8.04 36.641 8.112 ;
     RECT  36.605 8.112 36.636 8.136 ;
     RECT  36.605 8.136 36.641 8.208 ;
     RECT  36.605 8.208 36.636 8.232 ;
     RECT  36.605 8.232 36.641 8.304 ;
     RECT  36.605 8.304 36.636 8.328 ;
     RECT  36.605 8.328 36.641 8.4 ;
     RECT  36.605 8.4 36.636 8.424 ;
     RECT  36.605 8.424 36.641 8.496 ;
     RECT  36.605 8.496 36.636 8.52 ;
     RECT  36.605 8.52 36.641 8.592 ;
     RECT  36.605 8.592 36.636 8.616 ;
     RECT  36.605 8.616 36.641 8.688 ;
     RECT  36.605 8.688 36.636 8.712 ;
     RECT  36.605 8.712 36.641 8.784 ;
     RECT  36.605 8.784 36.636 8.808 ;
     RECT  36.605 8.808 36.641 8.88 ;
     RECT  36.605 8.88 36.636 8.904 ;
     RECT  36.605 8.904 36.641 8.976 ;
     RECT  36.605 8.976 36.636 9 ;
     RECT  36.605 9 36.641 9.072 ;
     RECT  36.605 9.072 36.636 9.096 ;
     RECT  36.605 9.096 36.641 9.168 ;
     RECT  36.605 9.168 36.636 9.192 ;
     RECT  36.605 9.192 36.641 9.264 ;
     RECT  36.605 9.264 36.636 9.288 ;
     RECT  36.605 9.288 36.641 9.36 ;
     RECT  36.605 9.36 36.636 9.384 ;
     RECT  36.605 9.384 36.641 9.456 ;
     RECT  36.605 9.456 36.636 9.48 ;
     RECT  36.605 9.48 36.641 9.552 ;
     RECT  36.605 9.552 36.636 9.576 ;
     RECT  36.605 9.576 36.641 9.648 ;
     RECT  36.605 9.648 36.636 9.672 ;
     RECT  36.605 9.672 36.641 9.744 ;
     RECT  36.605 9.744 36.636 9.768 ;
     RECT  36.605 9.768 36.641 9.84 ;
     RECT  36.605 9.84 36.636 9.864 ;
     RECT  36.605 9.864 36.641 9.936 ;
     RECT  36.605 9.936 36.636 9.96 ;
     RECT  36.605 9.96 36.641 10.032 ;
     RECT  36.605 10.032 36.636 10.056 ;
     RECT  36.605 10.056 36.641 10.128 ;
     RECT  36.605 10.128 36.636 10.152 ;
     RECT  36.605 10.152 36.641 10.224 ;
     RECT  36.605 10.224 36.636 10.248 ;
     RECT  36.605 10.248 36.641 10.32 ;
     RECT  36.605 10.32 36.636 10.344 ;
     RECT  36.605 10.344 36.641 10.416 ;
     RECT  36.605 10.416 36.636 10.44 ;
     RECT  36.605 10.44 36.641 10.512 ;
     RECT  36.605 10.512 36.636 10.536 ;
     RECT  36.605 10.536 36.641 10.608 ;
     RECT  36.605 10.608 36.636 10.632 ;
     RECT  36.605 10.632 36.641 10.704 ;
     RECT  36.605 10.704 36.636 10.728 ;
     RECT  36.605 10.728 36.641 10.8 ;
     RECT  36.605 10.8 36.636 10.824 ;
     RECT  36.605 10.824 36.641 10.896 ;
     RECT  36.605 10.896 36.636 10.92 ;
     RECT  36.605 10.92 36.641 10.992 ;
     RECT  36.605 10.992 36.636 11.016 ;
     RECT  36.605 11.016 36.641 11.088 ;
     RECT  36.605 11.088 36.636 11.112 ;
     RECT  36.605 11.112 36.641 11.184 ;
     RECT  36.605 11.184 36.636 11.208 ;
     RECT  36.605 11.208 36.641 11.28 ;
     RECT  36.605 11.28 36.636 11.304 ;
     RECT  36.605 11.304 36.641 11.376 ;
     RECT  36.605 11.376 36.636 11.4 ;
     RECT  36.605 11.4 36.641 11.472 ;
     RECT  36.605 11.472 36.636 11.496 ;
     RECT  36.605 11.496 36.641 11.568 ;
     RECT  36.605 11.568 36.636 11.592 ;
     RECT  36.605 11.592 36.641 11.664 ;
     RECT  36.605 11.664 36.636 11.688 ;
     RECT  36.605 11.688 36.641 11.76 ;
     RECT  36.605 11.76 36.636 11.784 ;
     RECT  36.605 11.784 36.641 11.856 ;
     RECT  36.605 11.856 36.636 11.88 ;
     RECT  36.605 11.88 36.641 11.952 ;
     RECT  36.605 11.952 36.636 11.976 ;
     RECT  36.605 11.976 36.641 12.048 ;
     RECT  36.605 12.048 36.636 12.072 ;
     RECT  36.605 12.072 36.641 12.144 ;
     RECT  36.605 12.144 36.636 12.168 ;
     RECT  36.605 12.168 36.641 12.24 ;
     RECT  36.605 12.24 36.636 12.264 ;
     RECT  36.605 12.264 36.641 12.336 ;
     RECT  36.605 12.336 36.636 12.36 ;
     RECT  36.605 12.36 36.641 12.432 ;
     RECT  36.605 12.432 36.636 12.456 ;
     RECT  36.605 12.456 36.641 12.528 ;
     RECT  36.605 12.528 36.636 12.552 ;
     RECT  36.605 12.552 36.641 12.624 ;
     RECT  36.605 12.624 36.636 12.648 ;
     RECT  36.605 12.648 36.641 12.72 ;
     RECT  36.605 12.72 36.636 12.744 ;
     RECT  36.605 12.744 36.641 12.816 ;
     RECT  36.605 12.816 36.636 12.84 ;
     RECT  36.605 12.84 36.641 12.912 ;
     RECT  36.605 12.912 36.636 12.936 ;
     RECT  33.437 4.128 36.677 4.152 ;
     RECT  36.641 6.888 36.684 6.96 ;
     RECT  36.641 6.984 36.684 7.056 ;
     RECT  36.641 7.08 36.684 7.152 ;
     RECT  36.641 7.176 36.684 7.248 ;
     RECT  36.641 7.272 36.684 7.344 ;
     RECT  36.641 7.368 36.684 7.44 ;
     RECT  36.641 7.464 36.684 7.536 ;
     RECT  36.641 7.56 36.684 7.632 ;
     RECT  36.641 7.656 36.684 7.728 ;
     RECT  36.641 7.752 36.684 7.824 ;
     RECT  36.641 7.848 36.684 7.92 ;
     RECT  36.641 7.944 36.684 8.016 ;
     RECT  36.641 8.04 36.684 8.112 ;
     RECT  36.641 8.136 36.684 8.208 ;
     RECT  36.641 8.232 36.684 8.304 ;
     RECT  36.641 8.328 36.684 8.4 ;
     RECT  36.641 8.424 36.684 8.496 ;
     RECT  36.641 8.52 36.684 8.592 ;
     RECT  36.641 8.616 36.684 8.688 ;
     RECT  36.641 8.712 36.684 8.784 ;
     RECT  36.641 8.808 36.684 8.88 ;
     RECT  36.641 8.904 36.684 8.976 ;
     RECT  36.641 9 36.684 9.072 ;
     RECT  36.641 9.096 36.684 9.168 ;
     RECT  36.641 9.192 36.684 9.264 ;
     RECT  36.641 9.288 36.684 9.36 ;
     RECT  36.641 9.384 36.684 9.456 ;
     RECT  36.641 9.48 36.684 9.552 ;
     RECT  36.641 9.576 36.684 9.648 ;
     RECT  36.641 9.672 36.684 9.744 ;
     RECT  36.641 9.768 36.684 9.84 ;
     RECT  36.641 9.864 36.684 9.936 ;
     RECT  36.641 9.96 36.684 10.032 ;
     RECT  36.641 10.056 36.684 10.128 ;
     RECT  36.641 10.152 36.684 10.224 ;
     RECT  36.641 10.248 36.684 10.32 ;
     RECT  36.641 10.344 36.684 10.416 ;
     RECT  36.641 10.44 36.684 10.512 ;
     RECT  36.641 10.536 36.684 10.608 ;
     RECT  36.641 10.632 36.684 10.704 ;
     RECT  36.641 10.728 36.684 10.8 ;
     RECT  36.641 10.824 36.684 10.896 ;
     RECT  36.641 10.92 36.684 10.992 ;
     RECT  36.641 11.016 36.684 11.088 ;
     RECT  36.641 11.112 36.684 11.184 ;
     RECT  36.641 11.208 36.684 11.28 ;
     RECT  36.641 11.304 36.684 11.376 ;
     RECT  36.641 11.4 36.684 11.472 ;
     RECT  36.641 11.496 36.684 11.568 ;
     RECT  36.641 11.592 36.684 11.664 ;
     RECT  36.641 11.688 36.684 11.76 ;
     RECT  36.641 11.784 36.684 11.856 ;
     RECT  36.641 11.88 36.684 11.952 ;
     RECT  36.641 11.976 36.684 12.048 ;
     RECT  36.641 12.072 36.684 12.144 ;
     RECT  36.641 12.168 36.684 12.24 ;
     RECT  36.641 12.264 36.684 12.336 ;
     RECT  36.641 12.36 36.684 12.432 ;
     RECT  36.641 12.456 36.684 12.528 ;
     RECT  36.641 12.552 36.684 12.624 ;
     RECT  36.641 12.648 36.684 12.72 ;
     RECT  36.641 12.744 36.684 12.816 ;
     RECT  36.641 12.84 36.684 12.912 ;
     RECT  36.025 19.92 36.636 19.944 ;
     RECT  36.025 19.944 36.684 20.016 ;
     RECT  36.025 20.016 36.636 20.04 ;
     RECT  36.025 20.04 36.684 20.112 ;
     RECT  36.025 20.112 36.636 20.136 ;
     RECT  36.025 20.136 36.684 20.208 ;
     RECT  36.025 20.208 36.636 20.232 ;
     RECT  36.025 20.232 36.684 20.304 ;
     RECT  36.025 20.304 36.636 20.328 ;
     RECT  36.025 20.328 36.684 20.4 ;
     RECT  36.025 20.4 36.636 20.424 ;
     RECT  36.025 20.424 36.684 20.496 ;
     RECT  36.025 20.496 36.636 20.52 ;
     RECT  36.025 20.52 36.684 20.592 ;
     RECT  36.025 20.592 36.636 20.616 ;
     RECT  36.025 20.616 36.684 20.688 ;
     RECT  36.025 20.688 36.636 20.712 ;
     RECT  36.025 20.712 36.684 20.784 ;
     RECT  36.025 20.784 36.636 20.808 ;
     RECT  36.025 20.808 36.684 20.88 ;
     RECT  36.025 20.88 36.636 20.904 ;
     RECT  36.025 20.904 36.684 20.976 ;
     RECT  36.025 20.976 36.636 21 ;
     RECT  36.025 21 36.684 21.072 ;
     RECT  36.025 21.072 36.636 21.096 ;
     RECT  36.025 21.096 36.684 21.168 ;
     RECT  36.025 21.168 36.636 21.192 ;
     RECT  36.025 21.192 36.684 21.264 ;
     RECT  36.025 21.264 36.636 21.288 ;
     RECT  36.025 21.288 36.684 21.36 ;
     RECT  36.025 21.36 36.636 21.384 ;
     RECT  36.025 21.384 36.684 21.456 ;
     RECT  36.025 21.456 36.636 21.48 ;
     RECT  36.025 21.48 36.684 21.552 ;
     RECT  36.025 21.552 36.636 21.576 ;
     RECT  36.025 21.576 36.684 21.648 ;
     RECT  36.025 21.648 36.636 21.672 ;
     RECT  36.025 21.672 36.684 21.744 ;
     RECT  36.025 21.744 36.636 21.768 ;
     RECT  36.025 21.768 36.684 21.84 ;
     RECT  36.025 21.84 36.636 21.864 ;
     RECT  36.025 21.864 36.684 21.936 ;
     RECT  36.025 21.936 36.636 21.96 ;
     RECT  36.025 21.96 36.684 22.032 ;
     RECT  36.025 22.032 36.636 22.056 ;
     RECT  36.025 22.056 36.684 22.128 ;
     RECT  36.025 22.128 36.636 22.152 ;
     RECT  36.025 22.152 36.684 22.224 ;
     RECT  36.025 22.224 36.636 22.248 ;
     RECT  36.025 22.248 36.684 22.32 ;
     RECT  36.025 22.32 36.636 22.344 ;
     RECT  36.025 22.344 36.684 22.416 ;
     RECT  36.025 22.416 36.636 22.44 ;
     RECT  36.025 22.44 36.684 22.512 ;
     RECT  36.025 22.512 36.636 22.536 ;
     RECT  36.025 22.536 36.684 22.608 ;
     RECT  36.025 22.608 36.636 22.632 ;
     RECT  36.025 22.632 36.684 22.704 ;
     RECT  36.025 22.704 36.636 22.728 ;
     RECT  36.025 22.728 36.684 22.8 ;
     RECT  36.025 22.8 36.636 22.824 ;
     RECT  36.025 22.824 36.684 22.896 ;
     RECT  36.025 22.896 36.636 22.92 ;
     RECT  36.025 22.92 36.684 22.992 ;
     RECT  36.025 22.992 36.636 23.016 ;
     RECT  36.025 23.016 36.684 23.088 ;
     RECT  36.025 23.088 36.636 23.112 ;
     RECT  36.025 23.112 36.684 23.184 ;
     RECT  36.025 23.184 36.636 23.208 ;
     RECT  36.025 23.208 36.684 23.28 ;
     RECT  36.025 23.28 36.636 23.304 ;
     RECT  36.025 23.304 36.684 23.376 ;
     RECT  36.025 23.376 36.636 23.4 ;
     RECT  36.025 23.4 36.684 23.472 ;
     RECT  36.025 23.472 36.636 23.496 ;
     RECT  36.025 23.496 36.684 23.568 ;
     RECT  36.025 23.568 36.636 23.592 ;
     RECT  36.025 23.592 36.684 23.664 ;
     RECT  36.025 23.664 36.636 23.688 ;
     RECT  36.025 23.688 36.684 23.76 ;
     RECT  36.025 23.76 36.636 23.784 ;
     RECT  36.025 23.784 36.684 23.856 ;
     RECT  36.025 23.856 36.636 23.88 ;
     RECT  36.025 23.88 36.684 23.952 ;
     RECT  36.025 23.952 36.636 23.976 ;
     RECT  36.025 23.976 36.684 24.048 ;
     RECT  36.025 24.048 36.636 24.072 ;
     RECT  36.025 24.072 36.684 24.144 ;
     RECT  36.025 24.144 36.636 24.168 ;
     RECT  36.025 24.168 36.684 24.24 ;
     RECT  36.025 24.24 36.636 24.264 ;
     RECT  36.025 24.264 36.684 24.336 ;
     RECT  36.025 24.336 36.636 24.36 ;
     RECT  36.025 24.36 36.684 24.432 ;
     RECT  36.025 24.432 36.636 24.456 ;
     RECT  36.025 24.456 36.684 24.528 ;
     RECT  36.025 24.528 36.636 24.552 ;
     RECT  36.025 24.552 36.684 24.624 ;
     RECT  36.025 24.624 36.636 24.648 ;
     RECT  36.025 24.648 36.684 24.72 ;
     RECT  36.025 24.72 36.636 24.744 ;
     RECT  36.025 24.744 36.684 24.816 ;
     RECT  36.025 24.816 36.636 24.84 ;
     RECT  36.025 24.84 36.684 24.912 ;
     RECT  36.025 24.912 36.636 24.936 ;
     RECT  36.025 24.936 36.684 25.008 ;
     RECT  36.025 25.008 36.636 25.032 ;
     RECT  36.025 25.032 36.684 25.104 ;
     RECT  36.025 25.104 36.636 25.128 ;
     RECT  36.025 25.128 36.684 25.2 ;
     RECT  36.025 25.2 36.636 25.224 ;
     RECT  36.025 25.224 36.684 25.296 ;
     RECT  36.025 25.296 36.636 25.32 ;
     RECT  36.025 25.32 36.684 25.392 ;
     RECT  36.025 25.392 36.636 25.416 ;
     RECT  36.025 25.416 36.684 25.488 ;
     RECT  36.025 25.488 36.636 25.512 ;
     RECT  36.025 25.512 36.684 25.584 ;
     RECT  36.025 25.584 36.636 25.608 ;
     RECT  36.025 25.608 36.684 25.68 ;
     RECT  36.025 25.68 36.636 25.704 ;
     RECT  36.025 25.704 36.684 25.776 ;
     RECT  36.025 25.776 36.636 25.8 ;
     RECT  36.025 25.8 36.684 25.872 ;
     RECT  36.025 25.872 36.636 25.896 ;
     RECT  36.025 25.896 36.684 25.968 ;
     RECT  36.025 25.968 36.636 25.992 ;
     RECT  36.025 25.992 36.684 26.064 ;
     RECT  36.025 26.064 36.636 26.088 ;
     RECT  36.025 26.088 36.684 26.16 ;
     RECT  36.025 26.16 36.636 26.184 ;
     RECT  36.025 26.184 36.684 26.256 ;
     RECT  36.025 26.256 36.636 26.28 ;
     RECT  36.025 26.28 36.684 26.352 ;
     RECT  36.025 26.352 36.636 26.376 ;
     RECT  36.025 26.376 36.684 26.448 ;
     RECT  36.025 26.448 36.636 26.472 ;
     RECT  36.025 26.472 36.684 26.544 ;
     RECT  36.025 26.544 36.636 26.568 ;
     RECT  36.025 26.568 36.684 26.64 ;
     RECT  36.025 26.64 36.636 26.664 ;
     RECT  36.025 26.664 36.684 26.736 ;
     RECT  36.025 26.736 36.636 26.76 ;
     RECT  36.025 26.76 36.684 26.832 ;
     RECT  36.025 26.832 36.636 26.856 ;
     RECT  36.025 26.856 36.684 26.928 ;
     RECT  36.025 26.928 36.636 26.952 ;
     RECT  36.025 26.952 36.684 27.024 ;
     RECT  36.025 27.024 36.636 27.048 ;
     RECT  36.025 27.048 36.684 27.12 ;
     RECT  36.025 27.12 36.636 27.144 ;
     RECT  36.025 27.144 36.684 27.216 ;
     RECT  36.025 27.216 36.636 27.24 ;
     RECT  36.025 27.24 36.684 27.312 ;
     RECT  36.025 27.312 36.636 27.336 ;
     RECT  36.025 27.336 36.684 27.408 ;
     RECT  36.025 27.408 36.636 27.432 ;
     RECT  36.025 27.432 36.684 27.504 ;
     RECT  36.025 27.504 36.636 27.528 ;
     RECT  36.025 27.528 36.684 27.6 ;
     RECT  36.025 27.6 36.636 27.624 ;
     RECT  36.025 27.624 36.684 27.696 ;
     RECT  36.025 27.696 36.636 27.72 ;
     RECT  36.025 27.72 36.684 27.792 ;
     RECT  36.025 27.792 36.636 27.816 ;
     RECT  36.025 27.816 36.684 27.888 ;
     RECT  36.025 27.888 36.636 27.912 ;
     RECT  36.025 27.912 36.684 27.984 ;
     RECT  36.025 27.984 36.636 28.008 ;
     RECT  36.025 28.008 36.684 28.08 ;
     RECT  36.025 28.08 36.636 28.104 ;
     RECT  36.025 28.104 36.684 28.176 ;
     RECT  36.025 28.176 36.636 28.2 ;
     RECT  36.025 28.2 36.684 28.272 ;
     RECT  36.025 28.272 36.636 28.296 ;
     RECT  36.025 28.296 36.684 28.368 ;
     RECT  36.025 28.368 36.636 28.392 ;
     RECT  36.025 28.392 36.684 28.464 ;
     RECT  36.025 28.464 36.636 28.488 ;
     RECT  36.025 28.488 36.684 28.56 ;
     RECT  36.025 28.56 36.636 28.584 ;
     RECT  36.025 28.584 36.684 28.656 ;
     RECT  36.025 28.656 36.636 28.68 ;
     RECT  36.025 28.68 36.684 28.752 ;
     RECT  36.025 28.752 36.636 28.776 ;
     RECT  36.025 28.776 36.684 28.848 ;
     RECT  36.025 28.848 36.636 28.872 ;
     RECT  36.025 28.872 36.684 28.944 ;
     RECT  36.025 28.944 36.636 28.968 ;
     RECT  36.025 28.968 36.684 29.04 ;
     RECT  36.025 29.04 36.636 29.064 ;
     RECT  36.569 32.112 36.684 32.208 ;
     RECT  36.569 32.208 36.636 32.232 ;
     RECT  36.569 32.232 36.684 32.304 ;
     RECT  36.569 32.304 36.636 32.328 ;
     RECT  36.569 32.328 36.684 32.4 ;
     RECT  36.569 32.4 36.636 32.424 ;
     RECT  36.569 32.424 36.684 32.496 ;
     RECT  36.569 32.496 36.636 32.52 ;
     RECT  36.569 32.52 36.684 32.592 ;
     RECT  36.569 32.592 36.636 32.616 ;
     RECT  36.569 32.616 36.684 32.688 ;
     RECT  36.569 32.688 36.636 32.712 ;
     RECT  36.569 32.712 36.684 32.784 ;
     RECT  36.569 32.784 36.636 32.808 ;
     RECT  36.569 32.808 36.684 32.88 ;
     RECT  36.569 32.88 36.636 32.904 ;
     RECT  36.569 32.904 36.684 32.976 ;
     RECT  36.569 32.976 36.636 33 ;
     RECT  36.569 33 36.684 33.072 ;
     RECT  36.569 33.072 36.636 33.096 ;
     RECT  36.569 33.096 36.684 33.168 ;
     RECT  36.569 33.168 36.636 33.192 ;
     RECT  36.569 33.192 36.684 33.264 ;
     RECT  36.569 33.264 36.636 33.288 ;
     RECT  36.569 33.288 36.684 33.36 ;
     RECT  36.569 33.36 36.636 33.384 ;
     RECT  36.569 33.384 36.684 33.456 ;
     RECT  36.569 33.456 36.636 33.48 ;
     RECT  36.569 33.48 36.684 33.552 ;
     RECT  36.569 33.552 36.636 33.576 ;
     RECT  36.569 33.576 36.684 33.648 ;
     RECT  36.569 33.648 36.636 33.672 ;
     RECT  36.569 33.672 36.684 33.744 ;
     RECT  36.569 33.744 36.636 33.768 ;
     RECT  36.569 33.768 36.684 33.84 ;
     RECT  36.569 33.84 36.636 33.864 ;
     RECT  36.569 33.864 36.684 33.936 ;
     RECT  36.569 33.936 36.636 33.96 ;
     RECT  36.569 33.96 36.684 34.032 ;
     RECT  36.569 34.032 36.636 34.056 ;
     RECT  36.569 34.056 36.684 34.128 ;
     RECT  36.569 34.128 36.636 34.152 ;
     RECT  36.605 39.12 36.636 39.144 ;
     RECT  36.605 39.144 36.684 39.216 ;
     RECT  36.605 39.216 36.636 39.24 ;
     RECT  36.605 39.24 36.684 39.312 ;
     RECT  36.605 39.312 36.636 39.336 ;
     RECT  36.605 39.336 36.684 39.408 ;
     RECT  36.605 39.408 36.636 39.432 ;
     RECT  36.605 39.432 36.684 39.504 ;
     RECT  36.605 39.504 36.636 39.528 ;
     RECT  36.605 39.528 36.684 39.6 ;
     RECT  36.605 39.6 36.636 39.624 ;
     RECT  36.605 39.624 36.684 39.696 ;
     RECT  36.605 39.696 36.636 39.72 ;
     RECT  36.605 39.72 36.684 39.792 ;
     RECT  36.605 39.792 36.636 39.816 ;
     RECT  36.605 39.816 36.684 39.888 ;
     RECT  36.605 39.888 36.636 39.912 ;
     RECT  36.605 39.912 36.684 39.984 ;
     RECT  36.605 39.984 36.636 40.008 ;
     RECT  36.605 40.008 36.684 40.08 ;
     RECT  36.605 40.08 36.636 40.104 ;
     RECT  36.605 40.104 36.684 40.176 ;
     RECT  36.605 40.176 36.636 40.2 ;
     RECT  36.605 40.2 36.684 40.272 ;
     RECT  36.605 40.272 36.636 40.296 ;
     RECT  36.605 40.296 36.684 40.368 ;
     RECT  36.605 40.368 36.636 40.392 ;
     RECT  36.605 40.392 36.684 40.464 ;
     RECT  36.605 40.464 36.636 40.488 ;
     RECT  36.605 40.488 36.684 40.56 ;
     RECT  36.605 40.56 36.636 40.584 ;
     RECT  36.605 40.584 36.684 40.656 ;
     RECT  36.605 40.656 36.636 40.68 ;
     RECT  36.605 40.68 36.684 40.752 ;
     RECT  36.605 40.752 36.636 40.776 ;
     RECT  36.605 40.776 36.684 40.848 ;
     RECT  36.605 40.848 36.636 40.872 ;
     RECT  36.605 40.872 36.684 40.944 ;
     RECT  36.605 40.944 36.636 40.968 ;
     RECT  36.605 40.968 36.684 41.04 ;
     RECT  36.605 41.04 36.636 41.064 ;
     RECT  36.605 41.064 36.684 41.136 ;
     RECT  36.605 41.136 36.636 41.16 ;
     RECT  36.605 41.16 36.684 41.232 ;
     RECT  36.605 41.232 36.636 41.256 ;
     RECT  36.605 41.256 36.684 41.328 ;
     RECT  36.605 41.328 36.636 41.352 ;
     RECT  36.605 41.352 36.684 41.424 ;
     RECT  36.605 41.424 36.636 41.448 ;
     RECT  36.605 41.448 36.684 41.52 ;
     RECT  36.605 41.52 36.636 41.544 ;
     RECT  36.605 41.544 36.684 41.616 ;
     RECT  36.605 41.616 36.636 41.64 ;
     RECT  36.605 41.64 36.684 41.712 ;
     RECT  36.605 41.712 36.636 41.736 ;
     RECT  36.605 41.736 36.684 41.808 ;
     RECT  36.605 41.808 36.636 41.832 ;
     RECT  36.605 41.832 36.684 41.904 ;
     RECT  36.605 41.904 36.636 41.928 ;
     RECT  36.605 41.928 36.684 42 ;
     RECT  36.605 42 36.636 42.024 ;
     RECT  36.605 42.024 36.684 42.096 ;
     RECT  36.605 42.096 36.636 42.12 ;
     RECT  36.605 42.12 36.684 42.192 ;
     RECT  36.605 42.192 36.636 42.216 ;
     RECT  36.605 42.216 36.684 42.288 ;
     RECT  36.605 42.288 36.636 42.312 ;
     RECT  36.605 42.312 36.684 42.384 ;
     RECT  36.605 42.384 36.636 42.408 ;
     RECT  36.605 42.408 36.684 42.48 ;
     RECT  36.605 42.48 36.636 42.504 ;
     RECT  36.605 42.504 36.684 42.576 ;
     RECT  36.605 42.576 36.636 42.6 ;
     RECT  36.605 42.6 36.684 42.672 ;
     RECT  36.605 42.672 36.636 42.696 ;
     RECT  36.605 42.696 36.684 42.768 ;
     RECT  36.605 42.768 36.636 42.792 ;
     RECT  36.605 42.792 36.684 42.864 ;
     RECT  36.605 42.864 36.636 42.888 ;
     RECT  36.605 42.888 36.684 42.96 ;
     RECT  36.605 42.96 36.636 42.984 ;
     RECT  36.605 42.984 36.684 43.056 ;
     RECT  36.605 43.056 36.636 43.08 ;
     RECT  36.605 43.08 36.684 43.152 ;
     RECT  36.605 43.152 36.636 43.176 ;
     RECT  36.605 43.176 36.684 43.248 ;
     RECT  36.605 43.248 36.636 43.272 ;
     RECT  36.605 43.272 36.684 43.344 ;
     RECT  36.605 43.344 36.636 43.368 ;
     RECT  36.605 43.368 36.684 43.44 ;
     RECT  36.605 43.44 36.636 43.464 ;
     RECT  36.605 43.464 36.684 43.536 ;
     RECT  36.605 43.536 36.636 43.56 ;
     RECT  36.605 43.56 36.684 43.632 ;
     RECT  36.605 43.632 36.636 43.656 ;
     RECT  36.605 43.656 36.684 43.728 ;
     RECT  36.605 43.728 36.636 43.752 ;
     RECT  36.605 43.752 36.684 43.824 ;
     RECT  36.605 43.824 36.636 43.848 ;
     RECT  36.605 43.848 36.684 43.92 ;
     RECT  36.605 43.92 36.636 43.944 ;
     RECT  36.605 43.944 36.684 44.016 ;
     RECT  36.605 44.016 36.636 44.04 ;
     RECT  36.605 44.04 36.684 44.112 ;
     RECT  36.605 44.112 36.636 44.136 ;
     RECT  36.605 44.136 36.684 44.208 ;
     RECT  36.605 44.208 36.636 44.232 ;
     RECT  36.605 44.232 36.684 44.304 ;
     RECT  36.605 44.304 36.636 44.328 ;
     RECT  36.605 44.328 36.684 44.4 ;
     RECT  36.605 44.4 36.636 44.424 ;
     RECT  36.605 44.424 36.684 44.496 ;
     RECT  36.605 44.496 36.636 44.52 ;
     RECT  36.605 44.52 36.684 44.592 ;
     RECT  36.605 44.592 36.636 44.616 ;
     RECT  36.605 44.616 36.684 44.688 ;
     RECT  36.605 44.688 36.636 44.712 ;
     RECT  36.605 44.712 36.684 44.784 ;
     RECT  36.605 44.784 36.636 44.808 ;
     RECT  36.605 44.808 36.684 44.88 ;
     RECT  36.605 44.88 36.636 44.904 ;
     RECT  36.605 44.904 36.684 44.976 ;
     RECT  36.605 44.976 36.636 45 ;
     RECT  36.605 45 36.684 45.072 ;
     RECT  36.605 45.072 36.636 45.096 ;
     RECT  36.605 45.096 36.684 45.168 ;
     RECT  36.605 45.168 36.636 45.192 ;
     RECT  36.605 45.192 36.684 45.264 ;
     RECT  36.605 45.264 36.636 45.288 ;
     RECT  36.605 45.288 36.684 45.36 ;
     RECT  36.605 45.36 36.636 45.384 ;
     RECT  36.605 45.384 36.684 45.456 ;
     RECT  36.605 45.456 36.636 45.48 ;
     RECT  36.605 45.48 36.684 45.552 ;
     RECT  36.605 45.552 36.636 45.576 ;
     RECT  36.605 45.576 36.684 45.648 ;
     RECT  36.605 45.648 36.636 45.672 ;
     RECT  36.605 45.672 36.684 45.744 ;
     RECT  36.605 45.744 36.636 45.768 ;
     RECT  36.605 45.768 36.684 45.84 ;
     RECT  36.605 45.84 36.636 45.864 ;
     RECT  36.605 45.864 36.684 45.936 ;
     RECT  36.605 45.936 36.636 45.96 ;
     RECT  36.605 45.96 36.684 46.032 ;
     RECT  36.605 46.032 36.636 46.056 ;
     RECT  36.605 46.056 36.684 46.128 ;
     RECT  36.605 46.128 36.636 46.152 ;
     RECT  36.605 46.152 36.684 46.224 ;
     RECT  36.605 46.224 36.636 46.248 ;
     RECT  36.605 46.248 36.684 46.32 ;
     RECT  36.605 46.32 36.636 46.344 ;
     RECT  36.605 46.344 36.684 46.416 ;
     RECT  36.605 46.416 36.636 46.44 ;
     RECT  36.605 46.44 36.684 46.512 ;
     RECT  36.605 46.512 36.636 46.536 ;
     RECT  36.605 46.536 36.684 46.608 ;
     RECT  36.605 46.608 36.636 46.632 ;
     RECT  36.605 46.632 36.684 46.704 ;
     RECT  36.605 46.704 36.636 46.728 ;
     RECT  36.605 46.728 36.684 46.8 ;
     RECT  36.605 46.8 36.636 46.824 ;
     RECT  36.605 46.824 36.684 46.896 ;
     RECT  36.605 46.896 36.636 46.92 ;
     RECT  36.605 46.92 36.684 46.992 ;
     RECT  36.605 46.992 36.636 47.016 ;
     RECT  36.605 47.016 36.684 47.088 ;
     RECT  36.605 47.088 36.636 47.112 ;
     RECT  36.605 47.112 36.684 47.184 ;
     RECT  36.605 47.184 36.636 47.208 ;
     RECT  36.605 47.208 36.684 47.28 ;
     RECT  36.605 47.28 36.636 47.304 ;
     RECT  36.605 47.304 36.684 47.376 ;
     RECT  36.605 47.376 36.636 47.4 ;
     RECT  36.605 47.4 36.684 47.472 ;
     RECT  36.605 47.472 36.636 47.496 ;
     RECT  36.605 47.496 36.684 47.568 ;
     RECT  36.605 47.568 36.636 47.592 ;
     RECT  36.605 47.592 36.684 47.664 ;
     RECT  36.605 47.664 36.636 47.688 ;
     RECT  36.605 47.688 36.684 47.76 ;
     RECT  36.605 47.76 36.636 47.784 ;
     RECT  36.605 47.784 36.684 47.856 ;
     RECT  36.605 47.856 36.636 47.88 ;
     RECT  36.605 47.88 36.684 47.952 ;
     RECT  36.605 47.952 36.636 47.976 ;
     RECT  36.605 47.976 36.684 48.048 ;
     RECT  36.605 48.048 36.636 48.072 ;
     RECT  36.605 48.072 36.684 48.144 ;
     RECT  36.605 48.144 36.636 48.168 ;
     RECT  36.605 48.168 36.684 48.24 ;
     RECT  36.605 48.24 36.636 48.264 ;
     RECT  36.684 11.712 36.713 11.736 ;
     RECT  36.684 32.112 36.713 32.136 ;
     RECT  33.689 35.232 36.713 35.256 ;
    LAYER M5 ;
     RECT  2.4 2.137 2.52 2.151 ;
     RECT  5.1 2.137 5.22 2.151 ;
     RECT  7.8 2.137 7.92 2.151 ;
     RECT  10.5 2.137 10.62 2.151 ;
     RECT  13.2 2.137 13.32 2.151 ;
     RECT  15.9 2.137 16.02 2.151 ;
     RECT  18.6 2.137 18.72 2.151 ;
     RECT  21.3 2.137 21.42 2.151 ;
     RECT  24 2.137 24.12 2.151 ;
     RECT  26.7 2.137 26.82 2.151 ;
     RECT  29.4 2.137 29.52 2.151 ;
     RECT  32.1 2.137 32.22 2.151 ;
     RECT  7.8 2.151 8.112 2.245 ;
     RECT  10.5 2.151 10.812 2.245 ;
     RECT  29.4 2.151 29.712 2.293 ;
     RECT  26.7 2.151 27.012 2.677 ;
     RECT  5.1 2.151 5.412 2.821 ;
     RECT  10.5 2.245 11.304 3.061 ;
     RECT  18.6 2.151 18.912 3.301 ;
     RECT  15.9 2.151 16.212 3.349 ;
     RECT  18.6 3.301 19.368 3.397 ;
     RECT  28.512 2.293 29.712 3.587 ;
     RECT  21.3 2.151 21.612 3.685 ;
     RECT  7.8 2.245 8.664 3.877 ;
     RECT  15.9 3.349 17.16 3.925 ;
     RECT  24 2.151 24.312 3.925 ;
     RECT  25.92 2.677 27.012 3.925 ;
     RECT  29.088 3.587 29.712 3.925 ;
     RECT  7.44 3.877 8.664 4.021 ;
     RECT  9.648 3.061 11.304 4.021 ;
     RECT  7.44 4.021 11.304 4.213 ;
     RECT  29.088 3.925 30.504 4.405 ;
     RECT  7.44 4.213 11.928 4.499 ;
     RECT  4.752 2.821 5.412 4.549 ;
     RECT  22.848 4.405 22.872 4.645 ;
     RECT  18.24 3.397 19.368 4.739 ;
     RECT  24 3.925 27.012 4.787 ;
     RECT  7.8 4.499 11.928 4.789 ;
     RECT  13.2 2.151 13.512 4.789 ;
     RECT  29.088 4.405 30.984 5.027 ;
     RECT  22.656 4.645 22.872 5.029 ;
     RECT  24 4.787 24.312 5.029 ;
     RECT  25.92 4.787 27.012 5.029 ;
     RECT  15.9 3.925 17.208 5.077 ;
     RECT  4.608 4.549 5.412 5.219 ;
     RECT  22.656 5.029 24.312 5.219 ;
     RECT  15.072 5.077 17.208 5.653 ;
     RECT  25.92 5.029 27.24 6.037 ;
     RECT  7.8 4.789 13.512 6.181 ;
     RECT  20.592 3.685 21.612 6.229 ;
     RECT  24 5.219 24.312 6.229 ;
     RECT  24 6.229 24.408 6.517 ;
     RECT  22.656 5.219 22.776 6.709 ;
     RECT  7.8 6.181 13.704 6.805 ;
     RECT  15.072 5.653 17.256 6.899 ;
     RECT  7.152 6.805 13.704 6.947 ;
     RECT  7.152 6.947 11.448 6.995 ;
     RECT  25.92 6.037 27.48 7.091 ;
     RECT  25.92 7.091 27.24 7.093 ;
     RECT  7.152 6.995 9.096 7.139 ;
     RECT  7.152 7.139 8.904 7.189 ;
     RECT  24 6.517 24.456 7.189 ;
     RECT  25.632 7.093 27.24 7.189 ;
     RECT  24 7.189 27.24 7.331 ;
     RECT  29.4 5.027 30.984 7.381 ;
     RECT  29.4 7.381 31.128 7.523 ;
     RECT  18.24 4.739 19.032 7.619 ;
     RECT  17.232 6.899 17.256 7.717 ;
     RECT  18.24 7.619 18.912 7.717 ;
     RECT  0.144 7.765 0.168 7.955 ;
     RECT  22.608 6.709 22.776 8.003 ;
     RECT  26.7 7.331 27.24 8.149 ;
     RECT  20.208 6.229 21.612 8.195 ;
     RECT  15.072 6.899 16.212 8.245 ;
     RECT  17.232 7.717 18.912 8.245 ;
     RECT  6.864 7.189 8.904 8.291 ;
     RECT  12.768 6.947 13.704 8.485 ;
     RECT  15.072 8.245 18.912 8.485 ;
     RECT  29.4 7.523 29.712 8.533 ;
     RECT  32.1 2.151 32.412 8.821 ;
     RECT  20.592 8.195 21.612 9.109 ;
     RECT  22.656 8.003 22.776 9.109 ;
     RECT  20.592 9.109 22.776 9.155 ;
     RECT  30.72 7.523 31.128 9.155 ;
     RECT  12.768 8.485 18.912 9.157 ;
     RECT  35.904 9.061 35.928 9.203 ;
     RECT  32.1 8.821 33.048 9.299 ;
     RECT  24 7.331 25.656 9.397 ;
     RECT  26.7 8.149 27.48 9.397 ;
     RECT  32.1 9.299 32.412 9.445 ;
     RECT  10.5 6.995 11.448 9.589 ;
     RECT  4.752 5.219 5.412 9.637 ;
     RECT  6.624 8.485 6.648 9.637 ;
     RECT  24 9.397 27.48 9.685 ;
     RECT  23.904 9.685 27.48 9.779 ;
     RECT  23.904 9.779 27.012 9.827 ;
     RECT  30.72 9.155 30.84 9.875 ;
     RECT  3.744 7.957 3.768 9.925 ;
     RECT  4.752 9.637 6.648 9.925 ;
     RECT  30.816 9.875 30.84 10.163 ;
     RECT  7.8 8.291 8.808 10.165 ;
     RECT  7.8 10.165 9.096 10.261 ;
     RECT  12.672 9.157 18.912 10.307 ;
     RECT  7.68 10.261 9.096 10.309 ;
     RECT  12.672 10.307 17.448 10.403 ;
     RECT  3.744 9.925 6.648 10.595 ;
     RECT  12.672 10.403 14.28 10.595 ;
     RECT  21.3 9.155 22.68 10.597 ;
     RECT  7.68 10.309 9.288 10.645 ;
     RECT  10.368 9.589 11.448 10.645 ;
     RECT  18.6 10.307 18.912 10.741 ;
     RECT  24 9.827 27.012 10.741 ;
     RECT  28.704 8.533 29.712 10.741 ;
     RECT  31.968 9.445 32.412 10.789 ;
     RECT  3.744 10.595 6.6 10.835 ;
     RECT  12.768 10.595 14.28 10.931 ;
     RECT  24 10.741 29.712 10.979 ;
     RECT  31.392 10.789 32.412 11.365 ;
     RECT  24 10.979 27.624 11.411 ;
     RECT  7.68 10.645 11.448 11.459 ;
     RECT  31.392 11.365 32.568 11.461 ;
     RECT  7.68 11.459 9.144 11.507 ;
     RECT  24 11.411 27.012 11.507 ;
     RECT  7.8 11.507 9.144 11.555 ;
     RECT  35.28 11.509 35.304 11.699 ;
     RECT  18.6 10.741 19.416 11.701 ;
     RECT  31.392 11.461 32.808 11.747 ;
     RECT  18.6 11.701 19.512 11.987 ;
     RECT  31.392 11.747 32.568 11.987 ;
     RECT  12.816 10.931 14.28 12.469 ;
     RECT  15.36 10.403 17.448 12.469 ;
     RECT  24 11.507 25.56 12.515 ;
     RECT  28.704 10.979 29.712 12.517 ;
     RECT  12.816 12.469 17.592 12.563 ;
     RECT  27.984 12.517 29.712 12.755 ;
     RECT  21.3 10.597 22.92 12.901 ;
     RECT  24 12.515 25.08 12.901 ;
     RECT  13.2 12.563 17.592 12.995 ;
     RECT  10.368 11.459 11.448 13.045 ;
     RECT  14.688 12.995 17.592 13.045 ;
     RECT  18.6 11.987 19.416 13.045 ;
     RECT  21.3 12.901 25.08 13.045 ;
     RECT  7.8 11.555 9 13.285 ;
     RECT  10.368 13.045 11.784 13.285 ;
     RECT  7.8 13.285 11.784 13.379 ;
     RECT  14.688 13.045 19.416 13.381 ;
     RECT  7.8 13.379 8.664 13.427 ;
     RECT  9.792 13.379 11.784 13.427 ;
     RECT  3.744 10.835 5.88 13.429 ;
     RECT  26.7 11.507 27.012 13.477 ;
     RECT  10.5 13.427 11.784 13.573 ;
     RECT  13.2 12.995 13.512 13.573 ;
     RECT  14.688 13.381 19.992 13.715 ;
     RECT  21.12 13.045 25.08 13.715 ;
     RECT  24 13.715 25.08 13.717 ;
     RECT  26.112 13.477 27.012 13.717 ;
     RECT  10.5 13.573 13.512 13.859 ;
     RECT  24 13.717 27.012 13.909 ;
     RECT  27.984 12.755 28.008 13.909 ;
     RECT  12.528 13.859 13.512 14.149 ;
     RECT  14.688 13.715 16.632 14.149 ;
     RECT  12.528 14.149 16.632 14.291 ;
     RECT  21.12 13.715 22.92 14.291 ;
     RECT  7.8 13.427 8.112 14.389 ;
     RECT  31.392 11.987 32.412 14.485 ;
     RECT  31.392 14.485 33.384 14.819 ;
     RECT  3.744 13.429 5.928 14.867 ;
     RECT  12.528 14.291 14.712 14.867 ;
     RECT  18.096 13.715 19.992 14.867 ;
     RECT  24 13.909 28.008 14.965 ;
     RECT  29.04 12.755 29.712 14.965 ;
     RECT  31.776 14.819 33.384 15.059 ;
     RECT  24 14.965 29.712 15.493 ;
     RECT  10.5 13.859 10.812 15.589 ;
     RECT  31.776 15.059 32.412 15.635 ;
     RECT  23.712 15.493 29.712 15.731 ;
     RECT  2.4 2.151 2.712 15.829 ;
     RECT  3.744 14.867 5.592 15.829 ;
     RECT  10.5 15.589 11.976 15.829 ;
     RECT  15.792 14.291 16.632 16.019 ;
     RECT  23.712 15.731 27.012 16.019 ;
     RECT  9.216 15.973 9.24 16.117 ;
     RECT  10.5 15.829 12.024 16.117 ;
     RECT  13.2 14.867 14.712 16.163 ;
     RECT  7.584 14.389 8.112 16.309 ;
     RECT  9.12 16.117 9.24 16.309 ;
     RECT  2.4 15.829 5.592 16.355 ;
     RECT  7.584 16.309 9.24 16.405 ;
     RECT  31.824 15.635 32.412 16.405 ;
     RECT  10.5 16.117 12.12 16.595 ;
     RECT  18.192 14.867 19.992 16.595 ;
     RECT  28.512 15.731 29.712 16.643 ;
     RECT  13.2 16.163 13.656 16.645 ;
     RECT  21.12 14.291 22.488 16.741 ;
     RECT  36.528 15.781 36.552 16.885 ;
     RECT  10.5 16.595 10.92 17.027 ;
     RECT  23.712 16.019 25.08 17.029 ;
     RECT  26.16 16.019 27.012 17.029 ;
     RECT  21.072 16.741 22.728 17.123 ;
     RECT  13.104 16.645 13.656 17.171 ;
     RECT  23.712 17.029 27.012 17.171 ;
     RECT  11.952 16.595 12.12 17.317 ;
     RECT  13.104 17.171 13.608 17.317 ;
     RECT  7.392 16.405 9.24 17.507 ;
     RECT  29.232 16.643 29.712 17.605 ;
     RECT  31.824 16.405 32.76 17.651 ;
     RECT  21.12 17.123 22.728 17.747 ;
     RECT  29.232 17.605 30.12 17.747 ;
     RECT  36.48 16.885 36.552 17.989 ;
     RECT  7.392 17.507 8.952 18.037 ;
     RECT  3.744 16.355 5.592 18.083 ;
     RECT  23.712 17.171 25.704 18.181 ;
     RECT  6.72 18.037 8.952 18.227 ;
     RECT  29.28 17.747 30.12 18.275 ;
     RECT  11.952 17.317 13.608 18.421 ;
     RECT  15.792 16.019 16.212 18.421 ;
     RECT  10.5 17.027 10.812 18.469 ;
     RECT  21.12 17.747 22.2 18.469 ;
     RECT  11.952 18.421 13.656 18.659 ;
     RECT  18.192 16.595 19.512 18.661 ;
     RECT  10.128 18.469 10.812 18.755 ;
     RECT  6.72 18.227 8.52 18.851 ;
     RECT  23.328 18.181 25.704 18.851 ;
     RECT  15.792 18.421 16.344 18.995 ;
     RECT  2.4 16.355 2.712 19.093 ;
     RECT  3.744 18.083 5.412 19.093 ;
     RECT  32.1 17.651 32.412 19.237 ;
     RECT  26.7 17.171 27.012 19.333 ;
     RECT  31.968 19.237 32.412 19.333 ;
     RECT  21.072 18.469 22.2 19.429 ;
     RECT  11.952 18.659 13.608 19.571 ;
     RECT  20.976 19.429 22.2 19.571 ;
     RECT  21.072 19.571 22.2 19.667 ;
     RECT  23.712 18.851 25.704 19.717 ;
     RECT  26.7 19.333 27.432 19.717 ;
     RECT  6.72 18.851 8.424 19.909 ;
     RECT  23.712 19.717 27.432 19.909 ;
     RECT  15.9 18.995 16.344 19.955 ;
     RECT  17.808 18.661 19.512 19.957 ;
     RECT  23.712 19.909 28.008 20.243 ;
     RECT  31.968 19.333 32.712 20.339 ;
     RECT  2.4 19.093 5.412 20.533 ;
     RECT  6.432 19.909 8.424 20.533 ;
     RECT  2.4 20.533 8.424 20.725 ;
     RECT  14.688 16.163 14.712 20.773 ;
     RECT  15.9 19.955 16.212 20.773 ;
     RECT  2.4 20.725 8.952 20.867 ;
     RECT  26.7 20.243 28.008 20.867 ;
     RECT  14.688 20.773 16.212 20.915 ;
     RECT  31.968 20.339 32.412 20.965 ;
     RECT  23.712 20.243 25.464 21.059 ;
     RECT  10.5 18.755 10.812 21.109 ;
     RECT  11.952 19.571 13.512 21.109 ;
     RECT  3.744 20.867 8.952 21.155 ;
     RECT  36.48 17.989 36.6 21.299 ;
     RECT  31.44 20.965 32.412 21.781 ;
     RECT  15.9 20.915 16.212 21.925 ;
     RECT  29.4 18.275 30.12 21.925 ;
     RECT  21.168 19.667 22.2 22.019 ;
     RECT  4.416 21.155 8.952 22.021 ;
     RECT  15.9 21.925 16.392 22.067 ;
     RECT  31.44 21.781 32.52 22.067 ;
     RECT  17.808 19.957 19.752 22.069 ;
     RECT  10.5 21.109 13.512 22.115 ;
     RECT  0.288 22.021 0.312 22.163 ;
     RECT  21.168 22.019 22.008 22.259 ;
     RECT  31.44 22.067 32.412 22.741 ;
     RECT  36.576 21.299 36.6 22.835 ;
     RECT  4.416 22.021 9.096 23.075 ;
     RECT  10.5 22.115 11.4 23.173 ;
     RECT  12.528 22.115 13.512 23.173 ;
     RECT  23.712 21.059 25.272 23.173 ;
     RECT  26.7 20.867 27.432 23.173 ;
     RECT  10.5 23.173 13.512 23.219 ;
     RECT  15.9 22.067 16.212 23.221 ;
     RECT  17.808 22.069 19.992 23.221 ;
     RECT  21.168 22.259 21.768 23.221 ;
     RECT  23.712 23.173 27.432 23.269 ;
     RECT  21.12 23.221 21.768 23.317 ;
     RECT  31.344 22.741 32.412 23.317 ;
     RECT  4.416 23.075 8.52 23.411 ;
     RECT  4.992 23.411 8.52 23.459 ;
     RECT  20.976 23.317 21.768 23.699 ;
     RECT  31.344 23.317 33.048 23.891 ;
     RECT  29.28 21.925 30.12 23.939 ;
     RECT  14.688 20.915 14.712 23.987 ;
     RECT  29.4 23.939 30.12 23.987 ;
     RECT  5.1 23.459 8.52 24.035 ;
     RECT  31.344 23.891 32.412 24.131 ;
     RECT  23.712 23.269 28.248 24.181 ;
     RECT  10.5 23.219 12.024 24.371 ;
     RECT  15.9 23.221 19.992 24.469 ;
     RECT  21.12 23.699 21.768 24.707 ;
     RECT  15.792 24.469 19.992 24.901 ;
     RECT  23.04 24.181 28.248 24.997 ;
     RECT  15.696 24.901 19.992 25.091 ;
     RECT  5.1 24.035 8.424 25.189 ;
     RECT  11.808 24.371 12.024 25.283 ;
     RECT  17.616 25.091 19.992 25.283 ;
     RECT  22.8 24.997 28.248 25.283 ;
     RECT  24 25.283 28.248 25.331 ;
     RECT  11.856 25.283 12.024 25.427 ;
     RECT  12 25.427 12.024 25.475 ;
     RECT  28.08 25.331 28.248 25.477 ;
     RECT  29.4 23.987 29.712 25.477 ;
     RECT  28.08 25.477 29.712 25.573 ;
     RECT  30.72 24.517 30.744 25.573 ;
     RECT  21.168 24.707 21.768 25.765 ;
     RECT  3.888 23.701 3.912 25.957 ;
     RECT  5.1 25.189 8.52 25.957 ;
     RECT  17.616 25.283 19.848 26.003 ;
     RECT  3.888 25.957 8.52 26.051 ;
     RECT  28.08 25.573 30.744 26.101 ;
     RECT  15.696 25.091 16.344 26.197 ;
     RECT  21.168 25.765 22.2 26.197 ;
     RECT  24 25.331 27.012 26.243 ;
     RECT  28.08 26.101 30.792 26.243 ;
     RECT  4.512 26.051 8.52 26.389 ;
     RECT  13.2 23.219 13.512 26.437 ;
     RECT  4.512 26.389 9.048 26.485 ;
     RECT  4.512 26.485 9.144 26.725 ;
     RECT  21.12 26.197 22.2 26.771 ;
     RECT  14.88 26.197 16.344 26.773 ;
     RECT  26.208 26.243 27.012 26.819 ;
     RECT  30.768 26.243 30.792 26.819 ;
     RECT  12.288 26.437 13.512 26.821 ;
     RECT  14.88 26.773 16.392 26.821 ;
     RECT  4.512 26.725 9.24 27.107 ;
     RECT  21.168 26.771 22.2 27.109 ;
     RECT  26.7 26.819 27.012 27.205 ;
     RECT  28.08 26.243 29.712 27.205 ;
     RECT  24 26.243 24.84 27.301 ;
     RECT  12.288 26.821 16.392 27.395 ;
     RECT  12.528 27.395 16.392 27.445 ;
     RECT  17.616 26.003 19.752 27.445 ;
     RECT  4.512 27.107 5.736 27.685 ;
     RECT  12.528 27.445 19.752 27.829 ;
     RECT  12.528 27.829 19.992 27.877 ;
     RECT  21.168 27.109 22.776 27.877 ;
     RECT  2.4 20.867 2.712 27.925 ;
     RECT  4.32 27.685 5.736 28.165 ;
     RECT  6.72 27.107 9.24 28.165 ;
     RECT  12.528 27.877 22.776 28.595 ;
     RECT  2.4 27.925 2.808 28.691 ;
     RECT  12.528 28.595 19.896 28.691 ;
     RECT  4.32 28.165 9.24 28.741 ;
     RECT  4.32 28.741 9.48 28.787 ;
     RECT  24 27.301 25.56 28.883 ;
     RECT  14.88 28.691 19.896 28.979 ;
     RECT  12.528 28.691 13.656 29.027 ;
     RECT  4.32 28.787 8.376 29.171 ;
     RECT  15.696 28.979 19.896 29.267 ;
     RECT  24 28.883 25.128 29.269 ;
     RECT  21.168 28.595 22.776 29.317 ;
     RECT  23.808 29.269 25.128 29.317 ;
     RECT  26.7 27.205 29.712 29.411 ;
     RECT  17.712 29.267 19.608 29.603 ;
     RECT  31.824 24.131 32.412 29.603 ;
     RECT  4.32 29.171 8.232 29.651 ;
     RECT  9.456 28.787 9.48 29.699 ;
     RECT  15.9 29.267 16.392 29.699 ;
     RECT  10.5 24.371 10.812 29.749 ;
     RECT  26.7 29.411 28.056 29.795 ;
     RECT  4.56 29.651 8.232 30.083 ;
     RECT  10.5 29.749 11.112 30.085 ;
     RECT  15.9 29.699 16.344 30.179 ;
     RECT  4.56 30.083 8.112 30.275 ;
     RECT  10.5 30.085 11.208 30.469 ;
     RECT  21.168 29.317 25.128 30.803 ;
     RECT  31.92 29.603 32.412 30.853 ;
     RECT  28.032 29.795 28.056 30.949 ;
     RECT  29.4 29.411 29.712 30.949 ;
     RECT  4.56 30.275 5.544 30.995 ;
     RECT  4.56 30.995 5.412 31.187 ;
     RECT  10.5 30.469 12.024 31.189 ;
     RECT  26.7 29.795 27.012 31.189 ;
     RECT  28.032 30.949 29.712 31.189 ;
     RECT  9.696 31.189 12.024 31.237 ;
     RECT  13.056 29.027 13.656 31.237 ;
     RECT  17.712 29.603 18.912 31.285 ;
     RECT  17.664 31.285 18.912 31.381 ;
     RECT  26.7 31.189 29.712 31.475 ;
     RECT  17.664 31.381 19.032 31.477 ;
     RECT  17.664 31.477 19.992 31.619 ;
     RECT  15.9 30.179 16.212 31.717 ;
     RECT  2.4 28.691 2.712 31.765 ;
     RECT  6.72 30.275 8.112 31.765 ;
     RECT  15.792 31.717 16.212 31.813 ;
     RECT  15.792 31.813 16.632 31.859 ;
     RECT  27.984 31.475 29.712 31.861 ;
     RECT  31.344 30.853 32.412 31.861 ;
     RECT  27.984 31.861 32.412 32.243 ;
     RECT  9.696 31.237 13.656 32.387 ;
     RECT  10.5 32.387 13.656 32.389 ;
     RECT  4.8 31.187 5.412 32.437 ;
     RECT  15.9 31.859 16.632 32.485 ;
     RECT  17.664 31.619 19.752 32.485 ;
     RECT  10.5 32.389 13.8 32.531 ;
     RECT  6.72 31.765 8.52 32.629 ;
     RECT  2.4 31.765 2.856 32.723 ;
     RECT  15.9 32.485 19.752 32.725 ;
     RECT  21.168 30.803 25.08 32.725 ;
     RECT  27.984 32.243 30.504 32.771 ;
     RECT  31.92 32.243 32.412 32.771 ;
     RECT  15.9 32.725 25.08 33.049 ;
     RECT  15.9 33.049 25.032 33.059 ;
     RECT  6.72 32.629 8.952 33.107 ;
     RECT  21.3 33.059 25.032 33.107 ;
     RECT  26.7 31.475 27.012 33.205 ;
     RECT  27.984 32.771 29.712 33.205 ;
     RECT  33.456 31.861 33.48 33.251 ;
     RECT  4.8 32.437 5.736 33.347 ;
     RECT  26.7 33.205 29.712 33.539 ;
     RECT  10.5 32.531 13.704 33.587 ;
     RECT  4.848 33.347 5.736 33.635 ;
     RECT  2.4 32.723 2.808 33.683 ;
     RECT  28.224 33.539 29.712 33.683 ;
     RECT  26.7 33.539 27.012 33.829 ;
     RECT  7.104 33.107 8.952 34.165 ;
     RECT  10.5 33.587 11.256 34.165 ;
     RECT  15.9 33.059 19.992 34.499 ;
     RECT  7.104 34.165 11.256 34.547 ;
     RECT  30.912 33.589 30.936 34.643 ;
     RECT  28.464 33.683 29.712 34.645 ;
     RECT  28.464 34.645 29.832 34.691 ;
     RECT  19.968 34.499 19.992 34.693 ;
     RECT  0.144 34.453 0.168 34.739 ;
     RECT  19.968 34.693 20.28 34.739 ;
     RECT  20.256 34.739 20.28 34.741 ;
     RECT  21.3 33.107 24.552 34.741 ;
     RECT  9.888 34.547 11.256 34.787 ;
     RECT  15.9 34.499 18.912 34.787 ;
     RECT  26.256 33.829 27.012 34.981 ;
     RECT  29.088 34.691 29.832 35.317 ;
     RECT  20.256 34.741 24.552 35.459 ;
     RECT  9.936 34.787 11.256 35.699 ;
     RECT  20.256 35.459 21.912 35.749 ;
     RECT  12.528 33.587 13.704 35.797 ;
     RECT  23.52 35.459 24.552 35.843 ;
     RECT  7.104 34.547 8.568 35.941 ;
     RECT  9.936 35.699 11.208 35.941 ;
     RECT  29.088 35.317 29.928 35.989 ;
     RECT  7.104 35.941 11.208 36.275 ;
     RECT  28.512 35.989 30.504 36.277 ;
     RECT  25.728 34.981 27.012 36.467 ;
     RECT  12.528 35.797 14.472 36.613 ;
     RECT  15.9 34.787 16.488 36.613 ;
     RECT  12.528 36.613 16.488 36.659 ;
     RECT  23.904 35.843 24.552 36.659 ;
     RECT  10.5 36.275 11.208 36.709 ;
     RECT  12.528 36.659 13.752 36.709 ;
     RECT  4.848 33.635 5.412 36.757 ;
     RECT  15.264 36.659 16.488 36.803 ;
     RECT  4.8 36.757 5.412 36.899 ;
     RECT  10.5 36.709 13.752 36.947 ;
     RECT  28.512 36.277 30.792 36.949 ;
     RECT  32.1 32.771 32.412 36.949 ;
     RECT  13.008 36.947 13.752 36.995 ;
     RECT  7.104 36.275 9.384 36.997 ;
     RECT  10.5 36.947 12.024 37.043 ;
     RECT  15.36 36.803 16.488 37.091 ;
     RECT  17.616 34.787 18.912 37.091 ;
     RECT  19.92 35.749 21.912 37.091 ;
     RECT  6.912 36.997 9.384 37.093 ;
     RECT  19.92 37.091 19.944 37.139 ;
     RECT  28.512 36.949 32.412 37.139 ;
     RECT  21.3 37.091 21.912 37.189 ;
     RECT  23.904 36.659 24.504 37.235 ;
     RECT  4.848 36.899 5.412 37.861 ;
     RECT  13.056 36.995 13.752 37.861 ;
     RECT  15.36 37.091 16.212 37.861 ;
     RECT  13.056 37.861 16.212 38.003 ;
     RECT  2.4 33.683 2.712 38.197 ;
     RECT  21.3 37.189 22.824 38.197 ;
     RECT  20.544 38.197 22.824 38.291 ;
     RECT  17.664 37.091 18.912 38.531 ;
     RECT  26.208 36.467 27.012 38.533 ;
     RECT  13.056 38.003 13.848 38.629 ;
     RECT  31.584 37.139 32.412 38.677 ;
     RECT  6.864 37.093 9.384 38.725 ;
     RECT  10.5 37.043 11.208 38.725 ;
     RECT  2.4 38.197 2.904 38.771 ;
     RECT  20.544 38.291 21.72 38.867 ;
     RECT  31.584 38.677 32.664 38.867 ;
     RECT  24 37.235 24.504 38.917 ;
     RECT  31.632 38.867 32.664 39.013 ;
     RECT  14.832 38.003 16.212 39.059 ;
     RECT  24 38.917 24.744 39.059 ;
     RECT  28.512 37.139 29.928 39.251 ;
     RECT  31.632 39.013 33 39.251 ;
     RECT  26.208 38.533 27.384 39.253 ;
     RECT  22.8 38.291 22.824 39.301 ;
     RECT  24 39.059 24.696 39.301 ;
     RECT  13.008 38.629 13.848 39.395 ;
     RECT  13.008 39.395 13.656 39.635 ;
     RECT  6.864 38.725 11.208 39.685 ;
     RECT  14.832 39.059 14.856 39.733 ;
     RECT  6.864 39.685 11.448 39.779 ;
     RECT  18.096 38.531 18.912 39.779 ;
     RECT  31.632 39.251 32.664 39.779 ;
     RECT  2.4 38.771 2.712 39.829 ;
     RECT  14.784 39.733 14.856 39.923 ;
     RECT  26.112 39.253 27.384 39.923 ;
     RECT  4.704 37.861 5.412 39.973 ;
     RECT  7.104 39.779 11.448 40.019 ;
     RECT  15.9 39.059 16.212 40.357 ;
     RECT  31.632 39.779 32.412 40.405 ;
     RECT  20.592 38.867 21.72 40.451 ;
     RECT  22.8 39.301 24.696 40.499 ;
     RECT  26.112 39.923 27.012 40.549 ;
     RECT  22.8 40.499 22.968 40.691 ;
     RECT  25.68 40.549 27.012 40.691 ;
     RECT  7.8 40.019 11.448 40.741 ;
     RECT  24 40.499 24.696 40.835 ;
     RECT  4.704 39.973 5.544 40.837 ;
     RECT  7.8 40.741 11.736 40.883 ;
     RECT  31.104 40.405 32.412 41.027 ;
     RECT  14.784 39.923 14.808 41.075 ;
     RECT  13.104 39.635 13.656 41.123 ;
     RECT  7.8 40.883 11.208 41.171 ;
     RECT  2.4 39.829 2.808 41.219 ;
     RECT  15.9 40.357 17.064 41.269 ;
     RECT  0.144 39.061 0.168 41.315 ;
     RECT  26.112 40.691 27.012 41.461 ;
     RECT  2.4 41.219 2.712 41.509 ;
     RECT  26.112 41.461 27.144 41.651 ;
     RECT  2.304 41.509 2.712 41.699 ;
     RECT  10.368 41.171 11.208 41.699 ;
     RECT  4.704 40.837 5.64 41.941 ;
     RECT  10.5 41.699 11.208 41.941 ;
     RECT  28.752 39.251 29.928 42.037 ;
     RECT  31.104 41.027 31.128 42.037 ;
     RECT  32.1 41.027 32.412 42.133 ;
     RECT  10.5 41.941 11.4 42.227 ;
     RECT  22.944 40.691 22.968 42.227 ;
     RECT  28.752 42.037 31.128 42.277 ;
     RECT  32.1 42.133 32.52 42.277 ;
     RECT  28.752 42.277 32.52 42.659 ;
     RECT  26.592 41.651 27.144 42.661 ;
     RECT  4.512 41.941 5.64 42.707 ;
     RECT  15.792 41.269 17.064 42.707 ;
     RECT  2.4 41.699 2.712 42.709 ;
     RECT  18.432 39.779 18.912 42.709 ;
     RECT  24 40.835 24.456 42.757 ;
     RECT  13.104 41.123 13.608 42.901 ;
     RECT  15.792 42.707 16.212 43.043 ;
     RECT  18.432 42.709 19.32 43.093 ;
     RECT  17.52 43.093 19.32 43.139 ;
     RECT  7.8 41.171 9.384 43.285 ;
     RECT  24 42.757 24.648 43.621 ;
     RECT  0.192 43.477 0.216 43.667 ;
     RECT  2.4 42.709 3.096 43.811 ;
     RECT  13.104 42.901 14.232 43.813 ;
     RECT  18.6 43.139 19.32 43.813 ;
     RECT  20.592 40.451 21.612 43.813 ;
     RECT  29.088 42.659 32.52 43.861 ;
     RECT  29.088 43.861 32.952 43.907 ;
     RECT  4.512 42.707 5.544 43.955 ;
     RECT  12.528 43.813 14.232 43.955 ;
     RECT  29.088 43.907 30.84 43.955 ;
     RECT  29.088 43.955 30.792 44.051 ;
     RECT  26.112 42.661 27.144 44.245 ;
     RECT  25.92 44.245 27.144 44.389 ;
     RECT  0.144 44.245 0.168 44.435 ;
     RECT  4.752 43.955 5.544 44.437 ;
     RECT  15.9 43.043 16.212 44.437 ;
     RECT  25.92 44.389 27.192 44.437 ;
     RECT  7.392 43.285 9.384 44.483 ;
     RECT  15.792 44.437 16.212 44.821 ;
     RECT  23.664 43.621 24.648 44.821 ;
     RECT  22.848 44.821 24.648 44.867 ;
     RECT  4.752 44.437 6.264 44.965 ;
     RECT  7.392 44.483 8.112 44.965 ;
     RECT  17.52 43.139 17.544 45.013 ;
     RECT  18.6 43.813 21.612 45.013 ;
     RECT  14.832 44.821 16.212 45.059 ;
     RECT  29.088 44.051 29.928 45.155 ;
     RECT  4.512 44.965 6.264 45.203 ;
     RECT  23.904 44.867 24.648 45.253 ;
     RECT  23.904 45.253 24.888 45.491 ;
     RECT  25.92 44.437 27.336 45.635 ;
     RECT  4.512 45.203 5.688 45.731 ;
     RECT  26.112 45.635 27.336 45.731 ;
     RECT  22.848 44.867 22.872 45.827 ;
     RECT  17.52 45.013 21.612 45.971 ;
     RECT  15.744 45.059 16.212 46.021 ;
     RECT  18.24 45.971 19.32 46.211 ;
     RECT  15.072 46.021 16.212 46.261 ;
     RECT  7.296 44.965 8.112 46.357 ;
     RECT  9.12 44.483 9.384 46.357 ;
     RECT  10.5 42.227 11.208 46.501 ;
     RECT  12.528 43.955 13.512 46.501 ;
     RECT  32.1 43.907 32.952 46.501 ;
     RECT  7.296 46.357 9.384 46.595 ;
     RECT  9.36 46.595 9.384 46.693 ;
     RECT  10.5 46.501 13.512 46.693 ;
     RECT  7.296 46.595 8.376 46.739 ;
     RECT  23.904 45.491 24.792 46.741 ;
     RECT  23.904 46.741 25.128 46.787 ;
     RECT  26.7 45.731 27.336 46.789 ;
     RECT  26.544 46.789 27.336 46.835 ;
     RECT  31.968 46.501 32.952 46.835 ;
     RECT  24 46.787 25.128 46.837 ;
     RECT  24 46.837 25.32 46.979 ;
     RECT  14.592 46.261 16.212 47.027 ;
     RECT  7.392 46.739 8.376 47.075 ;
     RECT  25.296 46.979 25.32 47.075 ;
     RECT  31.968 46.835 32.52 47.075 ;
     RECT  14.592 47.027 14.616 47.171 ;
     RECT  4.512 45.731 5.64 47.363 ;
     RECT  7.392 47.075 8.112 47.363 ;
     RECT  9.36 46.693 13.512 47.363 ;
     RECT  20.784 45.971 21.612 47.363 ;
     RECT  29.136 45.155 29.928 47.363 ;
     RECT  5.1 47.363 5.64 47.507 ;
     RECT  29.136 47.363 29.712 47.507 ;
     RECT  9.36 47.363 12.024 47.939 ;
     RECT  26.544 46.835 27.012 47.939 ;
     RECT  18.24 46.211 18.912 48.371 ;
     RECT  31.968 47.075 32.412 48.421 ;
     RECT  9.6 47.939 12.024 48.659 ;
     RECT  9.6 48.659 11.4 48.899 ;
     RECT  13.104 47.363 13.512 48.995 ;
     RECT  31.92 48.421 32.412 49.235 ;
     RECT  2.4 43.811 2.712 49.689 ;
     RECT  5.1 47.507 5.412 49.689 ;
     RECT  7.8 47.363 8.112 49.689 ;
     RECT  13.2 48.995 13.512 49.689 ;
     RECT  15.9 47.027 16.212 49.689 ;
     RECT  18.6 48.371 18.912 49.689 ;
     RECT  21.3 47.363 21.612 49.689 ;
     RECT  24 46.979 24.312 49.689 ;
     RECT  26.7 47.939 27.012 49.689 ;
     RECT  29.4 47.507 29.712 49.689 ;
     RECT  32.1 49.235 32.412 49.689 ;
     RECT  2.4 49.689 2.52 49.703 ;
     RECT  5.1 49.689 5.22 49.703 ;
     RECT  7.8 49.689 7.92 49.703 ;
     RECT  10.5 48.899 11.4 49.703 ;
     RECT  13.2 49.689 13.32 49.703 ;
     RECT  15.9 49.689 16.02 49.703 ;
     RECT  18.6 49.689 18.72 49.703 ;
     RECT  21.3 49.689 21.42 49.703 ;
     RECT  24 49.689 24.12 49.703 ;
     RECT  26.7 49.689 26.82 49.703 ;
     RECT  29.4 49.689 29.52 49.703 ;
     RECT  32.1 49.689 32.22 49.703 ;
     RECT  11.088 49.703 11.4 51.756 ;
     RECT  11.112 51.756 11.184 51.792 ;
     RECT  11.208 51.756 11.28 51.792 ;
     RECT  11.304 51.756 11.376 51.792 ;
     RECT  27.012 2.293 28.512 3.587 ;
     RECT  8.664 3.061 9.648 4.021 ;
     RECT  17.16 3.349 18.6 3.397 ;
     RECT  17.16 3.397 18.24 3.925 ;
     RECT  27.012 3.587 27.24 5.029 ;
     RECT  19.368 3.685 20.592 4.739 ;
     RECT  17.208 3.925 18.24 5.653 ;
     RECT  11.928 4.213 13.2 4.789 ;
     RECT  21.612 4.405 22.848 4.645 ;
     RECT  22.872 4.405 24 5.029 ;
     RECT  30.984 4.405 32.1 7.381 ;
     RECT  21.612 4.645 22.656 6.709 ;
     RECT  19.032 4.739 20.592 6.229 ;
     RECT  24.312 4.787 25.92 6.229 ;
     RECT  22.776 5.219 24 9.155 ;
     RECT  17.256 5.653 18.24 7.717 ;
     RECT  13.704 6.181 15.072 8.485 ;
     RECT  19.032 6.229 20.208 7.619 ;
     RECT  24.408 6.229 25.92 6.517 ;
     RECT  24.456 6.517 25.92 7.093 ;
     RECT  21.612 6.709 22.608 8.003 ;
     RECT  16.212 6.899 17.232 8.245 ;
     RECT  11.448 6.947 12.768 9.157 ;
     RECT  9.096 6.995 10.5 7.139 ;
     RECT  27.24 7.091 27.48 8.149 ;
     RECT  24.456 7.093 25.632 7.189 ;
     RECT  5.412 7.189 6.864 8.291 ;
     RECT  25.656 7.331 26.7 9.397 ;
     RECT  31.128 7.381 32.1 9.155 ;
     RECT  29.712 7.523 30.72 9.875 ;
     RECT  18.912 7.619 20.208 8.195 ;
     RECT  2.712 7.957 3.744 15.829 ;
     RECT  3.768 7.957 4.752 9.925 ;
     RECT  21.612 8.003 22.656 9.109 ;
     RECT  5.412 8.291 7.8 8.485 ;
     RECT  5.412 8.485 6.624 9.637 ;
     RECT  6.648 8.485 7.8 10.261 ;
     RECT  27.48 8.533 28.704 9.779 ;
     RECT  22.68 9.155 24 9.685 ;
     RECT  30.84 9.155 32.1 9.445 ;
     RECT  11.448 9.157 12.672 10.595 ;
     RECT  30.84 9.445 31.968 10.163 ;
     RECT  22.68 9.685 23.904 9.827 ;
     RECT  27.012 9.779 28.704 10.741 ;
     RECT  22.68 9.827 24 10.597 ;
     RECT  29.712 9.875 30.816 10.163 ;
     RECT  31.392 10.163 31.968 10.789 ;
     RECT  9.096 10.165 10.368 10.309 ;
     RECT  6.648 10.261 7.68 10.595 ;
     RECT  17.448 10.307 18.6 12.469 ;
     RECT  9.288 10.309 10.368 10.645 ;
     RECT  14.28 10.403 15.36 12.469 ;
     RECT  6.6 10.595 7.68 10.835 ;
     RECT  11.448 10.595 12.768 10.931 ;
     RECT  22.92 10.597 24 12.901 ;
     RECT  11.448 10.931 12.816 12.563 ;
     RECT  27.624 10.979 28.704 11.411 ;
     RECT  27.012 11.411 28.704 12.517 ;
     RECT  9.144 11.459 10.368 11.555 ;
     RECT  25.56 11.507 26.7 12.515 ;
     RECT  9 11.555 10.368 13.285 ;
     RECT  19.416 11.987 19.512 13.381 ;
     RECT  17.592 12.469 18.6 13.045 ;
     RECT  25.08 12.515 26.7 13.477 ;
     RECT  27.012 12.517 27.984 13.909 ;
     RECT  11.448 12.563 13.2 13.045 ;
     RECT  28.008 12.755 29.04 14.965 ;
     RECT  13.512 12.995 14.688 14.149 ;
     RECT  11.784 13.045 13.2 13.573 ;
     RECT  8.664 13.379 9.792 13.427 ;
     RECT  19.992 13.381 21.12 16.595 ;
     RECT  25.08 13.477 26.112 13.717 ;
     RECT  16.632 13.715 18.096 14.867 ;
     RECT  22.92 13.715 24 14.291 ;
     RECT  14.712 14.291 15.792 18.995 ;
     RECT  22.488 14.291 24 15.493 ;
     RECT  12.528 14.867 13.2 15.589 ;
     RECT  32.412 15.059 32.76 16.405 ;
     RECT  22.488 15.493 23.712 16.741 ;
     RECT  11.976 15.589 13.2 15.829 ;
     RECT  27.012 15.731 28.512 16.643 ;
     RECT  12.024 15.829 13.2 16.117 ;
     RECT  8.112 15.973 9.216 16.117 ;
     RECT  9.24 15.973 10.5 17.507 ;
     RECT  25.08 16.019 26.16 17.029 ;
     RECT  8.112 16.117 9.12 16.309 ;
     RECT  12.12 16.117 13.2 16.645 ;
     RECT  13.656 16.163 14.688 17.171 ;
     RECT  2.712 16.355 3.744 19.093 ;
     RECT  10.92 16.595 11.952 17.027 ;
     RECT  21.072 16.595 21.12 16.741 ;
     RECT  12.12 16.645 13.104 17.317 ;
     RECT  22.728 16.741 23.712 17.747 ;
     RECT  10.812 17.027 11.952 21.109 ;
     RECT  21.072 17.123 21.12 18.469 ;
     RECT  13.608 17.171 14.688 18.421 ;
     RECT  25.704 17.171 26.7 19.717 ;
     RECT  8.952 17.507 10.5 18.227 ;
     RECT  22.2 17.747 23.712 18.181 ;
     RECT  5.592 18.037 6.72 18.083 ;
     RECT  5.412 18.083 6.72 19.909 ;
     RECT  22.2 18.181 23.328 18.851 ;
     RECT  10.128 18.227 10.5 18.469 ;
     RECT  13.656 18.421 14.688 18.659 ;
     RECT  13.608 18.659 14.688 19.571 ;
     RECT  16.344 18.661 17.808 19.955 ;
     RECT  22.2 18.851 23.712 22.019 ;
     RECT  14.712 18.995 15.9 20.773 ;
     RECT  19.512 19.429 20.976 19.571 ;
     RECT  13.512 19.571 14.688 23.987 ;
     RECT  19.512 19.571 21.072 19.667 ;
     RECT  19.512 19.667 21.168 19.957 ;
     RECT  5.412 19.909 6.432 20.533 ;
     RECT  28.008 19.909 29.4 20.867 ;
     RECT  19.752 19.957 21.168 22.069 ;
     RECT  25.464 20.243 26.7 21.059 ;
     RECT  32.412 20.339 32.52 21.781 ;
     RECT  2.712 20.867 3.744 21.155 ;
     RECT  29.28 20.867 29.4 21.925 ;
     RECT  14.712 20.915 15.9 23.987 ;
     RECT  30.12 20.965 31.44 22.741 ;
     RECT  25.272 21.059 26.7 23.173 ;
     RECT  16.392 21.925 17.808 22.067 ;
     RECT  9.096 22.021 10.5 23.075 ;
     RECT  16.212 22.067 17.808 23.221 ;
     RECT  32.412 22.067 32.52 23.317 ;
     RECT  19.992 22.069 21.168 23.221 ;
     RECT  11.4 22.115 12.528 23.173 ;
     RECT  30.12 22.741 31.344 23.987 ;
     RECT  12.024 23.219 13.2 25.475 ;
     RECT  19.992 23.221 21.12 23.317 ;
     RECT  28.248 23.269 29.28 23.939 ;
     RECT  19.992 23.317 20.976 23.699 ;
     RECT  4.416 23.411 4.992 23.459 ;
     RECT  4.416 23.459 5.1 23.701 ;
     RECT  19.992 23.699 21.12 24.707 ;
     RECT  2.712 23.701 3.888 26.051 ;
     RECT  3.912 23.701 5.1 25.957 ;
     RECT  28.248 23.939 29.4 25.477 ;
     RECT  15.696 23.987 15.9 24.469 ;
     RECT  29.712 23.987 31.344 24.131 ;
     RECT  8.424 24.035 8.52 25.189 ;
     RECT  29.712 24.131 31.824 24.517 ;
     RECT  21.768 24.181 23.04 24.997 ;
     RECT  10.812 24.371 11.808 25.283 ;
     RECT  15.696 24.469 15.792 24.901 ;
     RECT  29.712 24.517 30.72 25.573 ;
     RECT  30.744 24.517 31.824 26.101 ;
     RECT  19.992 24.707 21.168 25.283 ;
     RECT  21.768 24.997 22.8 25.283 ;
     RECT  16.344 25.091 17.616 26.773 ;
     RECT  10.812 25.283 11.856 25.427 ;
     RECT  19.848 25.283 21.168 26.003 ;
     RECT  21.768 25.283 22.2 25.765 ;
     RECT  27.012 25.331 28.08 27.205 ;
     RECT  10.812 25.427 12 25.475 ;
     RECT  10.812 25.475 13.2 26.437 ;
     RECT  19.752 26.003 21.168 26.197 ;
     RECT  30.792 26.101 31.824 26.819 ;
     RECT  13.512 26.197 14.88 26.821 ;
     RECT  19.752 26.197 21.12 26.771 ;
     RECT  24.84 26.243 26.208 26.819 ;
     RECT  29.712 26.243 30.768 26.819 ;
     RECT  9.048 26.389 10.5 26.485 ;
     RECT  10.812 26.437 12.288 27.395 ;
     RECT  9.144 26.485 10.5 26.725 ;
     RECT  9.24 26.725 10.5 28.741 ;
     RECT  19.752 26.771 21.168 27.829 ;
     RECT  16.392 26.773 17.616 27.445 ;
     RECT  24.84 26.819 26.7 27.301 ;
     RECT  5.736 27.107 6.72 28.165 ;
     RECT  22.776 27.109 24 29.269 ;
     RECT  25.56 27.301 26.7 28.883 ;
     RECT  19.992 27.829 21.168 27.877 ;
     RECT  2.808 27.925 4.32 28.691 ;
     RECT  19.896 28.595 21.168 29.267 ;
     RECT  13.656 28.691 14.88 28.979 ;
     RECT  9.48 28.741 10.5 29.699 ;
     RECT  8.376 28.787 9.456 29.171 ;
     RECT  12.528 29.027 13.056 29.749 ;
     RECT  8.232 29.171 9.456 29.699 ;
     RECT  16.392 29.267 17.712 29.699 ;
     RECT  22.776 29.269 23.808 29.317 ;
     RECT  28.056 29.411 29.4 30.949 ;
     RECT  31.824 29.603 31.92 30.853 ;
     RECT  8.232 29.699 10.5 30.083 ;
     RECT  16.344 29.699 17.712 30.179 ;
     RECT  11.112 29.749 13.056 30.085 ;
     RECT  27.012 29.795 28.032 31.189 ;
     RECT  9.696 30.083 10.5 31.189 ;
     RECT  11.208 30.085 13.056 30.469 ;
     RECT  16.212 30.179 17.712 31.285 ;
     RECT  5.544 30.275 6.72 30.995 ;
     RECT  12.024 30.469 13.056 31.237 ;
     RECT  5.412 30.995 6.72 32.437 ;
     RECT  16.212 31.285 17.664 31.813 ;
     RECT  27.012 31.475 27.984 33.205 ;
     RECT  19.992 31.477 21.168 31.619 ;
     RECT  19.752 31.619 21.168 32.725 ;
     RECT  8.52 31.765 9.696 32.387 ;
     RECT  16.632 31.813 17.664 32.485 ;
     RECT  32.412 31.861 33.456 33.251 ;
     RECT  30.504 32.243 31.92 32.771 ;
     RECT  8.52 32.387 8.952 32.629 ;
     RECT  5.736 32.437 6.72 33.107 ;
     RECT  29.712 32.771 32.1 33.589 ;
     RECT  19.992 33.059 21.3 34.693 ;
     RECT  5.736 33.107 7.104 33.635 ;
     RECT  27.012 33.539 28.224 33.683 ;
     RECT  11.256 33.587 12.528 35.699 ;
     RECT  29.712 33.589 30.912 34.643 ;
     RECT  30.936 33.589 32.1 34.643 ;
     RECT  27.012 33.683 28.464 34.691 ;
     RECT  18.912 34.499 19.968 34.739 ;
     RECT  8.568 34.547 9.888 34.787 ;
     RECT  29.712 34.643 30.504 34.645 ;
     RECT  29.832 34.645 30.504 35.317 ;
     RECT  27.012 34.691 29.088 35.989 ;
     RECT  20.28 34.693 21.3 34.741 ;
     RECT  18.912 34.739 20.256 35.749 ;
     RECT  8.568 34.787 9.936 35.941 ;
     RECT  16.488 34.787 17.616 37.091 ;
     RECT  24.552 34.981 25.728 36.467 ;
     RECT  29.928 35.317 30.504 35.989 ;
     RECT  11.208 35.699 12.528 36.709 ;
     RECT  18.912 35.749 19.92 37.139 ;
     RECT  14.472 35.797 15.9 36.613 ;
     RECT  23.52 35.843 23.904 37.189 ;
     RECT  27.012 35.989 28.512 38.533 ;
     RECT  9.384 36.275 10.5 38.725 ;
     RECT  30.792 36.277 32.1 36.949 ;
     RECT  13.752 36.659 15.264 36.803 ;
     RECT  13.752 36.803 15.36 37.861 ;
     RECT  4.8 36.899 4.848 37.861 ;
     RECT  12.024 36.947 13.008 36.995 ;
     RECT  12.024 36.995 13.056 37.043 ;
     RECT  5.412 36.997 6.912 37.093 ;
     RECT  16.212 37.091 17.664 38.531 ;
     RECT  19.944 37.091 21.3 37.139 ;
     RECT  5.412 37.093 6.864 39.779 ;
     RECT  20.544 37.139 21.3 38.197 ;
     RECT  22.824 37.189 23.904 37.235 ;
     RECT  22.824 37.235 24 39.301 ;
     RECT  13.848 38.003 14.832 39.395 ;
     RECT  21.72 38.291 22.8 40.451 ;
     RECT  27.384 38.533 28.512 39.251 ;
     RECT  2.712 38.771 2.808 39.829 ;
     RECT  24.744 38.917 26.208 39.059 ;
     RECT  14.856 39.059 15.9 39.923 ;
     RECT  24.696 39.059 26.208 39.253 ;
     RECT  27.384 39.251 28.752 39.923 ;
     RECT  24.696 39.253 26.112 40.549 ;
     RECT  13.656 39.395 14.832 39.733 ;
     RECT  13.008 39.635 13.104 40.741 ;
     RECT  13.656 39.733 14.784 41.075 ;
     RECT  5.412 39.779 7.104 39.973 ;
     RECT  18.096 39.779 18.432 40.357 ;
     RECT  14.808 39.923 15.9 41.075 ;
     RECT  5.544 39.973 7.104 40.019 ;
     RECT  5.544 40.019 5.64 40.837 ;
     RECT  17.064 40.357 18.432 42.707 ;
     RECT  29.928 40.405 31.104 42.037 ;
     RECT  21.612 40.451 22.8 40.691 ;
     RECT  22.968 40.499 24 42.227 ;
     RECT  24.696 40.549 25.68 40.691 ;
     RECT  21.612 40.691 22.944 42.227 ;
     RECT  24.696 40.691 26.112 40.835 ;
     RECT  11.736 40.741 13.104 40.883 ;
     RECT  11.208 40.883 11.4 41.941 ;
     RECT  31.128 41.027 32.1 42.277 ;
     RECT  15.792 41.075 15.9 41.269 ;
     RECT  9.384 41.171 10.368 41.699 ;
     RECT  2.712 41.219 2.808 42.709 ;
     RECT  26.112 41.651 26.592 42.661 ;
     RECT  9.384 41.699 10.5 46.693 ;
     RECT  23.664 42.227 24 43.621 ;
     RECT  16.212 42.707 18.432 43.093 ;
     RECT  3.096 42.709 4.512 43.811 ;
     RECT  19.32 42.709 20.592 43.813 ;
     RECT  24.648 42.757 26.112 44.245 ;
     RECT  15.792 43.043 15.9 44.437 ;
     RECT  16.212 43.093 17.52 45.971 ;
     RECT  17.544 43.139 18.6 45.013 ;
     RECT  11.208 43.813 12.528 46.501 ;
     RECT  30.84 43.907 32.1 43.955 ;
     RECT  4.512 43.955 4.752 44.965 ;
     RECT  13.512 43.955 14.232 44.821 ;
     RECT  30.792 43.955 32.1 44.051 ;
     RECT  24.648 44.245 25.92 45.253 ;
     RECT  6.264 44.437 7.392 44.965 ;
     RECT  8.112 44.483 9.12 46.357 ;
     RECT  13.512 44.821 14.832 45.059 ;
     RECT  21.612 44.821 22.848 45.827 ;
     RECT  22.872 44.867 23.904 45.827 ;
     RECT  6.264 44.965 7.296 45.203 ;
     RECT  13.512 45.059 15.744 46.021 ;
     RECT  24.888 45.253 25.92 45.491 ;
     RECT  24.792 45.491 25.92 45.635 ;
     RECT  24.792 45.635 26.112 45.731 ;
     RECT  24.792 45.731 26.7 46.741 ;
     RECT  19.32 45.971 20.784 46.211 ;
     RECT  13.512 46.021 15.072 46.261 ;
     RECT  13.512 46.261 14.592 47.171 ;
     RECT  8.376 46.595 9.36 47.075 ;
     RECT  25.128 46.741 26.7 46.789 ;
     RECT  25.128 46.789 26.544 46.837 ;
     RECT  25.32 46.837 26.544 47.075 ;
     RECT  24.312 46.979 25.296 47.075 ;
     RECT  14.616 47.027 15.9 47.171 ;
     RECT  8.112 47.075 9.36 47.939 ;
     RECT  12.024 47.363 13.104 48.659 ;
     RECT  8.112 47.939 9.6 48.899 ;
  END
END dsfd_dvland_276
END LIBRARY
